# Generated deterministically by seda-macro-lef-normalizer-v1; recipe orfs-asap7-fakeram-m4-v1.
VERSION 5.8 ;
BUSBITCHARS "[]" ;
DIVIDERCHAR "/" ;

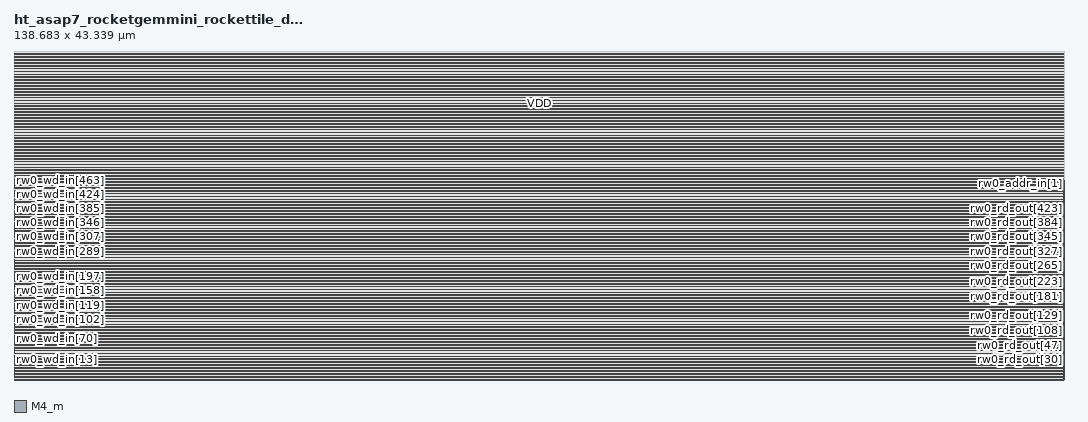
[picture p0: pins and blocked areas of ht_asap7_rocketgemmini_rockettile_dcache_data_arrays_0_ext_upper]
MACRO ht_asap7_rocketgemmini_rockettile_dcache_data_arrays_0_ext_upper
  FOREIGN ht_asap7_rocketgemmini_rockettile_dcache_data_arrays_0_ext_upper 0 0 ;
  CLASS COVER ;
  ORIGIN 0 0 ;
  SIZE 138.683 BY 43.339 ;
  SYMMETRY X Y R90 ;
  PIN rw0_wmask_in[0]
    DIRECTION INPUT ;
    USE SIGNAL ;
    SHAPE ABUTMENT ;
    PORT
      LAYER M4_m ;
      RECT 0 0.048 0.024 0.072 ;
    END
  END rw0_wmask_in[0]
  PIN rw0_wmask_in[1]
    DIRECTION INPUT ;
    USE SIGNAL ;
    SHAPE ABUTMENT ;
    PORT
      LAYER M4_m ;
      RECT 0 0.096 0.024 0.12 ;
    END
  END rw0_wmask_in[1]
  PIN rw0_wmask_in[2]
    DIRECTION INPUT ;
    USE SIGNAL ;
    SHAPE ABUTMENT ;
    PORT
      LAYER M4_m ;
      RECT 0 0.144 0.024 0.168 ;
    END
  END rw0_wmask_in[2]
  PIN rw0_wmask_in[3]
    DIRECTION INPUT ;
    USE SIGNAL ;
    SHAPE ABUTMENT ;
    PORT
      LAYER M4_m ;
      RECT 0 0.192 0.024 0.216 ;
    END
  END rw0_wmask_in[3]
  PIN rw0_wmask_in[4]
    DIRECTION INPUT ;
    USE SIGNAL ;
    SHAPE ABUTMENT ;
    PORT
      LAYER M4_m ;
      RECT 0 0.24 0.024 0.264 ;
    END
  END rw0_wmask_in[4]
  PIN rw0_wmask_in[5]
    DIRECTION INPUT ;
    USE SIGNAL ;
    SHAPE ABUTMENT ;
    PORT
      LAYER M4_m ;
      RECT 0 0.288 0.024 0.312 ;
    END
  END rw0_wmask_in[5]
  PIN rw0_wmask_in[6]
    DIRECTION INPUT ;
    USE SIGNAL ;
    SHAPE ABUTMENT ;
    PORT
      LAYER M4_m ;
      RECT 0 0.336 0.024 0.36 ;
    END
  END rw0_wmask_in[6]
  PIN rw0_wmask_in[7]
    DIRECTION INPUT ;
    USE SIGNAL ;
    SHAPE ABUTMENT ;
    PORT
      LAYER M4_m ;
      RECT 0 0.384 0.024 0.408 ;
    END
  END rw0_wmask_in[7]
  PIN rw0_wmask_in[8]
    DIRECTION INPUT ;
    USE SIGNAL ;
    SHAPE ABUTMENT ;
    PORT
      LAYER M4_m ;
      RECT 0 0.432 0.024 0.456 ;
    END
  END rw0_wmask_in[8]
  PIN rw0_wmask_in[9]
    DIRECTION INPUT ;
    USE SIGNAL ;
    SHAPE ABUTMENT ;
    PORT
      LAYER M4_m ;
      RECT 0 0.48 0.024 0.504 ;
    END
  END rw0_wmask_in[9]
  PIN rw0_wmask_in[10]
    DIRECTION INPUT ;
    USE SIGNAL ;
    SHAPE ABUTMENT ;
    PORT
      LAYER M4_m ;
      RECT 0 0.528 0.024 0.552 ;
    END
  END rw0_wmask_in[10]
  PIN rw0_wmask_in[11]
    DIRECTION INPUT ;
    USE SIGNAL ;
    SHAPE ABUTMENT ;
    PORT
      LAYER M4_m ;
      RECT 0 0.576 0.024 0.6 ;
    END
  END rw0_wmask_in[11]
  PIN rw0_wmask_in[12]
    DIRECTION INPUT ;
    USE SIGNAL ;
    SHAPE ABUTMENT ;
    PORT
      LAYER M4_m ;
      RECT 0 0.624 0.024 0.648 ;
    END
  END rw0_wmask_in[12]
  PIN rw0_wmask_in[13]
    DIRECTION INPUT ;
    USE SIGNAL ;
    SHAPE ABUTMENT ;
    PORT
      LAYER M4_m ;
      RECT 0 0.672 0.024 0.696 ;
    END
  END rw0_wmask_in[13]
  PIN rw0_wmask_in[14]
    DIRECTION INPUT ;
    USE SIGNAL ;
    SHAPE ABUTMENT ;
    PORT
      LAYER M4_m ;
      RECT 0 0.72 0.024 0.744 ;
    END
  END rw0_wmask_in[14]
  PIN rw0_wmask_in[15]
    DIRECTION INPUT ;
    USE SIGNAL ;
    SHAPE ABUTMENT ;
    PORT
      LAYER M4_m ;
      RECT 0 0.768 0.024 0.792 ;
    END
  END rw0_wmask_in[15]
  PIN rw0_wmask_in[16]
    DIRECTION INPUT ;
    USE SIGNAL ;
    SHAPE ABUTMENT ;
    PORT
      LAYER M4_m ;
      RECT 0 0.816 0.024 0.84 ;
    END
  END rw0_wmask_in[16]
  PIN rw0_wmask_in[17]
    DIRECTION INPUT ;
    USE SIGNAL ;
    SHAPE ABUTMENT ;
    PORT
      LAYER M4_m ;
      RECT 0 0.864 0.024 0.888 ;
    END
  END rw0_wmask_in[17]
  PIN rw0_wmask_in[18]
    DIRECTION INPUT ;
    USE SIGNAL ;
    SHAPE ABUTMENT ;
    PORT
      LAYER M4_m ;
      RECT 0 0.912 0.024 0.936 ;
    END
  END rw0_wmask_in[18]
  PIN rw0_wmask_in[19]
    DIRECTION INPUT ;
    USE SIGNAL ;
    SHAPE ABUTMENT ;
    PORT
      LAYER M4_m ;
      RECT 0 0.96 0.024 0.984 ;
    END
  END rw0_wmask_in[19]
  PIN rw0_wmask_in[20]
    DIRECTION INPUT ;
    USE SIGNAL ;
    SHAPE ABUTMENT ;
    PORT
      LAYER M4_m ;
      RECT 0 1.008 0.024 1.032 ;
    END
  END rw0_wmask_in[20]
  PIN rw0_wmask_in[21]
    DIRECTION INPUT ;
    USE SIGNAL ;
    SHAPE ABUTMENT ;
    PORT
      LAYER M4_m ;
      RECT 0 1.056 0.024 1.08 ;
    END
  END rw0_wmask_in[21]
  PIN rw0_wmask_in[22]
    DIRECTION INPUT ;
    USE SIGNAL ;
    SHAPE ABUTMENT ;
    PORT
      LAYER M4_m ;
      RECT 0 1.104 0.024 1.128 ;
    END
  END rw0_wmask_in[22]
  PIN rw0_wmask_in[23]
    DIRECTION INPUT ;
    USE SIGNAL ;
    SHAPE ABUTMENT ;
    PORT
      LAYER M4_m ;
      RECT 0 1.152 0.024 1.176 ;
    END
  END rw0_wmask_in[23]
  PIN rw0_wmask_in[24]
    DIRECTION INPUT ;
    USE SIGNAL ;
    SHAPE ABUTMENT ;
    PORT
      LAYER M4_m ;
      RECT 0 1.2 0.024 1.224 ;
    END
  END rw0_wmask_in[24]
  PIN rw0_wmask_in[25]
    DIRECTION INPUT ;
    USE SIGNAL ;
    SHAPE ABUTMENT ;
    PORT
      LAYER M4_m ;
      RECT 0 1.248 0.024 1.272 ;
    END
  END rw0_wmask_in[25]
  PIN rw0_wmask_in[26]
    DIRECTION INPUT ;
    USE SIGNAL ;
    SHAPE ABUTMENT ;
    PORT
      LAYER M4_m ;
      RECT 0 1.296 0.024 1.32 ;
    END
  END rw0_wmask_in[26]
  PIN rw0_wmask_in[27]
    DIRECTION INPUT ;
    USE SIGNAL ;
    SHAPE ABUTMENT ;
    PORT
      LAYER M4_m ;
      RECT 0 1.344 0.024 1.368 ;
    END
  END rw0_wmask_in[27]
  PIN rw0_wmask_in[28]
    DIRECTION INPUT ;
    USE SIGNAL ;
    SHAPE ABUTMENT ;
    PORT
      LAYER M4_m ;
      RECT 0 1.392 0.024 1.416 ;
    END
  END rw0_wmask_in[28]
  PIN rw0_wmask_in[29]
    DIRECTION INPUT ;
    USE SIGNAL ;
    SHAPE ABUTMENT ;
    PORT
      LAYER M4_m ;
      RECT 0 1.44 0.024 1.464 ;
    END
  END rw0_wmask_in[29]
  PIN rw0_wmask_in[30]
    DIRECTION INPUT ;
    USE SIGNAL ;
    SHAPE ABUTMENT ;
    PORT
      LAYER M4_m ;
      RECT 0 1.488 0.024 1.512 ;
    END
  END rw0_wmask_in[30]
  PIN rw0_wmask_in[31]
    DIRECTION INPUT ;
    USE SIGNAL ;
    SHAPE ABUTMENT ;
    PORT
      LAYER M4_m ;
      RECT 0 1.536 0.024 1.56 ;
    END
  END rw0_wmask_in[31]
  PIN rw0_wmask_in[32]
    DIRECTION INPUT ;
    USE SIGNAL ;
    SHAPE ABUTMENT ;
    PORT
      LAYER M4_m ;
      RECT 0 1.584 0.024 1.608 ;
    END
  END rw0_wmask_in[32]
  PIN rw0_wmask_in[33]
    DIRECTION INPUT ;
    USE SIGNAL ;
    SHAPE ABUTMENT ;
    PORT
      LAYER M4_m ;
      RECT 0 1.632 0.024 1.656 ;
    END
  END rw0_wmask_in[33]
  PIN rw0_wmask_in[34]
    DIRECTION INPUT ;
    USE SIGNAL ;
    SHAPE ABUTMENT ;
    PORT
      LAYER M4_m ;
      RECT 0 1.68 0.024 1.704 ;
    END
  END rw0_wmask_in[34]
  PIN rw0_wmask_in[35]
    DIRECTION INPUT ;
    USE SIGNAL ;
    SHAPE ABUTMENT ;
    PORT
      LAYER M4_m ;
      RECT 0 1.728 0.024 1.752 ;
    END
  END rw0_wmask_in[35]
  PIN rw0_wmask_in[36]
    DIRECTION INPUT ;
    USE SIGNAL ;
    SHAPE ABUTMENT ;
    PORT
      LAYER M4_m ;
      RECT 0 1.776 0.024 1.8 ;
    END
  END rw0_wmask_in[36]
  PIN rw0_wmask_in[37]
    DIRECTION INPUT ;
    USE SIGNAL ;
    SHAPE ABUTMENT ;
    PORT
      LAYER M4_m ;
      RECT 0 1.824 0.024 1.848 ;
    END
  END rw0_wmask_in[37]
  PIN rw0_wmask_in[38]
    DIRECTION INPUT ;
    USE SIGNAL ;
    SHAPE ABUTMENT ;
    PORT
      LAYER M4_m ;
      RECT 0 1.872 0.024 1.896 ;
    END
  END rw0_wmask_in[38]
  PIN rw0_wmask_in[39]
    DIRECTION INPUT ;
    USE SIGNAL ;
    SHAPE ABUTMENT ;
    PORT
      LAYER M4_m ;
      RECT 0 1.92 0.024 1.944 ;
    END
  END rw0_wmask_in[39]
  PIN rw0_wmask_in[40]
    DIRECTION INPUT ;
    USE SIGNAL ;
    SHAPE ABUTMENT ;
    PORT
      LAYER M4_m ;
      RECT 0 1.968 0.024 1.992 ;
    END
  END rw0_wmask_in[40]
  PIN rw0_wmask_in[41]
    DIRECTION INPUT ;
    USE SIGNAL ;
    SHAPE ABUTMENT ;
    PORT
      LAYER M4_m ;
      RECT 0 2.016 0.024 2.04 ;
    END
  END rw0_wmask_in[41]
  PIN rw0_wmask_in[42]
    DIRECTION INPUT ;
    USE SIGNAL ;
    SHAPE ABUTMENT ;
    PORT
      LAYER M4_m ;
      RECT 0 2.064 0.024 2.088 ;
    END
  END rw0_wmask_in[42]
  PIN rw0_wmask_in[43]
    DIRECTION INPUT ;
    USE SIGNAL ;
    SHAPE ABUTMENT ;
    PORT
      LAYER M4_m ;
      RECT 0 2.112 0.024 2.136 ;
    END
  END rw0_wmask_in[43]
  PIN rw0_wmask_in[44]
    DIRECTION INPUT ;
    USE SIGNAL ;
    SHAPE ABUTMENT ;
    PORT
      LAYER M4_m ;
      RECT 0 2.16 0.024 2.184 ;
    END
  END rw0_wmask_in[44]
  PIN rw0_wmask_in[45]
    DIRECTION INPUT ;
    USE SIGNAL ;
    SHAPE ABUTMENT ;
    PORT
      LAYER M4_m ;
      RECT 0 2.208 0.024 2.232 ;
    END
  END rw0_wmask_in[45]
  PIN rw0_wmask_in[46]
    DIRECTION INPUT ;
    USE SIGNAL ;
    SHAPE ABUTMENT ;
    PORT
      LAYER M4_m ;
      RECT 0 2.256 0.024 2.28 ;
    END
  END rw0_wmask_in[46]
  PIN rw0_wmask_in[47]
    DIRECTION INPUT ;
    USE SIGNAL ;
    SHAPE ABUTMENT ;
    PORT
      LAYER M4_m ;
      RECT 0 2.304 0.024 2.328 ;
    END
  END rw0_wmask_in[47]
  PIN rw0_wmask_in[48]
    DIRECTION INPUT ;
    USE SIGNAL ;
    SHAPE ABUTMENT ;
    PORT
      LAYER M4_m ;
      RECT 0 2.352 0.024 2.376 ;
    END
  END rw0_wmask_in[48]
  PIN rw0_wmask_in[49]
    DIRECTION INPUT ;
    USE SIGNAL ;
    SHAPE ABUTMENT ;
    PORT
      LAYER M4_m ;
      RECT 0 2.4 0.024 2.424 ;
    END
  END rw0_wmask_in[49]
  PIN rw0_wmask_in[50]
    DIRECTION INPUT ;
    USE SIGNAL ;
    SHAPE ABUTMENT ;
    PORT
      LAYER M4_m ;
      RECT 0 2.448 0.024 2.472 ;
    END
  END rw0_wmask_in[50]
  PIN rw0_wmask_in[51]
    DIRECTION INPUT ;
    USE SIGNAL ;
    SHAPE ABUTMENT ;
    PORT
      LAYER M4_m ;
      RECT 0 2.496 0.024 2.52 ;
    END
  END rw0_wmask_in[51]
  PIN rw0_wmask_in[52]
    DIRECTION INPUT ;
    USE SIGNAL ;
    SHAPE ABUTMENT ;
    PORT
      LAYER M4_m ;
      RECT 0 2.544 0.024 2.568 ;
    END
  END rw0_wmask_in[52]
  PIN rw0_wmask_in[53]
    DIRECTION INPUT ;
    USE SIGNAL ;
    SHAPE ABUTMENT ;
    PORT
      LAYER M4_m ;
      RECT 0 2.592 0.024 2.616 ;
    END
  END rw0_wmask_in[53]
  PIN rw0_wmask_in[54]
    DIRECTION INPUT ;
    USE SIGNAL ;
    SHAPE ABUTMENT ;
    PORT
      LAYER M4_m ;
      RECT 0 2.64 0.024 2.664 ;
    END
  END rw0_wmask_in[54]
  PIN rw0_wmask_in[55]
    DIRECTION INPUT ;
    USE SIGNAL ;
    SHAPE ABUTMENT ;
    PORT
      LAYER M4_m ;
      RECT 0 2.688 0.024 2.712 ;
    END
  END rw0_wmask_in[55]
  PIN rw0_wmask_in[56]
    DIRECTION INPUT ;
    USE SIGNAL ;
    SHAPE ABUTMENT ;
    PORT
      LAYER M4_m ;
      RECT 0 2.736 0.024 2.76 ;
    END
  END rw0_wmask_in[56]
  PIN rw0_wmask_in[57]
    DIRECTION INPUT ;
    USE SIGNAL ;
    SHAPE ABUTMENT ;
    PORT
      LAYER M4_m ;
      RECT 0 2.784 0.024 2.808 ;
    END
  END rw0_wmask_in[57]
  PIN rw0_wmask_in[58]
    DIRECTION INPUT ;
    USE SIGNAL ;
    SHAPE ABUTMENT ;
    PORT
      LAYER M4_m ;
      RECT 0 2.832 0.024 2.856 ;
    END
  END rw0_wmask_in[58]
  PIN rw0_wmask_in[59]
    DIRECTION INPUT ;
    USE SIGNAL ;
    SHAPE ABUTMENT ;
    PORT
      LAYER M4_m ;
      RECT 0 2.88 0.024 2.904 ;
    END
  END rw0_wmask_in[59]
  PIN rw0_wmask_in[60]
    DIRECTION INPUT ;
    USE SIGNAL ;
    SHAPE ABUTMENT ;
    PORT
      LAYER M4_m ;
      RECT 0 2.928 0.024 2.952 ;
    END
  END rw0_wmask_in[60]
  PIN rw0_wmask_in[61]
    DIRECTION INPUT ;
    USE SIGNAL ;
    SHAPE ABUTMENT ;
    PORT
      LAYER M4_m ;
      RECT 0 2.976 0.024 3 ;
    END
  END rw0_wmask_in[61]
  PIN rw0_wmask_in[62]
    DIRECTION INPUT ;
    USE SIGNAL ;
    SHAPE ABUTMENT ;
    PORT
      LAYER M4_m ;
      RECT 0 3.024 0.024 3.048 ;
    END
  END rw0_wmask_in[62]
  PIN rw0_wmask_in[63]
    DIRECTION INPUT ;
    USE SIGNAL ;
    SHAPE ABUTMENT ;
    PORT
      LAYER M4_m ;
      RECT 0 3.072 0.024 3.096 ;
    END
  END rw0_wmask_in[63]
  PIN rw0_wd_in[0]
    DIRECTION INPUT ;
    USE SIGNAL ;
    SHAPE ABUTMENT ;
    PORT
      LAYER M4_m ;
      RECT 0 3.12 0.024 3.144 ;
    END
  END rw0_wd_in[0]
  PIN rw0_wd_in[1]
    DIRECTION INPUT ;
    USE SIGNAL ;
    SHAPE ABUTMENT ;
    PORT
      LAYER M4_m ;
      RECT 0 3.168 0.024 3.192 ;
    END
  END rw0_wd_in[1]
  PIN rw0_wd_in[2]
    DIRECTION INPUT ;
    USE SIGNAL ;
    SHAPE ABUTMENT ;
    PORT
      LAYER M4_m ;
      RECT 0 3.216 0.024 3.24 ;
    END
  END rw0_wd_in[2]
  PIN rw0_wd_in[3]
    DIRECTION INPUT ;
    USE SIGNAL ;
    SHAPE ABUTMENT ;
    PORT
      LAYER M4_m ;
      RECT 0 3.264 0.024 3.288 ;
    END
  END rw0_wd_in[3]
  PIN rw0_wd_in[4]
    DIRECTION INPUT ;
    USE SIGNAL ;
    SHAPE ABUTMENT ;
    PORT
      LAYER M4_m ;
      RECT 0 3.312 0.024 3.336 ;
    END
  END rw0_wd_in[4]
  PIN rw0_wd_in[5]
    DIRECTION INPUT ;
    USE SIGNAL ;
    SHAPE ABUTMENT ;
    PORT
      LAYER M4_m ;
      RECT 0 3.36 0.024 3.384 ;
    END
  END rw0_wd_in[5]
  PIN rw0_wd_in[6]
    DIRECTION INPUT ;
    USE SIGNAL ;
    SHAPE ABUTMENT ;
    PORT
      LAYER M4_m ;
      RECT 0 3.408 0.024 3.432 ;
    END
  END rw0_wd_in[6]
  PIN rw0_wd_in[7]
    DIRECTION INPUT ;
    USE SIGNAL ;
    SHAPE ABUTMENT ;
    PORT
      LAYER M4_m ;
      RECT 0 3.456 0.024 3.48 ;
    END
  END rw0_wd_in[7]
  PIN rw0_wd_in[8]
    DIRECTION INPUT ;
    USE SIGNAL ;
    SHAPE ABUTMENT ;
    PORT
      LAYER M4_m ;
      RECT 0 3.504 0.024 3.528 ;
    END
  END rw0_wd_in[8]
  PIN rw0_wd_in[9]
    DIRECTION INPUT ;
    USE SIGNAL ;
    SHAPE ABUTMENT ;
    PORT
      LAYER M4_m ;
      RECT 0 3.552 0.024 3.576 ;
    END
  END rw0_wd_in[9]
  PIN rw0_wd_in[10]
    DIRECTION INPUT ;
    USE SIGNAL ;
    SHAPE ABUTMENT ;
    PORT
      LAYER M4_m ;
      RECT 0 3.6 0.024 3.624 ;
    END
  END rw0_wd_in[10]
  PIN rw0_wd_in[11]
    DIRECTION INPUT ;
    USE SIGNAL ;
    SHAPE ABUTMENT ;
    PORT
      LAYER M4_m ;
      RECT 0 3.648 0.024 3.672 ;
    END
  END rw0_wd_in[11]
  PIN rw0_wd_in[12]
    DIRECTION INPUT ;
    USE SIGNAL ;
    SHAPE ABUTMENT ;
    PORT
      LAYER M4_m ;
      RECT 0 3.696 0.024 3.72 ;
    END
  END rw0_wd_in[12]
  PIN rw0_wd_in[13]
    DIRECTION INPUT ;
    USE SIGNAL ;
    SHAPE ABUTMENT ;
    PORT
      LAYER M4_m ;
      RECT 0 3.744 0.024 3.768 ;
    END
  END rw0_wd_in[13]
  PIN rw0_wd_in[14]
    DIRECTION INPUT ;
    USE SIGNAL ;
    SHAPE ABUTMENT ;
    PORT
      LAYER M4_m ;
      RECT 0 3.792 0.024 3.816 ;
    END
  END rw0_wd_in[14]
  PIN rw0_wd_in[15]
    DIRECTION INPUT ;
    USE SIGNAL ;
    SHAPE ABUTMENT ;
    PORT
      LAYER M4_m ;
      RECT 0 3.84 0.024 3.864 ;
    END
  END rw0_wd_in[15]
  PIN rw0_wd_in[16]
    DIRECTION INPUT ;
    USE SIGNAL ;
    SHAPE ABUTMENT ;
    PORT
      LAYER M4_m ;
      RECT 0 3.888 0.024 3.912 ;
    END
  END rw0_wd_in[16]
  PIN rw0_wd_in[17]
    DIRECTION INPUT ;
    USE SIGNAL ;
    SHAPE ABUTMENT ;
    PORT
      LAYER M4_m ;
      RECT 0 3.936 0.024 3.96 ;
    END
  END rw0_wd_in[17]
  PIN rw0_wd_in[18]
    DIRECTION INPUT ;
    USE SIGNAL ;
    SHAPE ABUTMENT ;
    PORT
      LAYER M4_m ;
      RECT 0 3.984 0.024 4.008 ;
    END
  END rw0_wd_in[18]
  PIN rw0_wd_in[19]
    DIRECTION INPUT ;
    USE SIGNAL ;
    SHAPE ABUTMENT ;
    PORT
      LAYER M4_m ;
      RECT 0 4.032 0.024 4.056 ;
    END
  END rw0_wd_in[19]
  PIN rw0_wd_in[20]
    DIRECTION INPUT ;
    USE SIGNAL ;
    SHAPE ABUTMENT ;
    PORT
      LAYER M4_m ;
      RECT 0 4.08 0.024 4.104 ;
    END
  END rw0_wd_in[20]
  PIN rw0_wd_in[21]
    DIRECTION INPUT ;
    USE SIGNAL ;
    SHAPE ABUTMENT ;
    PORT
      LAYER M4_m ;
      RECT 0 4.128 0.024 4.152 ;
    END
  END rw0_wd_in[21]
  PIN rw0_wd_in[22]
    DIRECTION INPUT ;
    USE SIGNAL ;
    SHAPE ABUTMENT ;
    PORT
      LAYER M4_m ;
      RECT 0 4.176 0.024 4.2 ;
    END
  END rw0_wd_in[22]
  PIN rw0_wd_in[23]
    DIRECTION INPUT ;
    USE SIGNAL ;
    SHAPE ABUTMENT ;
    PORT
      LAYER M4_m ;
      RECT 0 4.224 0.024 4.248 ;
    END
  END rw0_wd_in[23]
  PIN rw0_wd_in[24]
    DIRECTION INPUT ;
    USE SIGNAL ;
    SHAPE ABUTMENT ;
    PORT
      LAYER M4_m ;
      RECT 0 4.272 0.024 4.296 ;
    END
  END rw0_wd_in[24]
  PIN rw0_wd_in[25]
    DIRECTION INPUT ;
    USE SIGNAL ;
    SHAPE ABUTMENT ;
    PORT
      LAYER M4_m ;
      RECT 0 4.32 0.024 4.344 ;
    END
  END rw0_wd_in[25]
  PIN rw0_wd_in[26]
    DIRECTION INPUT ;
    USE SIGNAL ;
    SHAPE ABUTMENT ;
    PORT
      LAYER M4_m ;
      RECT 0 4.368 0.024 4.392 ;
    END
  END rw0_wd_in[26]
  PIN rw0_wd_in[27]
    DIRECTION INPUT ;
    USE SIGNAL ;
    SHAPE ABUTMENT ;
    PORT
      LAYER M4_m ;
      RECT 0 4.416 0.024 4.44 ;
    END
  END rw0_wd_in[27]
  PIN rw0_wd_in[28]
    DIRECTION INPUT ;
    USE SIGNAL ;
    SHAPE ABUTMENT ;
    PORT
      LAYER M4_m ;
      RECT 0 4.464 0.024 4.488 ;
    END
  END rw0_wd_in[28]
  PIN rw0_wd_in[29]
    DIRECTION INPUT ;
    USE SIGNAL ;
    SHAPE ABUTMENT ;
    PORT
      LAYER M4_m ;
      RECT 0 4.512 0.024 4.536 ;
    END
  END rw0_wd_in[29]
  PIN rw0_wd_in[30]
    DIRECTION INPUT ;
    USE SIGNAL ;
    SHAPE ABUTMENT ;
    PORT
      LAYER M4_m ;
      RECT 0 4.56 0.024 4.584 ;
    END
  END rw0_wd_in[30]
  PIN rw0_wd_in[31]
    DIRECTION INPUT ;
    USE SIGNAL ;
    SHAPE ABUTMENT ;
    PORT
      LAYER M4_m ;
      RECT 0 4.608 0.024 4.632 ;
    END
  END rw0_wd_in[31]
  PIN rw0_wd_in[32]
    DIRECTION INPUT ;
    USE SIGNAL ;
    SHAPE ABUTMENT ;
    PORT
      LAYER M4_m ;
      RECT 0 4.656 0.024 4.68 ;
    END
  END rw0_wd_in[32]
  PIN rw0_wd_in[33]
    DIRECTION INPUT ;
    USE SIGNAL ;
    SHAPE ABUTMENT ;
    PORT
      LAYER M4_m ;
      RECT 0 4.704 0.024 4.728 ;
    END
  END rw0_wd_in[33]
  PIN rw0_wd_in[34]
    DIRECTION INPUT ;
    USE SIGNAL ;
    SHAPE ABUTMENT ;
    PORT
      LAYER M4_m ;
      RECT 0 4.752 0.024 4.776 ;
    END
  END rw0_wd_in[34]
  PIN rw0_wd_in[35]
    DIRECTION INPUT ;
    USE SIGNAL ;
    SHAPE ABUTMENT ;
    PORT
      LAYER M4_m ;
      RECT 0 4.8 0.024 4.824 ;
    END
  END rw0_wd_in[35]
  PIN rw0_wd_in[36]
    DIRECTION INPUT ;
    USE SIGNAL ;
    SHAPE ABUTMENT ;
    PORT
      LAYER M4_m ;
      RECT 0 4.848 0.024 4.872 ;
    END
  END rw0_wd_in[36]
  PIN rw0_wd_in[37]
    DIRECTION INPUT ;
    USE SIGNAL ;
    SHAPE ABUTMENT ;
    PORT
      LAYER M4_m ;
      RECT 0 4.896 0.024 4.92 ;
    END
  END rw0_wd_in[37]
  PIN rw0_wd_in[38]
    DIRECTION INPUT ;
    USE SIGNAL ;
    SHAPE ABUTMENT ;
    PORT
      LAYER M4_m ;
      RECT 0 4.944 0.024 4.968 ;
    END
  END rw0_wd_in[38]
  PIN rw0_wd_in[39]
    DIRECTION INPUT ;
    USE SIGNAL ;
    SHAPE ABUTMENT ;
    PORT
      LAYER M4_m ;
      RECT 0 4.992 0.024 5.016 ;
    END
  END rw0_wd_in[39]
  PIN rw0_wd_in[40]
    DIRECTION INPUT ;
    USE SIGNAL ;
    SHAPE ABUTMENT ;
    PORT
      LAYER M4_m ;
      RECT 0 5.04 0.024 5.064 ;
    END
  END rw0_wd_in[40]
  PIN rw0_wd_in[41]
    DIRECTION INPUT ;
    USE SIGNAL ;
    SHAPE ABUTMENT ;
    PORT
      LAYER M4_m ;
      RECT 0 5.088 0.024 5.112 ;
    END
  END rw0_wd_in[41]
  PIN rw0_wd_in[42]
    DIRECTION INPUT ;
    USE SIGNAL ;
    SHAPE ABUTMENT ;
    PORT
      LAYER M4_m ;
      RECT 0 5.136 0.024 5.16 ;
    END
  END rw0_wd_in[42]
  PIN rw0_wd_in[43]
    DIRECTION INPUT ;
    USE SIGNAL ;
    SHAPE ABUTMENT ;
    PORT
      LAYER M4_m ;
      RECT 0 5.184 0.024 5.208 ;
    END
  END rw0_wd_in[43]
  PIN rw0_wd_in[44]
    DIRECTION INPUT ;
    USE SIGNAL ;
    SHAPE ABUTMENT ;
    PORT
      LAYER M4_m ;
      RECT 0 5.232 0.024 5.256 ;
    END
  END rw0_wd_in[44]
  PIN rw0_wd_in[45]
    DIRECTION INPUT ;
    USE SIGNAL ;
    SHAPE ABUTMENT ;
    PORT
      LAYER M4_m ;
      RECT 0 5.28 0.024 5.304 ;
    END
  END rw0_wd_in[45]
  PIN rw0_wd_in[46]
    DIRECTION INPUT ;
    USE SIGNAL ;
    SHAPE ABUTMENT ;
    PORT
      LAYER M4_m ;
      RECT 0 5.328 0.024 5.352 ;
    END
  END rw0_wd_in[46]
  PIN rw0_wd_in[47]
    DIRECTION INPUT ;
    USE SIGNAL ;
    SHAPE ABUTMENT ;
    PORT
      LAYER M4_m ;
      RECT 0 5.376 0.024 5.4 ;
    END
  END rw0_wd_in[47]
  PIN rw0_wd_in[48]
    DIRECTION INPUT ;
    USE SIGNAL ;
    SHAPE ABUTMENT ;
    PORT
      LAYER M4_m ;
      RECT 0 5.424 0.024 5.448 ;
    END
  END rw0_wd_in[48]
  PIN rw0_wd_in[49]
    DIRECTION INPUT ;
    USE SIGNAL ;
    SHAPE ABUTMENT ;
    PORT
      LAYER M4_m ;
      RECT 0 5.472 0.024 5.496 ;
    END
  END rw0_wd_in[49]
  PIN rw0_wd_in[50]
    DIRECTION INPUT ;
    USE SIGNAL ;
    SHAPE ABUTMENT ;
    PORT
      LAYER M4_m ;
      RECT 0 5.52 0.024 5.544 ;
    END
  END rw0_wd_in[50]
  PIN rw0_wd_in[51]
    DIRECTION INPUT ;
    USE SIGNAL ;
    SHAPE ABUTMENT ;
    PORT
      LAYER M4_m ;
      RECT 0 5.568 0.024 5.592 ;
    END
  END rw0_wd_in[51]
  PIN rw0_wd_in[52]
    DIRECTION INPUT ;
    USE SIGNAL ;
    SHAPE ABUTMENT ;
    PORT
      LAYER M4_m ;
      RECT 0 5.616 0.024 5.64 ;
    END
  END rw0_wd_in[52]
  PIN rw0_wd_in[53]
    DIRECTION INPUT ;
    USE SIGNAL ;
    SHAPE ABUTMENT ;
    PORT
      LAYER M4_m ;
      RECT 0 5.664 0.024 5.688 ;
    END
  END rw0_wd_in[53]
  PIN rw0_wd_in[54]
    DIRECTION INPUT ;
    USE SIGNAL ;
    SHAPE ABUTMENT ;
    PORT
      LAYER M4_m ;
      RECT 0 5.712 0.024 5.736 ;
    END
  END rw0_wd_in[54]
  PIN rw0_wd_in[55]
    DIRECTION INPUT ;
    USE SIGNAL ;
    SHAPE ABUTMENT ;
    PORT
      LAYER M4_m ;
      RECT 0 5.76 0.024 5.784 ;
    END
  END rw0_wd_in[55]
  PIN rw0_wd_in[56]
    DIRECTION INPUT ;
    USE SIGNAL ;
    SHAPE ABUTMENT ;
    PORT
      LAYER M4_m ;
      RECT 0 5.808 0.024 5.832 ;
    END
  END rw0_wd_in[56]
  PIN rw0_wd_in[57]
    DIRECTION INPUT ;
    USE SIGNAL ;
    SHAPE ABUTMENT ;
    PORT
      LAYER M4_m ;
      RECT 0 5.856 0.024 5.88 ;
    END
  END rw0_wd_in[57]
  PIN rw0_wd_in[58]
    DIRECTION INPUT ;
    USE SIGNAL ;
    SHAPE ABUTMENT ;
    PORT
      LAYER M4_m ;
      RECT 0 5.904 0.024 5.928 ;
    END
  END rw0_wd_in[58]
  PIN rw0_wd_in[59]
    DIRECTION INPUT ;
    USE SIGNAL ;
    SHAPE ABUTMENT ;
    PORT
      LAYER M4_m ;
      RECT 0 5.952 0.024 5.976 ;
    END
  END rw0_wd_in[59]
  PIN rw0_wd_in[60]
    DIRECTION INPUT ;
    USE SIGNAL ;
    SHAPE ABUTMENT ;
    PORT
      LAYER M4_m ;
      RECT 0 6 0.024 6.024 ;
    END
  END rw0_wd_in[60]
  PIN rw0_wd_in[61]
    DIRECTION INPUT ;
    USE SIGNAL ;
    SHAPE ABUTMENT ;
    PORT
      LAYER M4_m ;
      RECT 0 6.048 0.024 6.072 ;
    END
  END rw0_wd_in[61]
  PIN rw0_wd_in[62]
    DIRECTION INPUT ;
    USE SIGNAL ;
    SHAPE ABUTMENT ;
    PORT
      LAYER M4_m ;
      RECT 0 6.096 0.024 6.12 ;
    END
  END rw0_wd_in[62]
  PIN rw0_wd_in[63]
    DIRECTION INPUT ;
    USE SIGNAL ;
    SHAPE ABUTMENT ;
    PORT
      LAYER M4_m ;
      RECT 0 6.144 0.024 6.168 ;
    END
  END rw0_wd_in[63]
  PIN rw0_wd_in[64]
    DIRECTION INPUT ;
    USE SIGNAL ;
    SHAPE ABUTMENT ;
    PORT
      LAYER M4_m ;
      RECT 0 6.192 0.024 6.216 ;
    END
  END rw0_wd_in[64]
  PIN rw0_wd_in[65]
    DIRECTION INPUT ;
    USE SIGNAL ;
    SHAPE ABUTMENT ;
    PORT
      LAYER M4_m ;
      RECT 0 6.24 0.024 6.264 ;
    END
  END rw0_wd_in[65]
  PIN rw0_wd_in[66]
    DIRECTION INPUT ;
    USE SIGNAL ;
    SHAPE ABUTMENT ;
    PORT
      LAYER M4_m ;
      RECT 0 6.288 0.024 6.312 ;
    END
  END rw0_wd_in[66]
  PIN rw0_wd_in[67]
    DIRECTION INPUT ;
    USE SIGNAL ;
    SHAPE ABUTMENT ;
    PORT
      LAYER M4_m ;
      RECT 0 6.336 0.024 6.36 ;
    END
  END rw0_wd_in[67]
  PIN rw0_wd_in[68]
    DIRECTION INPUT ;
    USE SIGNAL ;
    SHAPE ABUTMENT ;
    PORT
      LAYER M4_m ;
      RECT 0 6.384 0.024 6.408 ;
    END
  END rw0_wd_in[68]
  PIN rw0_wd_in[69]
    DIRECTION INPUT ;
    USE SIGNAL ;
    SHAPE ABUTMENT ;
    PORT
      LAYER M4_m ;
      RECT 0 6.432 0.024 6.456 ;
    END
  END rw0_wd_in[69]
  PIN rw0_wd_in[70]
    DIRECTION INPUT ;
    USE SIGNAL ;
    SHAPE ABUTMENT ;
    PORT
      LAYER M4_m ;
      RECT 0 6.48 0.024 6.504 ;
    END
  END rw0_wd_in[70]
  PIN rw0_wd_in[71]
    DIRECTION INPUT ;
    USE SIGNAL ;
    SHAPE ABUTMENT ;
    PORT
      LAYER M4_m ;
      RECT 0 6.528 0.024 6.552 ;
    END
  END rw0_wd_in[71]
  PIN rw0_wd_in[72]
    DIRECTION INPUT ;
    USE SIGNAL ;
    SHAPE ABUTMENT ;
    PORT
      LAYER M4_m ;
      RECT 0 6.576 0.024 6.6 ;
    END
  END rw0_wd_in[72]
  PIN rw0_wd_in[73]
    DIRECTION INPUT ;
    USE SIGNAL ;
    SHAPE ABUTMENT ;
    PORT
      LAYER M4_m ;
      RECT 0 6.624 0.024 6.648 ;
    END
  END rw0_wd_in[73]
  PIN rw0_wd_in[74]
    DIRECTION INPUT ;
    USE SIGNAL ;
    SHAPE ABUTMENT ;
    PORT
      LAYER M4_m ;
      RECT 0 6.672 0.024 6.696 ;
    END
  END rw0_wd_in[74]
  PIN rw0_wd_in[75]
    DIRECTION INPUT ;
    USE SIGNAL ;
    SHAPE ABUTMENT ;
    PORT
      LAYER M4_m ;
      RECT 0 6.72 0.024 6.744 ;
    END
  END rw0_wd_in[75]
  PIN rw0_wd_in[76]
    DIRECTION INPUT ;
    USE SIGNAL ;
    SHAPE ABUTMENT ;
    PORT
      LAYER M4_m ;
      RECT 0 6.768 0.024 6.792 ;
    END
  END rw0_wd_in[76]
  PIN rw0_wd_in[77]
    DIRECTION INPUT ;
    USE SIGNAL ;
    SHAPE ABUTMENT ;
    PORT
      LAYER M4_m ;
      RECT 0 6.816 0.024 6.84 ;
    END
  END rw0_wd_in[77]
  PIN rw0_wd_in[78]
    DIRECTION INPUT ;
    USE SIGNAL ;
    SHAPE ABUTMENT ;
    PORT
      LAYER M4_m ;
      RECT 0 6.864 0.024 6.888 ;
    END
  END rw0_wd_in[78]
  PIN rw0_wd_in[79]
    DIRECTION INPUT ;
    USE SIGNAL ;
    SHAPE ABUTMENT ;
    PORT
      LAYER M4_m ;
      RECT 0 6.912 0.024 6.936 ;
    END
  END rw0_wd_in[79]
  PIN rw0_wd_in[80]
    DIRECTION INPUT ;
    USE SIGNAL ;
    SHAPE ABUTMENT ;
    PORT
      LAYER M4_m ;
      RECT 0 6.96 0.024 6.984 ;
    END
  END rw0_wd_in[80]
  PIN rw0_wd_in[81]
    DIRECTION INPUT ;
    USE SIGNAL ;
    SHAPE ABUTMENT ;
    PORT
      LAYER M4_m ;
      RECT 0 7.008 0.024 7.032 ;
    END
  END rw0_wd_in[81]
  PIN rw0_wd_in[82]
    DIRECTION INPUT ;
    USE SIGNAL ;
    SHAPE ABUTMENT ;
    PORT
      LAYER M4_m ;
      RECT 0 7.056 0.024 7.08 ;
    END
  END rw0_wd_in[82]
  PIN rw0_wd_in[83]
    DIRECTION INPUT ;
    USE SIGNAL ;
    SHAPE ABUTMENT ;
    PORT
      LAYER M4_m ;
      RECT 0 7.104 0.024 7.128 ;
    END
  END rw0_wd_in[83]
  PIN rw0_wd_in[84]
    DIRECTION INPUT ;
    USE SIGNAL ;
    SHAPE ABUTMENT ;
    PORT
      LAYER M4_m ;
      RECT 0 7.152 0.024 7.176 ;
    END
  END rw0_wd_in[84]
  PIN rw0_wd_in[85]
    DIRECTION INPUT ;
    USE SIGNAL ;
    SHAPE ABUTMENT ;
    PORT
      LAYER M4_m ;
      RECT 0 7.2 0.024 7.224 ;
    END
  END rw0_wd_in[85]
  PIN rw0_wd_in[86]
    DIRECTION INPUT ;
    USE SIGNAL ;
    SHAPE ABUTMENT ;
    PORT
      LAYER M4_m ;
      RECT 0 7.248 0.024 7.272 ;
    END
  END rw0_wd_in[86]
  PIN rw0_wd_in[87]
    DIRECTION INPUT ;
    USE SIGNAL ;
    SHAPE ABUTMENT ;
    PORT
      LAYER M4_m ;
      RECT 0 7.296 0.024 7.32 ;
    END
  END rw0_wd_in[87]
  PIN rw0_wd_in[88]
    DIRECTION INPUT ;
    USE SIGNAL ;
    SHAPE ABUTMENT ;
    PORT
      LAYER M4_m ;
      RECT 0 7.344 0.024 7.368 ;
    END
  END rw0_wd_in[88]
  PIN rw0_wd_in[89]
    DIRECTION INPUT ;
    USE SIGNAL ;
    SHAPE ABUTMENT ;
    PORT
      LAYER M4_m ;
      RECT 0 7.392 0.024 7.416 ;
    END
  END rw0_wd_in[89]
  PIN rw0_wd_in[90]
    DIRECTION INPUT ;
    USE SIGNAL ;
    SHAPE ABUTMENT ;
    PORT
      LAYER M4_m ;
      RECT 0 7.44 0.024 7.464 ;
    END
  END rw0_wd_in[90]
  PIN rw0_wd_in[91]
    DIRECTION INPUT ;
    USE SIGNAL ;
    SHAPE ABUTMENT ;
    PORT
      LAYER M4_m ;
      RECT 0 7.488 0.024 7.512 ;
    END
  END rw0_wd_in[91]
  PIN rw0_wd_in[92]
    DIRECTION INPUT ;
    USE SIGNAL ;
    SHAPE ABUTMENT ;
    PORT
      LAYER M4_m ;
      RECT 0 7.536 0.024 7.56 ;
    END
  END rw0_wd_in[92]
  PIN rw0_wd_in[93]
    DIRECTION INPUT ;
    USE SIGNAL ;
    SHAPE ABUTMENT ;
    PORT
      LAYER M4_m ;
      RECT 0 7.584 0.024 7.608 ;
    END
  END rw0_wd_in[93]
  PIN rw0_wd_in[94]
    DIRECTION INPUT ;
    USE SIGNAL ;
    SHAPE ABUTMENT ;
    PORT
      LAYER M4_m ;
      RECT 0 7.632 0.024 7.656 ;
    END
  END rw0_wd_in[94]
  PIN rw0_wd_in[95]
    DIRECTION INPUT ;
    USE SIGNAL ;
    SHAPE ABUTMENT ;
    PORT
      LAYER M4_m ;
      RECT 0 7.68 0.024 7.704 ;
    END
  END rw0_wd_in[95]
  PIN rw0_wd_in[96]
    DIRECTION INPUT ;
    USE SIGNAL ;
    SHAPE ABUTMENT ;
    PORT
      LAYER M4_m ;
      RECT 0 7.728 0.024 7.752 ;
    END
  END rw0_wd_in[96]
  PIN rw0_wd_in[97]
    DIRECTION INPUT ;
    USE SIGNAL ;
    SHAPE ABUTMENT ;
    PORT
      LAYER M4_m ;
      RECT 0 7.776 0.024 7.8 ;
    END
  END rw0_wd_in[97]
  PIN rw0_wd_in[98]
    DIRECTION INPUT ;
    USE SIGNAL ;
    SHAPE ABUTMENT ;
    PORT
      LAYER M4_m ;
      RECT 0 7.824 0.024 7.848 ;
    END
  END rw0_wd_in[98]
  PIN rw0_wd_in[99]
    DIRECTION INPUT ;
    USE SIGNAL ;
    SHAPE ABUTMENT ;
    PORT
      LAYER M4_m ;
      RECT 0 7.872 0.024 7.896 ;
    END
  END rw0_wd_in[99]
  PIN rw0_wd_in[100]
    DIRECTION INPUT ;
    USE SIGNAL ;
    SHAPE ABUTMENT ;
    PORT
      LAYER M4_m ;
      RECT 0 7.92 0.024 7.944 ;
    END
  END rw0_wd_in[100]
  PIN rw0_wd_in[101]
    DIRECTION INPUT ;
    USE SIGNAL ;
    SHAPE ABUTMENT ;
    PORT
      LAYER M4_m ;
      RECT 0 7.968 0.024 7.992 ;
    END
  END rw0_wd_in[101]
  PIN rw0_wd_in[102]
    DIRECTION INPUT ;
    USE SIGNAL ;
    SHAPE ABUTMENT ;
    PORT
      LAYER M4_m ;
      RECT 0 8.016 0.024 8.04 ;
    END
  END rw0_wd_in[102]
  PIN rw0_wd_in[103]
    DIRECTION INPUT ;
    USE SIGNAL ;
    SHAPE ABUTMENT ;
    PORT
      LAYER M4_m ;
      RECT 0 8.064 0.024 8.088 ;
    END
  END rw0_wd_in[103]
  PIN rw0_wd_in[104]
    DIRECTION INPUT ;
    USE SIGNAL ;
    SHAPE ABUTMENT ;
    PORT
      LAYER M4_m ;
      RECT 0 8.112 0.024 8.136 ;
    END
  END rw0_wd_in[104]
  PIN rw0_wd_in[105]
    DIRECTION INPUT ;
    USE SIGNAL ;
    SHAPE ABUTMENT ;
    PORT
      LAYER M4_m ;
      RECT 0 8.16 0.024 8.184 ;
    END
  END rw0_wd_in[105]
  PIN rw0_wd_in[106]
    DIRECTION INPUT ;
    USE SIGNAL ;
    SHAPE ABUTMENT ;
    PORT
      LAYER M4_m ;
      RECT 0 8.208 0.024 8.232 ;
    END
  END rw0_wd_in[106]
  PIN rw0_wd_in[107]
    DIRECTION INPUT ;
    USE SIGNAL ;
    SHAPE ABUTMENT ;
    PORT
      LAYER M4_m ;
      RECT 0 8.256 0.024 8.28 ;
    END
  END rw0_wd_in[107]
  PIN rw0_wd_in[108]
    DIRECTION INPUT ;
    USE SIGNAL ;
    SHAPE ABUTMENT ;
    PORT
      LAYER M4_m ;
      RECT 0 8.304 0.024 8.328 ;
    END
  END rw0_wd_in[108]
  PIN rw0_wd_in[109]
    DIRECTION INPUT ;
    USE SIGNAL ;
    SHAPE ABUTMENT ;
    PORT
      LAYER M4_m ;
      RECT 0 8.352 0.024 8.376 ;
    END
  END rw0_wd_in[109]
  PIN rw0_wd_in[110]
    DIRECTION INPUT ;
    USE SIGNAL ;
    SHAPE ABUTMENT ;
    PORT
      LAYER M4_m ;
      RECT 0 8.4 0.024 8.424 ;
    END
  END rw0_wd_in[110]
  PIN rw0_wd_in[111]
    DIRECTION INPUT ;
    USE SIGNAL ;
    SHAPE ABUTMENT ;
    PORT
      LAYER M4_m ;
      RECT 0 8.448 0.024 8.472 ;
    END
  END rw0_wd_in[111]
  PIN rw0_wd_in[112]
    DIRECTION INPUT ;
    USE SIGNAL ;
    SHAPE ABUTMENT ;
    PORT
      LAYER M4_m ;
      RECT 0 8.496 0.024 8.52 ;
    END
  END rw0_wd_in[112]
  PIN rw0_wd_in[113]
    DIRECTION INPUT ;
    USE SIGNAL ;
    SHAPE ABUTMENT ;
    PORT
      LAYER M4_m ;
      RECT 0 8.544 0.024 8.568 ;
    END
  END rw0_wd_in[113]
  PIN rw0_wd_in[114]
    DIRECTION INPUT ;
    USE SIGNAL ;
    SHAPE ABUTMENT ;
    PORT
      LAYER M4_m ;
      RECT 0 8.592 0.024 8.616 ;
    END
  END rw0_wd_in[114]
  PIN rw0_wd_in[115]
    DIRECTION INPUT ;
    USE SIGNAL ;
    SHAPE ABUTMENT ;
    PORT
      LAYER M4_m ;
      RECT 0 8.64 0.024 8.664 ;
    END
  END rw0_wd_in[115]
  PIN rw0_wd_in[116]
    DIRECTION INPUT ;
    USE SIGNAL ;
    SHAPE ABUTMENT ;
    PORT
      LAYER M4_m ;
      RECT 0 8.688 0.024 8.712 ;
    END
  END rw0_wd_in[116]
  PIN rw0_wd_in[117]
    DIRECTION INPUT ;
    USE SIGNAL ;
    SHAPE ABUTMENT ;
    PORT
      LAYER M4_m ;
      RECT 0 8.736 0.024 8.76 ;
    END
  END rw0_wd_in[117]
  PIN rw0_wd_in[118]
    DIRECTION INPUT ;
    USE SIGNAL ;
    SHAPE ABUTMENT ;
    PORT
      LAYER M4_m ;
      RECT 0 8.784 0.024 8.808 ;
    END
  END rw0_wd_in[118]
  PIN rw0_wd_in[119]
    DIRECTION INPUT ;
    USE SIGNAL ;
    SHAPE ABUTMENT ;
    PORT
      LAYER M4_m ;
      RECT 0 8.832 0.024 8.856 ;
    END
  END rw0_wd_in[119]
  PIN rw0_wd_in[120]
    DIRECTION INPUT ;
    USE SIGNAL ;
    SHAPE ABUTMENT ;
    PORT
      LAYER M4_m ;
      RECT 0 8.88 0.024 8.904 ;
    END
  END rw0_wd_in[120]
  PIN rw0_wd_in[121]
    DIRECTION INPUT ;
    USE SIGNAL ;
    SHAPE ABUTMENT ;
    PORT
      LAYER M4_m ;
      RECT 0 8.928 0.024 8.952 ;
    END
  END rw0_wd_in[121]
  PIN rw0_wd_in[122]
    DIRECTION INPUT ;
    USE SIGNAL ;
    SHAPE ABUTMENT ;
    PORT
      LAYER M4_m ;
      RECT 0 8.976 0.024 9 ;
    END
  END rw0_wd_in[122]
  PIN rw0_wd_in[123]
    DIRECTION INPUT ;
    USE SIGNAL ;
    SHAPE ABUTMENT ;
    PORT
      LAYER M4_m ;
      RECT 0 9.024 0.024 9.048 ;
    END
  END rw0_wd_in[123]
  PIN rw0_wd_in[124]
    DIRECTION INPUT ;
    USE SIGNAL ;
    SHAPE ABUTMENT ;
    PORT
      LAYER M4_m ;
      RECT 0 9.072 0.024 9.096 ;
    END
  END rw0_wd_in[124]
  PIN rw0_wd_in[125]
    DIRECTION INPUT ;
    USE SIGNAL ;
    SHAPE ABUTMENT ;
    PORT
      LAYER M4_m ;
      RECT 0 9.12 0.024 9.144 ;
    END
  END rw0_wd_in[125]
  PIN rw0_wd_in[126]
    DIRECTION INPUT ;
    USE SIGNAL ;
    SHAPE ABUTMENT ;
    PORT
      LAYER M4_m ;
      RECT 0 9.168 0.024 9.192 ;
    END
  END rw0_wd_in[126]
  PIN rw0_wd_in[127]
    DIRECTION INPUT ;
    USE SIGNAL ;
    SHAPE ABUTMENT ;
    PORT
      LAYER M4_m ;
      RECT 0 9.216 0.024 9.24 ;
    END
  END rw0_wd_in[127]
  PIN rw0_wd_in[128]
    DIRECTION INPUT ;
    USE SIGNAL ;
    SHAPE ABUTMENT ;
    PORT
      LAYER M4_m ;
      RECT 0 9.264 0.024 9.288 ;
    END
  END rw0_wd_in[128]
  PIN rw0_wd_in[129]
    DIRECTION INPUT ;
    USE SIGNAL ;
    SHAPE ABUTMENT ;
    PORT
      LAYER M4_m ;
      RECT 0 9.312 0.024 9.336 ;
    END
  END rw0_wd_in[129]
  PIN rw0_wd_in[130]
    DIRECTION INPUT ;
    USE SIGNAL ;
    SHAPE ABUTMENT ;
    PORT
      LAYER M4_m ;
      RECT 0 9.36 0.024 9.384 ;
    END
  END rw0_wd_in[130]
  PIN rw0_wd_in[131]
    DIRECTION INPUT ;
    USE SIGNAL ;
    SHAPE ABUTMENT ;
    PORT
      LAYER M4_m ;
      RECT 0 9.408 0.024 9.432 ;
    END
  END rw0_wd_in[131]
  PIN rw0_wd_in[132]
    DIRECTION INPUT ;
    USE SIGNAL ;
    SHAPE ABUTMENT ;
    PORT
      LAYER M4_m ;
      RECT 0 9.456 0.024 9.48 ;
    END
  END rw0_wd_in[132]
  PIN rw0_wd_in[133]
    DIRECTION INPUT ;
    USE SIGNAL ;
    SHAPE ABUTMENT ;
    PORT
      LAYER M4_m ;
      RECT 0 9.504 0.024 9.528 ;
    END
  END rw0_wd_in[133]
  PIN rw0_wd_in[134]
    DIRECTION INPUT ;
    USE SIGNAL ;
    SHAPE ABUTMENT ;
    PORT
      LAYER M4_m ;
      RECT 0 9.552 0.024 9.576 ;
    END
  END rw0_wd_in[134]
  PIN rw0_wd_in[135]
    DIRECTION INPUT ;
    USE SIGNAL ;
    SHAPE ABUTMENT ;
    PORT
      LAYER M4_m ;
      RECT 0 9.6 0.024 9.624 ;
    END
  END rw0_wd_in[135]
  PIN rw0_wd_in[136]
    DIRECTION INPUT ;
    USE SIGNAL ;
    SHAPE ABUTMENT ;
    PORT
      LAYER M4_m ;
      RECT 0 9.648 0.024 9.672 ;
    END
  END rw0_wd_in[136]
  PIN rw0_wd_in[137]
    DIRECTION INPUT ;
    USE SIGNAL ;
    SHAPE ABUTMENT ;
    PORT
      LAYER M4_m ;
      RECT 0 9.696 0.024 9.72 ;
    END
  END rw0_wd_in[137]
  PIN rw0_wd_in[138]
    DIRECTION INPUT ;
    USE SIGNAL ;
    SHAPE ABUTMENT ;
    PORT
      LAYER M4_m ;
      RECT 0 9.744 0.024 9.768 ;
    END
  END rw0_wd_in[138]
  PIN rw0_wd_in[139]
    DIRECTION INPUT ;
    USE SIGNAL ;
    SHAPE ABUTMENT ;
    PORT
      LAYER M4_m ;
      RECT 0 9.792 0.024 9.816 ;
    END
  END rw0_wd_in[139]
  PIN rw0_wd_in[140]
    DIRECTION INPUT ;
    USE SIGNAL ;
    SHAPE ABUTMENT ;
    PORT
      LAYER M4_m ;
      RECT 0 9.84 0.024 9.864 ;
    END
  END rw0_wd_in[140]
  PIN rw0_wd_in[141]
    DIRECTION INPUT ;
    USE SIGNAL ;
    SHAPE ABUTMENT ;
    PORT
      LAYER M4_m ;
      RECT 0 9.888 0.024 9.912 ;
    END
  END rw0_wd_in[141]
  PIN rw0_wd_in[142]
    DIRECTION INPUT ;
    USE SIGNAL ;
    SHAPE ABUTMENT ;
    PORT
      LAYER M4_m ;
      RECT 0 9.936 0.024 9.96 ;
    END
  END rw0_wd_in[142]
  PIN rw0_wd_in[143]
    DIRECTION INPUT ;
    USE SIGNAL ;
    SHAPE ABUTMENT ;
    PORT
      LAYER M4_m ;
      RECT 0 9.984 0.024 10.008 ;
    END
  END rw0_wd_in[143]
  PIN rw0_wd_in[144]
    DIRECTION INPUT ;
    USE SIGNAL ;
    SHAPE ABUTMENT ;
    PORT
      LAYER M4_m ;
      RECT 0 10.032 0.024 10.056 ;
    END
  END rw0_wd_in[144]
  PIN rw0_wd_in[145]
    DIRECTION INPUT ;
    USE SIGNAL ;
    SHAPE ABUTMENT ;
    PORT
      LAYER M4_m ;
      RECT 0 10.08 0.024 10.104 ;
    END
  END rw0_wd_in[145]
  PIN rw0_wd_in[146]
    DIRECTION INPUT ;
    USE SIGNAL ;
    SHAPE ABUTMENT ;
    PORT
      LAYER M4_m ;
      RECT 0 10.128 0.024 10.152 ;
    END
  END rw0_wd_in[146]
  PIN rw0_wd_in[147]
    DIRECTION INPUT ;
    USE SIGNAL ;
    SHAPE ABUTMENT ;
    PORT
      LAYER M4_m ;
      RECT 0 10.176 0.024 10.2 ;
    END
  END rw0_wd_in[147]
  PIN rw0_wd_in[148]
    DIRECTION INPUT ;
    USE SIGNAL ;
    SHAPE ABUTMENT ;
    PORT
      LAYER M4_m ;
      RECT 0 10.224 0.024 10.248 ;
    END
  END rw0_wd_in[148]
  PIN rw0_wd_in[149]
    DIRECTION INPUT ;
    USE SIGNAL ;
    SHAPE ABUTMENT ;
    PORT
      LAYER M4_m ;
      RECT 0 10.272 0.024 10.296 ;
    END
  END rw0_wd_in[149]
  PIN rw0_wd_in[150]
    DIRECTION INPUT ;
    USE SIGNAL ;
    SHAPE ABUTMENT ;
    PORT
      LAYER M4_m ;
      RECT 0 10.32 0.024 10.344 ;
    END
  END rw0_wd_in[150]
  PIN rw0_wd_in[151]
    DIRECTION INPUT ;
    USE SIGNAL ;
    SHAPE ABUTMENT ;
    PORT
      LAYER M4_m ;
      RECT 0 10.368 0.024 10.392 ;
    END
  END rw0_wd_in[151]
  PIN rw0_wd_in[152]
    DIRECTION INPUT ;
    USE SIGNAL ;
    SHAPE ABUTMENT ;
    PORT
      LAYER M4_m ;
      RECT 0 10.416 0.024 10.44 ;
    END
  END rw0_wd_in[152]
  PIN rw0_wd_in[153]
    DIRECTION INPUT ;
    USE SIGNAL ;
    SHAPE ABUTMENT ;
    PORT
      LAYER M4_m ;
      RECT 0 10.464 0.024 10.488 ;
    END
  END rw0_wd_in[153]
  PIN rw0_wd_in[154]
    DIRECTION INPUT ;
    USE SIGNAL ;
    SHAPE ABUTMENT ;
    PORT
      LAYER M4_m ;
      RECT 0 10.512 0.024 10.536 ;
    END
  END rw0_wd_in[154]
  PIN rw0_wd_in[155]
    DIRECTION INPUT ;
    USE SIGNAL ;
    SHAPE ABUTMENT ;
    PORT
      LAYER M4_m ;
      RECT 0 10.56 0.024 10.584 ;
    END
  END rw0_wd_in[155]
  PIN rw0_wd_in[156]
    DIRECTION INPUT ;
    USE SIGNAL ;
    SHAPE ABUTMENT ;
    PORT
      LAYER M4_m ;
      RECT 0 10.608 0.024 10.632 ;
    END
  END rw0_wd_in[156]
  PIN rw0_wd_in[157]
    DIRECTION INPUT ;
    USE SIGNAL ;
    SHAPE ABUTMENT ;
    PORT
      LAYER M4_m ;
      RECT 0 10.656 0.024 10.68 ;
    END
  END rw0_wd_in[157]
  PIN rw0_wd_in[158]
    DIRECTION INPUT ;
    USE SIGNAL ;
    SHAPE ABUTMENT ;
    PORT
      LAYER M4_m ;
      RECT 0 10.704 0.024 10.728 ;
    END
  END rw0_wd_in[158]
  PIN rw0_wd_in[159]
    DIRECTION INPUT ;
    USE SIGNAL ;
    SHAPE ABUTMENT ;
    PORT
      LAYER M4_m ;
      RECT 0 10.752 0.024 10.776 ;
    END
  END rw0_wd_in[159]
  PIN rw0_wd_in[160]
    DIRECTION INPUT ;
    USE SIGNAL ;
    SHAPE ABUTMENT ;
    PORT
      LAYER M4_m ;
      RECT 0 10.8 0.024 10.824 ;
    END
  END rw0_wd_in[160]
  PIN rw0_wd_in[161]
    DIRECTION INPUT ;
    USE SIGNAL ;
    SHAPE ABUTMENT ;
    PORT
      LAYER M4_m ;
      RECT 0 10.848 0.024 10.872 ;
    END
  END rw0_wd_in[161]
  PIN rw0_wd_in[162]
    DIRECTION INPUT ;
    USE SIGNAL ;
    SHAPE ABUTMENT ;
    PORT
      LAYER M4_m ;
      RECT 0 10.896 0.024 10.92 ;
    END
  END rw0_wd_in[162]
  PIN rw0_wd_in[163]
    DIRECTION INPUT ;
    USE SIGNAL ;
    SHAPE ABUTMENT ;
    PORT
      LAYER M4_m ;
      RECT 0 10.944 0.024 10.968 ;
    END
  END rw0_wd_in[163]
  PIN rw0_wd_in[164]
    DIRECTION INPUT ;
    USE SIGNAL ;
    SHAPE ABUTMENT ;
    PORT
      LAYER M4_m ;
      RECT 0 10.992 0.024 11.016 ;
    END
  END rw0_wd_in[164]
  PIN rw0_wd_in[165]
    DIRECTION INPUT ;
    USE SIGNAL ;
    SHAPE ABUTMENT ;
    PORT
      LAYER M4_m ;
      RECT 0 11.04 0.024 11.064 ;
    END
  END rw0_wd_in[165]
  PIN rw0_wd_in[166]
    DIRECTION INPUT ;
    USE SIGNAL ;
    SHAPE ABUTMENT ;
    PORT
      LAYER M4_m ;
      RECT 0 11.088 0.024 11.112 ;
    END
  END rw0_wd_in[166]
  PIN rw0_wd_in[167]
    DIRECTION INPUT ;
    USE SIGNAL ;
    SHAPE ABUTMENT ;
    PORT
      LAYER M4_m ;
      RECT 0 11.136 0.024 11.16 ;
    END
  END rw0_wd_in[167]
  PIN rw0_wd_in[168]
    DIRECTION INPUT ;
    USE SIGNAL ;
    SHAPE ABUTMENT ;
    PORT
      LAYER M4_m ;
      RECT 0 11.184 0.024 11.208 ;
    END
  END rw0_wd_in[168]
  PIN rw0_wd_in[169]
    DIRECTION INPUT ;
    USE SIGNAL ;
    SHAPE ABUTMENT ;
    PORT
      LAYER M4_m ;
      RECT 0 11.232 0.024 11.256 ;
    END
  END rw0_wd_in[169]
  PIN rw0_wd_in[170]
    DIRECTION INPUT ;
    USE SIGNAL ;
    SHAPE ABUTMENT ;
    PORT
      LAYER M4_m ;
      RECT 0 11.28 0.024 11.304 ;
    END
  END rw0_wd_in[170]
  PIN rw0_wd_in[171]
    DIRECTION INPUT ;
    USE SIGNAL ;
    SHAPE ABUTMENT ;
    PORT
      LAYER M4_m ;
      RECT 0 11.328 0.024 11.352 ;
    END
  END rw0_wd_in[171]
  PIN rw0_wd_in[172]
    DIRECTION INPUT ;
    USE SIGNAL ;
    SHAPE ABUTMENT ;
    PORT
      LAYER M4_m ;
      RECT 0 11.376 0.024 11.4 ;
    END
  END rw0_wd_in[172]
  PIN rw0_wd_in[173]
    DIRECTION INPUT ;
    USE SIGNAL ;
    SHAPE ABUTMENT ;
    PORT
      LAYER M4_m ;
      RECT 0 11.424 0.024 11.448 ;
    END
  END rw0_wd_in[173]
  PIN rw0_wd_in[174]
    DIRECTION INPUT ;
    USE SIGNAL ;
    SHAPE ABUTMENT ;
    PORT
      LAYER M4_m ;
      RECT 0 11.472 0.024 11.496 ;
    END
  END rw0_wd_in[174]
  PIN rw0_wd_in[175]
    DIRECTION INPUT ;
    USE SIGNAL ;
    SHAPE ABUTMENT ;
    PORT
      LAYER M4_m ;
      RECT 0 11.52 0.024 11.544 ;
    END
  END rw0_wd_in[175]
  PIN rw0_wd_in[176]
    DIRECTION INPUT ;
    USE SIGNAL ;
    SHAPE ABUTMENT ;
    PORT
      LAYER M4_m ;
      RECT 0 11.568 0.024 11.592 ;
    END
  END rw0_wd_in[176]
  PIN rw0_wd_in[177]
    DIRECTION INPUT ;
    USE SIGNAL ;
    SHAPE ABUTMENT ;
    PORT
      LAYER M4_m ;
      RECT 0 11.616 0.024 11.64 ;
    END
  END rw0_wd_in[177]
  PIN rw0_wd_in[178]
    DIRECTION INPUT ;
    USE SIGNAL ;
    SHAPE ABUTMENT ;
    PORT
      LAYER M4_m ;
      RECT 0 11.664 0.024 11.688 ;
    END
  END rw0_wd_in[178]
  PIN rw0_wd_in[179]
    DIRECTION INPUT ;
    USE SIGNAL ;
    SHAPE ABUTMENT ;
    PORT
      LAYER M4_m ;
      RECT 0 11.712 0.024 11.736 ;
    END
  END rw0_wd_in[179]
  PIN rw0_wd_in[180]
    DIRECTION INPUT ;
    USE SIGNAL ;
    SHAPE ABUTMENT ;
    PORT
      LAYER M4_m ;
      RECT 0 11.76 0.024 11.784 ;
    END
  END rw0_wd_in[180]
  PIN rw0_wd_in[181]
    DIRECTION INPUT ;
    USE SIGNAL ;
    SHAPE ABUTMENT ;
    PORT
      LAYER M4_m ;
      RECT 0 11.808 0.024 11.832 ;
    END
  END rw0_wd_in[181]
  PIN rw0_wd_in[182]
    DIRECTION INPUT ;
    USE SIGNAL ;
    SHAPE ABUTMENT ;
    PORT
      LAYER M4_m ;
      RECT 0 11.856 0.024 11.88 ;
    END
  END rw0_wd_in[182]
  PIN rw0_wd_in[183]
    DIRECTION INPUT ;
    USE SIGNAL ;
    SHAPE ABUTMENT ;
    PORT
      LAYER M4_m ;
      RECT 0 11.904 0.024 11.928 ;
    END
  END rw0_wd_in[183]
  PIN rw0_wd_in[184]
    DIRECTION INPUT ;
    USE SIGNAL ;
    SHAPE ABUTMENT ;
    PORT
      LAYER M4_m ;
      RECT 0 11.952 0.024 11.976 ;
    END
  END rw0_wd_in[184]
  PIN rw0_wd_in[185]
    DIRECTION INPUT ;
    USE SIGNAL ;
    SHAPE ABUTMENT ;
    PORT
      LAYER M4_m ;
      RECT 0 12 0.024 12.024 ;
    END
  END rw0_wd_in[185]
  PIN rw0_wd_in[186]
    DIRECTION INPUT ;
    USE SIGNAL ;
    SHAPE ABUTMENT ;
    PORT
      LAYER M4_m ;
      RECT 0 12.048 0.024 12.072 ;
    END
  END rw0_wd_in[186]
  PIN rw0_wd_in[187]
    DIRECTION INPUT ;
    USE SIGNAL ;
    SHAPE ABUTMENT ;
    PORT
      LAYER M4_m ;
      RECT 0 12.096 0.024 12.12 ;
    END
  END rw0_wd_in[187]
  PIN rw0_wd_in[188]
    DIRECTION INPUT ;
    USE SIGNAL ;
    SHAPE ABUTMENT ;
    PORT
      LAYER M4_m ;
      RECT 0 12.144 0.024 12.168 ;
    END
  END rw0_wd_in[188]
  PIN rw0_wd_in[189]
    DIRECTION INPUT ;
    USE SIGNAL ;
    SHAPE ABUTMENT ;
    PORT
      LAYER M4_m ;
      RECT 0 12.192 0.024 12.216 ;
    END
  END rw0_wd_in[189]
  PIN rw0_wd_in[190]
    DIRECTION INPUT ;
    USE SIGNAL ;
    SHAPE ABUTMENT ;
    PORT
      LAYER M4_m ;
      RECT 0 12.24 0.024 12.264 ;
    END
  END rw0_wd_in[190]
  PIN rw0_wd_in[191]
    DIRECTION INPUT ;
    USE SIGNAL ;
    SHAPE ABUTMENT ;
    PORT
      LAYER M4_m ;
      RECT 0 12.288 0.024 12.312 ;
    END
  END rw0_wd_in[191]
  PIN rw0_wd_in[192]
    DIRECTION INPUT ;
    USE SIGNAL ;
    SHAPE ABUTMENT ;
    PORT
      LAYER M4_m ;
      RECT 0 12.336 0.024 12.36 ;
    END
  END rw0_wd_in[192]
  PIN rw0_wd_in[193]
    DIRECTION INPUT ;
    USE SIGNAL ;
    SHAPE ABUTMENT ;
    PORT
      LAYER M4_m ;
      RECT 0 12.384 0.024 12.408 ;
    END
  END rw0_wd_in[193]
  PIN rw0_wd_in[194]
    DIRECTION INPUT ;
    USE SIGNAL ;
    SHAPE ABUTMENT ;
    PORT
      LAYER M4_m ;
      RECT 0 12.432 0.024 12.456 ;
    END
  END rw0_wd_in[194]
  PIN rw0_wd_in[195]
    DIRECTION INPUT ;
    USE SIGNAL ;
    SHAPE ABUTMENT ;
    PORT
      LAYER M4_m ;
      RECT 0 12.48 0.024 12.504 ;
    END
  END rw0_wd_in[195]
  PIN rw0_wd_in[196]
    DIRECTION INPUT ;
    USE SIGNAL ;
    SHAPE ABUTMENT ;
    PORT
      LAYER M4_m ;
      RECT 0 12.528 0.024 12.552 ;
    END
  END rw0_wd_in[196]
  PIN rw0_wd_in[197]
    DIRECTION INPUT ;
    USE SIGNAL ;
    SHAPE ABUTMENT ;
    PORT
      LAYER M4_m ;
      RECT 0 12.576 0.024 12.6 ;
    END
  END rw0_wd_in[197]
  PIN rw0_wd_in[198]
    DIRECTION INPUT ;
    USE SIGNAL ;
    SHAPE ABUTMENT ;
    PORT
      LAYER M4_m ;
      RECT 0 12.624 0.024 12.648 ;
    END
  END rw0_wd_in[198]
  PIN rw0_wd_in[199]
    DIRECTION INPUT ;
    USE SIGNAL ;
    SHAPE ABUTMENT ;
    PORT
      LAYER M4_m ;
      RECT 0 12.672 0.024 12.696 ;
    END
  END rw0_wd_in[199]
  PIN rw0_wd_in[200]
    DIRECTION INPUT ;
    USE SIGNAL ;
    SHAPE ABUTMENT ;
    PORT
      LAYER M4_m ;
      RECT 0 12.72 0.024 12.744 ;
    END
  END rw0_wd_in[200]
  PIN rw0_wd_in[201]
    DIRECTION INPUT ;
    USE SIGNAL ;
    SHAPE ABUTMENT ;
    PORT
      LAYER M4_m ;
      RECT 0 12.768 0.024 12.792 ;
    END
  END rw0_wd_in[201]
  PIN rw0_wd_in[202]
    DIRECTION INPUT ;
    USE SIGNAL ;
    SHAPE ABUTMENT ;
    PORT
      LAYER M4_m ;
      RECT 0 12.816 0.024 12.84 ;
    END
  END rw0_wd_in[202]
  PIN rw0_wd_in[203]
    DIRECTION INPUT ;
    USE SIGNAL ;
    SHAPE ABUTMENT ;
    PORT
      LAYER M4_m ;
      RECT 0 12.864 0.024 12.888 ;
    END
  END rw0_wd_in[203]
  PIN rw0_wd_in[204]
    DIRECTION INPUT ;
    USE SIGNAL ;
    SHAPE ABUTMENT ;
    PORT
      LAYER M4_m ;
      RECT 0 12.912 0.024 12.936 ;
    END
  END rw0_wd_in[204]
  PIN rw0_wd_in[205]
    DIRECTION INPUT ;
    USE SIGNAL ;
    SHAPE ABUTMENT ;
    PORT
      LAYER M4_m ;
      RECT 0 12.96 0.024 12.984 ;
    END
  END rw0_wd_in[205]
  PIN rw0_wd_in[206]
    DIRECTION INPUT ;
    USE SIGNAL ;
    SHAPE ABUTMENT ;
    PORT
      LAYER M4_m ;
      RECT 0 13.008 0.024 13.032 ;
    END
  END rw0_wd_in[206]
  PIN rw0_wd_in[207]
    DIRECTION INPUT ;
    USE SIGNAL ;
    SHAPE ABUTMENT ;
    PORT
      LAYER M4_m ;
      RECT 0 13.056 0.024 13.08 ;
    END
  END rw0_wd_in[207]
  PIN rw0_wd_in[208]
    DIRECTION INPUT ;
    USE SIGNAL ;
    SHAPE ABUTMENT ;
    PORT
      LAYER M4_m ;
      RECT 0 13.104 0.024 13.128 ;
    END
  END rw0_wd_in[208]
  PIN rw0_wd_in[209]
    DIRECTION INPUT ;
    USE SIGNAL ;
    SHAPE ABUTMENT ;
    PORT
      LAYER M4_m ;
      RECT 0 13.152 0.024 13.176 ;
    END
  END rw0_wd_in[209]
  PIN rw0_wd_in[210]
    DIRECTION INPUT ;
    USE SIGNAL ;
    SHAPE ABUTMENT ;
    PORT
      LAYER M4_m ;
      RECT 0 13.2 0.024 13.224 ;
    END
  END rw0_wd_in[210]
  PIN rw0_wd_in[211]
    DIRECTION INPUT ;
    USE SIGNAL ;
    SHAPE ABUTMENT ;
    PORT
      LAYER M4_m ;
      RECT 0 13.248 0.024 13.272 ;
    END
  END rw0_wd_in[211]
  PIN rw0_wd_in[212]
    DIRECTION INPUT ;
    USE SIGNAL ;
    SHAPE ABUTMENT ;
    PORT
      LAYER M4_m ;
      RECT 0 13.296 0.024 13.32 ;
    END
  END rw0_wd_in[212]
  PIN rw0_wd_in[213]
    DIRECTION INPUT ;
    USE SIGNAL ;
    SHAPE ABUTMENT ;
    PORT
      LAYER M4_m ;
      RECT 0 13.344 0.024 13.368 ;
    END
  END rw0_wd_in[213]
  PIN rw0_wd_in[214]
    DIRECTION INPUT ;
    USE SIGNAL ;
    SHAPE ABUTMENT ;
    PORT
      LAYER M4_m ;
      RECT 0 13.392 0.024 13.416 ;
    END
  END rw0_wd_in[214]
  PIN rw0_wd_in[215]
    DIRECTION INPUT ;
    USE SIGNAL ;
    SHAPE ABUTMENT ;
    PORT
      LAYER M4_m ;
      RECT 0 13.44 0.024 13.464 ;
    END
  END rw0_wd_in[215]
  PIN rw0_wd_in[216]
    DIRECTION INPUT ;
    USE SIGNAL ;
    SHAPE ABUTMENT ;
    PORT
      LAYER M4_m ;
      RECT 0 13.488 0.024 13.512 ;
    END
  END rw0_wd_in[216]
  PIN rw0_wd_in[217]
    DIRECTION INPUT ;
    USE SIGNAL ;
    SHAPE ABUTMENT ;
    PORT
      LAYER M4_m ;
      RECT 0 13.536 0.024 13.56 ;
    END
  END rw0_wd_in[217]
  PIN rw0_wd_in[218]
    DIRECTION INPUT ;
    USE SIGNAL ;
    SHAPE ABUTMENT ;
    PORT
      LAYER M4_m ;
      RECT 0 13.584 0.024 13.608 ;
    END
  END rw0_wd_in[218]
  PIN rw0_wd_in[219]
    DIRECTION INPUT ;
    USE SIGNAL ;
    SHAPE ABUTMENT ;
    PORT
      LAYER M4_m ;
      RECT 0 13.632 0.024 13.656 ;
    END
  END rw0_wd_in[219]
  PIN rw0_wd_in[220]
    DIRECTION INPUT ;
    USE SIGNAL ;
    SHAPE ABUTMENT ;
    PORT
      LAYER M4_m ;
      RECT 0 13.68 0.024 13.704 ;
    END
  END rw0_wd_in[220]
  PIN rw0_wd_in[221]
    DIRECTION INPUT ;
    USE SIGNAL ;
    SHAPE ABUTMENT ;
    PORT
      LAYER M4_m ;
      RECT 0 13.728 0.024 13.752 ;
    END
  END rw0_wd_in[221]
  PIN rw0_wd_in[222]
    DIRECTION INPUT ;
    USE SIGNAL ;
    SHAPE ABUTMENT ;
    PORT
      LAYER M4_m ;
      RECT 0 13.776 0.024 13.8 ;
    END
  END rw0_wd_in[222]
  PIN rw0_wd_in[223]
    DIRECTION INPUT ;
    USE SIGNAL ;
    SHAPE ABUTMENT ;
    PORT
      LAYER M4_m ;
      RECT 0 13.824 0.024 13.848 ;
    END
  END rw0_wd_in[223]
  PIN rw0_wd_in[224]
    DIRECTION INPUT ;
    USE SIGNAL ;
    SHAPE ABUTMENT ;
    PORT
      LAYER M4_m ;
      RECT 0 13.872 0.024 13.896 ;
    END
  END rw0_wd_in[224]
  PIN rw0_wd_in[225]
    DIRECTION INPUT ;
    USE SIGNAL ;
    SHAPE ABUTMENT ;
    PORT
      LAYER M4_m ;
      RECT 0 13.92 0.024 13.944 ;
    END
  END rw0_wd_in[225]
  PIN rw0_wd_in[226]
    DIRECTION INPUT ;
    USE SIGNAL ;
    SHAPE ABUTMENT ;
    PORT
      LAYER M4_m ;
      RECT 0 13.968 0.024 13.992 ;
    END
  END rw0_wd_in[226]
  PIN rw0_wd_in[227]
    DIRECTION INPUT ;
    USE SIGNAL ;
    SHAPE ABUTMENT ;
    PORT
      LAYER M4_m ;
      RECT 0 14.016 0.024 14.04 ;
    END
  END rw0_wd_in[227]
  PIN rw0_wd_in[228]
    DIRECTION INPUT ;
    USE SIGNAL ;
    SHAPE ABUTMENT ;
    PORT
      LAYER M4_m ;
      RECT 0 14.064 0.024 14.088 ;
    END
  END rw0_wd_in[228]
  PIN rw0_wd_in[229]
    DIRECTION INPUT ;
    USE SIGNAL ;
    SHAPE ABUTMENT ;
    PORT
      LAYER M4_m ;
      RECT 0 14.112 0.024 14.136 ;
    END
  END rw0_wd_in[229]
  PIN rw0_wd_in[230]
    DIRECTION INPUT ;
    USE SIGNAL ;
    SHAPE ABUTMENT ;
    PORT
      LAYER M4_m ;
      RECT 0 14.16 0.024 14.184 ;
    END
  END rw0_wd_in[230]
  PIN rw0_wd_in[231]
    DIRECTION INPUT ;
    USE SIGNAL ;
    SHAPE ABUTMENT ;
    PORT
      LAYER M4_m ;
      RECT 0 14.208 0.024 14.232 ;
    END
  END rw0_wd_in[231]
  PIN rw0_wd_in[232]
    DIRECTION INPUT ;
    USE SIGNAL ;
    SHAPE ABUTMENT ;
    PORT
      LAYER M4_m ;
      RECT 0 14.256 0.024 14.28 ;
    END
  END rw0_wd_in[232]
  PIN rw0_wd_in[233]
    DIRECTION INPUT ;
    USE SIGNAL ;
    SHAPE ABUTMENT ;
    PORT
      LAYER M4_m ;
      RECT 0 14.304 0.024 14.328 ;
    END
  END rw0_wd_in[233]
  PIN rw0_wd_in[234]
    DIRECTION INPUT ;
    USE SIGNAL ;
    SHAPE ABUTMENT ;
    PORT
      LAYER M4_m ;
      RECT 0 14.352 0.024 14.376 ;
    END
  END rw0_wd_in[234]
  PIN rw0_wd_in[235]
    DIRECTION INPUT ;
    USE SIGNAL ;
    SHAPE ABUTMENT ;
    PORT
      LAYER M4_m ;
      RECT 0 14.4 0.024 14.424 ;
    END
  END rw0_wd_in[235]
  PIN rw0_wd_in[236]
    DIRECTION INPUT ;
    USE SIGNAL ;
    SHAPE ABUTMENT ;
    PORT
      LAYER M4_m ;
      RECT 0 14.448 0.024 14.472 ;
    END
  END rw0_wd_in[236]
  PIN rw0_wd_in[237]
    DIRECTION INPUT ;
    USE SIGNAL ;
    SHAPE ABUTMENT ;
    PORT
      LAYER M4_m ;
      RECT 0 14.496 0.024 14.52 ;
    END
  END rw0_wd_in[237]
  PIN rw0_wd_in[238]
    DIRECTION INPUT ;
    USE SIGNAL ;
    SHAPE ABUTMENT ;
    PORT
      LAYER M4_m ;
      RECT 0 14.544 0.024 14.568 ;
    END
  END rw0_wd_in[238]
  PIN rw0_wd_in[239]
    DIRECTION INPUT ;
    USE SIGNAL ;
    SHAPE ABUTMENT ;
    PORT
      LAYER M4_m ;
      RECT 0 14.592 0.024 14.616 ;
    END
  END rw0_wd_in[239]
  PIN rw0_wd_in[240]
    DIRECTION INPUT ;
    USE SIGNAL ;
    SHAPE ABUTMENT ;
    PORT
      LAYER M4_m ;
      RECT 0 14.64 0.024 14.664 ;
    END
  END rw0_wd_in[240]
  PIN rw0_wd_in[241]
    DIRECTION INPUT ;
    USE SIGNAL ;
    SHAPE ABUTMENT ;
    PORT
      LAYER M4_m ;
      RECT 0 14.688 0.024 14.712 ;
    END
  END rw0_wd_in[241]
  PIN rw0_wd_in[242]
    DIRECTION INPUT ;
    USE SIGNAL ;
    SHAPE ABUTMENT ;
    PORT
      LAYER M4_m ;
      RECT 0 14.736 0.024 14.76 ;
    END
  END rw0_wd_in[242]
  PIN rw0_wd_in[243]
    DIRECTION INPUT ;
    USE SIGNAL ;
    SHAPE ABUTMENT ;
    PORT
      LAYER M4_m ;
      RECT 0 14.784 0.024 14.808 ;
    END
  END rw0_wd_in[243]
  PIN rw0_wd_in[244]
    DIRECTION INPUT ;
    USE SIGNAL ;
    SHAPE ABUTMENT ;
    PORT
      LAYER M4_m ;
      RECT 0 14.832 0.024 14.856 ;
    END
  END rw0_wd_in[244]
  PIN rw0_wd_in[245]
    DIRECTION INPUT ;
    USE SIGNAL ;
    SHAPE ABUTMENT ;
    PORT
      LAYER M4_m ;
      RECT 0 14.88 0.024 14.904 ;
    END
  END rw0_wd_in[245]
  PIN rw0_wd_in[246]
    DIRECTION INPUT ;
    USE SIGNAL ;
    SHAPE ABUTMENT ;
    PORT
      LAYER M4_m ;
      RECT 0 14.928 0.024 14.952 ;
    END
  END rw0_wd_in[246]
  PIN rw0_wd_in[247]
    DIRECTION INPUT ;
    USE SIGNAL ;
    SHAPE ABUTMENT ;
    PORT
      LAYER M4_m ;
      RECT 0 14.976 0.024 15 ;
    END
  END rw0_wd_in[247]
  PIN rw0_wd_in[248]
    DIRECTION INPUT ;
    USE SIGNAL ;
    SHAPE ABUTMENT ;
    PORT
      LAYER M4_m ;
      RECT 0 15.024 0.024 15.048 ;
    END
  END rw0_wd_in[248]
  PIN rw0_wd_in[249]
    DIRECTION INPUT ;
    USE SIGNAL ;
    SHAPE ABUTMENT ;
    PORT
      LAYER M4_m ;
      RECT 0 15.072 0.024 15.096 ;
    END
  END rw0_wd_in[249]
  PIN rw0_wd_in[250]
    DIRECTION INPUT ;
    USE SIGNAL ;
    SHAPE ABUTMENT ;
    PORT
      LAYER M4_m ;
      RECT 0 15.12 0.024 15.144 ;
    END
  END rw0_wd_in[250]
  PIN rw0_wd_in[251]
    DIRECTION INPUT ;
    USE SIGNAL ;
    SHAPE ABUTMENT ;
    PORT
      LAYER M4_m ;
      RECT 0 15.168 0.024 15.192 ;
    END
  END rw0_wd_in[251]
  PIN rw0_wd_in[252]
    DIRECTION INPUT ;
    USE SIGNAL ;
    SHAPE ABUTMENT ;
    PORT
      LAYER M4_m ;
      RECT 0 15.216 0.024 15.24 ;
    END
  END rw0_wd_in[252]
  PIN rw0_wd_in[253]
    DIRECTION INPUT ;
    USE SIGNAL ;
    SHAPE ABUTMENT ;
    PORT
      LAYER M4_m ;
      RECT 0 15.264 0.024 15.288 ;
    END
  END rw0_wd_in[253]
  PIN rw0_wd_in[254]
    DIRECTION INPUT ;
    USE SIGNAL ;
    SHAPE ABUTMENT ;
    PORT
      LAYER M4_m ;
      RECT 0 15.312 0.024 15.336 ;
    END
  END rw0_wd_in[254]
  PIN rw0_wd_in[255]
    DIRECTION INPUT ;
    USE SIGNAL ;
    SHAPE ABUTMENT ;
    PORT
      LAYER M4_m ;
      RECT 0 15.36 0.024 15.384 ;
    END
  END rw0_wd_in[255]
  PIN rw0_wd_in[256]
    DIRECTION INPUT ;
    USE SIGNAL ;
    SHAPE ABUTMENT ;
    PORT
      LAYER M4_m ;
      RECT 0 15.408 0.024 15.432 ;
    END
  END rw0_wd_in[256]
  PIN rw0_wd_in[257]
    DIRECTION INPUT ;
    USE SIGNAL ;
    SHAPE ABUTMENT ;
    PORT
      LAYER M4_m ;
      RECT 0 15.456 0.024 15.48 ;
    END
  END rw0_wd_in[257]
  PIN rw0_wd_in[258]
    DIRECTION INPUT ;
    USE SIGNAL ;
    SHAPE ABUTMENT ;
    PORT
      LAYER M4_m ;
      RECT 0 15.504 0.024 15.528 ;
    END
  END rw0_wd_in[258]
  PIN rw0_wd_in[259]
    DIRECTION INPUT ;
    USE SIGNAL ;
    SHAPE ABUTMENT ;
    PORT
      LAYER M4_m ;
      RECT 0 15.552 0.024 15.576 ;
    END
  END rw0_wd_in[259]
  PIN rw0_wd_in[260]
    DIRECTION INPUT ;
    USE SIGNAL ;
    SHAPE ABUTMENT ;
    PORT
      LAYER M4_m ;
      RECT 0 15.6 0.024 15.624 ;
    END
  END rw0_wd_in[260]
  PIN rw0_wd_in[261]
    DIRECTION INPUT ;
    USE SIGNAL ;
    SHAPE ABUTMENT ;
    PORT
      LAYER M4_m ;
      RECT 0 15.648 0.024 15.672 ;
    END
  END rw0_wd_in[261]
  PIN rw0_wd_in[262]
    DIRECTION INPUT ;
    USE SIGNAL ;
    SHAPE ABUTMENT ;
    PORT
      LAYER M4_m ;
      RECT 0 15.696 0.024 15.72 ;
    END
  END rw0_wd_in[262]
  PIN rw0_wd_in[263]
    DIRECTION INPUT ;
    USE SIGNAL ;
    SHAPE ABUTMENT ;
    PORT
      LAYER M4_m ;
      RECT 0 15.744 0.024 15.768 ;
    END
  END rw0_wd_in[263]
  PIN rw0_wd_in[264]
    DIRECTION INPUT ;
    USE SIGNAL ;
    SHAPE ABUTMENT ;
    PORT
      LAYER M4_m ;
      RECT 0 15.792 0.024 15.816 ;
    END
  END rw0_wd_in[264]
  PIN rw0_wd_in[265]
    DIRECTION INPUT ;
    USE SIGNAL ;
    SHAPE ABUTMENT ;
    PORT
      LAYER M4_m ;
      RECT 0 15.84 0.024 15.864 ;
    END
  END rw0_wd_in[265]
  PIN rw0_wd_in[266]
    DIRECTION INPUT ;
    USE SIGNAL ;
    SHAPE ABUTMENT ;
    PORT
      LAYER M4_m ;
      RECT 0 15.888 0.024 15.912 ;
    END
  END rw0_wd_in[266]
  PIN rw0_wd_in[267]
    DIRECTION INPUT ;
    USE SIGNAL ;
    SHAPE ABUTMENT ;
    PORT
      LAYER M4_m ;
      RECT 0 15.936 0.024 15.96 ;
    END
  END rw0_wd_in[267]
  PIN rw0_wd_in[268]
    DIRECTION INPUT ;
    USE SIGNAL ;
    SHAPE ABUTMENT ;
    PORT
      LAYER M4_m ;
      RECT 0 15.984 0.024 16.008 ;
    END
  END rw0_wd_in[268]
  PIN rw0_wd_in[269]
    DIRECTION INPUT ;
    USE SIGNAL ;
    SHAPE ABUTMENT ;
    PORT
      LAYER M4_m ;
      RECT 0 16.032 0.024 16.056 ;
    END
  END rw0_wd_in[269]
  PIN rw0_wd_in[270]
    DIRECTION INPUT ;
    USE SIGNAL ;
    SHAPE ABUTMENT ;
    PORT
      LAYER M4_m ;
      RECT 0 16.08 0.024 16.104 ;
    END
  END rw0_wd_in[270]
  PIN rw0_wd_in[271]
    DIRECTION INPUT ;
    USE SIGNAL ;
    SHAPE ABUTMENT ;
    PORT
      LAYER M4_m ;
      RECT 0 16.128 0.024 16.152 ;
    END
  END rw0_wd_in[271]
  PIN rw0_wd_in[272]
    DIRECTION INPUT ;
    USE SIGNAL ;
    SHAPE ABUTMENT ;
    PORT
      LAYER M4_m ;
      RECT 0 16.176 0.024 16.2 ;
    END
  END rw0_wd_in[272]
  PIN rw0_wd_in[273]
    DIRECTION INPUT ;
    USE SIGNAL ;
    SHAPE ABUTMENT ;
    PORT
      LAYER M4_m ;
      RECT 0 16.224 0.024 16.248 ;
    END
  END rw0_wd_in[273]
  PIN rw0_wd_in[274]
    DIRECTION INPUT ;
    USE SIGNAL ;
    SHAPE ABUTMENT ;
    PORT
      LAYER M4_m ;
      RECT 0 16.272 0.024 16.296 ;
    END
  END rw0_wd_in[274]
  PIN rw0_wd_in[275]
    DIRECTION INPUT ;
    USE SIGNAL ;
    SHAPE ABUTMENT ;
    PORT
      LAYER M4_m ;
      RECT 0 16.32 0.024 16.344 ;
    END
  END rw0_wd_in[275]
  PIN rw0_wd_in[276]
    DIRECTION INPUT ;
    USE SIGNAL ;
    SHAPE ABUTMENT ;
    PORT
      LAYER M4_m ;
      RECT 0 16.368 0.024 16.392 ;
    END
  END rw0_wd_in[276]
  PIN rw0_wd_in[277]
    DIRECTION INPUT ;
    USE SIGNAL ;
    SHAPE ABUTMENT ;
    PORT
      LAYER M4_m ;
      RECT 0 16.416 0.024 16.44 ;
    END
  END rw0_wd_in[277]
  PIN rw0_wd_in[278]
    DIRECTION INPUT ;
    USE SIGNAL ;
    SHAPE ABUTMENT ;
    PORT
      LAYER M4_m ;
      RECT 0 16.464 0.024 16.488 ;
    END
  END rw0_wd_in[278]
  PIN rw0_wd_in[279]
    DIRECTION INPUT ;
    USE SIGNAL ;
    SHAPE ABUTMENT ;
    PORT
      LAYER M4_m ;
      RECT 0 16.512 0.024 16.536 ;
    END
  END rw0_wd_in[279]
  PIN rw0_wd_in[280]
    DIRECTION INPUT ;
    USE SIGNAL ;
    SHAPE ABUTMENT ;
    PORT
      LAYER M4_m ;
      RECT 0 16.56 0.024 16.584 ;
    END
  END rw0_wd_in[280]
  PIN rw0_wd_in[281]
    DIRECTION INPUT ;
    USE SIGNAL ;
    SHAPE ABUTMENT ;
    PORT
      LAYER M4_m ;
      RECT 0 16.608 0.024 16.632 ;
    END
  END rw0_wd_in[281]
  PIN rw0_wd_in[282]
    DIRECTION INPUT ;
    USE SIGNAL ;
    SHAPE ABUTMENT ;
    PORT
      LAYER M4_m ;
      RECT 0 16.656 0.024 16.68 ;
    END
  END rw0_wd_in[282]
  PIN rw0_wd_in[283]
    DIRECTION INPUT ;
    USE SIGNAL ;
    SHAPE ABUTMENT ;
    PORT
      LAYER M4_m ;
      RECT 0 16.704 0.024 16.728 ;
    END
  END rw0_wd_in[283]
  PIN rw0_wd_in[284]
    DIRECTION INPUT ;
    USE SIGNAL ;
    SHAPE ABUTMENT ;
    PORT
      LAYER M4_m ;
      RECT 0 16.752 0.024 16.776 ;
    END
  END rw0_wd_in[284]
  PIN rw0_wd_in[285]
    DIRECTION INPUT ;
    USE SIGNAL ;
    SHAPE ABUTMENT ;
    PORT
      LAYER M4_m ;
      RECT 0 16.8 0.024 16.824 ;
    END
  END rw0_wd_in[285]
  PIN rw0_wd_in[286]
    DIRECTION INPUT ;
    USE SIGNAL ;
    SHAPE ABUTMENT ;
    PORT
      LAYER M4_m ;
      RECT 0 16.848 0.024 16.872 ;
    END
  END rw0_wd_in[286]
  PIN rw0_wd_in[287]
    DIRECTION INPUT ;
    USE SIGNAL ;
    SHAPE ABUTMENT ;
    PORT
      LAYER M4_m ;
      RECT 0 16.896 0.024 16.92 ;
    END
  END rw0_wd_in[287]
  PIN rw0_wd_in[288]
    DIRECTION INPUT ;
    USE SIGNAL ;
    SHAPE ABUTMENT ;
    PORT
      LAYER M4_m ;
      RECT 0 16.944 0.024 16.968 ;
    END
  END rw0_wd_in[288]
  PIN rw0_wd_in[289]
    DIRECTION INPUT ;
    USE SIGNAL ;
    SHAPE ABUTMENT ;
    PORT
      LAYER M4_m ;
      RECT 0 16.992 0.024 17.016 ;
    END
  END rw0_wd_in[289]
  PIN rw0_wd_in[290]
    DIRECTION INPUT ;
    USE SIGNAL ;
    SHAPE ABUTMENT ;
    PORT
      LAYER M4_m ;
      RECT 0 17.04 0.024 17.064 ;
    END
  END rw0_wd_in[290]
  PIN rw0_wd_in[291]
    DIRECTION INPUT ;
    USE SIGNAL ;
    SHAPE ABUTMENT ;
    PORT
      LAYER M4_m ;
      RECT 0 17.088 0.024 17.112 ;
    END
  END rw0_wd_in[291]
  PIN rw0_wd_in[292]
    DIRECTION INPUT ;
    USE SIGNAL ;
    SHAPE ABUTMENT ;
    PORT
      LAYER M4_m ;
      RECT 0 17.136 0.024 17.16 ;
    END
  END rw0_wd_in[292]
  PIN rw0_wd_in[293]
    DIRECTION INPUT ;
    USE SIGNAL ;
    SHAPE ABUTMENT ;
    PORT
      LAYER M4_m ;
      RECT 0 17.184 0.024 17.208 ;
    END
  END rw0_wd_in[293]
  PIN rw0_wd_in[294]
    DIRECTION INPUT ;
    USE SIGNAL ;
    SHAPE ABUTMENT ;
    PORT
      LAYER M4_m ;
      RECT 0 17.232 0.024 17.256 ;
    END
  END rw0_wd_in[294]
  PIN rw0_wd_in[295]
    DIRECTION INPUT ;
    USE SIGNAL ;
    SHAPE ABUTMENT ;
    PORT
      LAYER M4_m ;
      RECT 0 17.28 0.024 17.304 ;
    END
  END rw0_wd_in[295]
  PIN rw0_wd_in[296]
    DIRECTION INPUT ;
    USE SIGNAL ;
    SHAPE ABUTMENT ;
    PORT
      LAYER M4_m ;
      RECT 0 17.328 0.024 17.352 ;
    END
  END rw0_wd_in[296]
  PIN rw0_wd_in[297]
    DIRECTION INPUT ;
    USE SIGNAL ;
    SHAPE ABUTMENT ;
    PORT
      LAYER M4_m ;
      RECT 0 17.376 0.024 17.4 ;
    END
  END rw0_wd_in[297]
  PIN rw0_wd_in[298]
    DIRECTION INPUT ;
    USE SIGNAL ;
    SHAPE ABUTMENT ;
    PORT
      LAYER M4_m ;
      RECT 0 17.424 0.024 17.448 ;
    END
  END rw0_wd_in[298]
  PIN rw0_wd_in[299]
    DIRECTION INPUT ;
    USE SIGNAL ;
    SHAPE ABUTMENT ;
    PORT
      LAYER M4_m ;
      RECT 0 17.472 0.024 17.496 ;
    END
  END rw0_wd_in[299]
  PIN rw0_wd_in[300]
    DIRECTION INPUT ;
    USE SIGNAL ;
    SHAPE ABUTMENT ;
    PORT
      LAYER M4_m ;
      RECT 0 17.52 0.024 17.544 ;
    END
  END rw0_wd_in[300]
  PIN rw0_wd_in[301]
    DIRECTION INPUT ;
    USE SIGNAL ;
    SHAPE ABUTMENT ;
    PORT
      LAYER M4_m ;
      RECT 0 17.568 0.024 17.592 ;
    END
  END rw0_wd_in[301]
  PIN rw0_wd_in[302]
    DIRECTION INPUT ;
    USE SIGNAL ;
    SHAPE ABUTMENT ;
    PORT
      LAYER M4_m ;
      RECT 0 17.616 0.024 17.64 ;
    END
  END rw0_wd_in[302]
  PIN rw0_wd_in[303]
    DIRECTION INPUT ;
    USE SIGNAL ;
    SHAPE ABUTMENT ;
    PORT
      LAYER M4_m ;
      RECT 0 17.664 0.024 17.688 ;
    END
  END rw0_wd_in[303]
  PIN rw0_wd_in[304]
    DIRECTION INPUT ;
    USE SIGNAL ;
    SHAPE ABUTMENT ;
    PORT
      LAYER M4_m ;
      RECT 0 17.712 0.024 17.736 ;
    END
  END rw0_wd_in[304]
  PIN rw0_wd_in[305]
    DIRECTION INPUT ;
    USE SIGNAL ;
    SHAPE ABUTMENT ;
    PORT
      LAYER M4_m ;
      RECT 0 17.76 0.024 17.784 ;
    END
  END rw0_wd_in[305]
  PIN rw0_wd_in[306]
    DIRECTION INPUT ;
    USE SIGNAL ;
    SHAPE ABUTMENT ;
    PORT
      LAYER M4_m ;
      RECT 0 17.808 0.024 17.832 ;
    END
  END rw0_wd_in[306]
  PIN rw0_wd_in[307]
    DIRECTION INPUT ;
    USE SIGNAL ;
    SHAPE ABUTMENT ;
    PORT
      LAYER M4_m ;
      RECT 0 17.856 0.024 17.88 ;
    END
  END rw0_wd_in[307]
  PIN rw0_wd_in[308]
    DIRECTION INPUT ;
    USE SIGNAL ;
    SHAPE ABUTMENT ;
    PORT
      LAYER M4_m ;
      RECT 0 17.904 0.024 17.928 ;
    END
  END rw0_wd_in[308]
  PIN rw0_wd_in[309]
    DIRECTION INPUT ;
    USE SIGNAL ;
    SHAPE ABUTMENT ;
    PORT
      LAYER M4_m ;
      RECT 0 17.952 0.024 17.976 ;
    END
  END rw0_wd_in[309]
  PIN rw0_wd_in[310]
    DIRECTION INPUT ;
    USE SIGNAL ;
    SHAPE ABUTMENT ;
    PORT
      LAYER M4_m ;
      RECT 0 18 0.024 18.024 ;
    END
  END rw0_wd_in[310]
  PIN rw0_wd_in[311]
    DIRECTION INPUT ;
    USE SIGNAL ;
    SHAPE ABUTMENT ;
    PORT
      LAYER M4_m ;
      RECT 0 18.048 0.024 18.072 ;
    END
  END rw0_wd_in[311]
  PIN rw0_wd_in[312]
    DIRECTION INPUT ;
    USE SIGNAL ;
    SHAPE ABUTMENT ;
    PORT
      LAYER M4_m ;
      RECT 0 18.096 0.024 18.12 ;
    END
  END rw0_wd_in[312]
  PIN rw0_wd_in[313]
    DIRECTION INPUT ;
    USE SIGNAL ;
    SHAPE ABUTMENT ;
    PORT
      LAYER M4_m ;
      RECT 0 18.144 0.024 18.168 ;
    END
  END rw0_wd_in[313]
  PIN rw0_wd_in[314]
    DIRECTION INPUT ;
    USE SIGNAL ;
    SHAPE ABUTMENT ;
    PORT
      LAYER M4_m ;
      RECT 0 18.192 0.024 18.216 ;
    END
  END rw0_wd_in[314]
  PIN rw0_wd_in[315]
    DIRECTION INPUT ;
    USE SIGNAL ;
    SHAPE ABUTMENT ;
    PORT
      LAYER M4_m ;
      RECT 0 18.24 0.024 18.264 ;
    END
  END rw0_wd_in[315]
  PIN rw0_wd_in[316]
    DIRECTION INPUT ;
    USE SIGNAL ;
    SHAPE ABUTMENT ;
    PORT
      LAYER M4_m ;
      RECT 0 18.288 0.024 18.312 ;
    END
  END rw0_wd_in[316]
  PIN rw0_wd_in[317]
    DIRECTION INPUT ;
    USE SIGNAL ;
    SHAPE ABUTMENT ;
    PORT
      LAYER M4_m ;
      RECT 0 18.336 0.024 18.36 ;
    END
  END rw0_wd_in[317]
  PIN rw0_wd_in[318]
    DIRECTION INPUT ;
    USE SIGNAL ;
    SHAPE ABUTMENT ;
    PORT
      LAYER M4_m ;
      RECT 0 18.384 0.024 18.408 ;
    END
  END rw0_wd_in[318]
  PIN rw0_wd_in[319]
    DIRECTION INPUT ;
    USE SIGNAL ;
    SHAPE ABUTMENT ;
    PORT
      LAYER M4_m ;
      RECT 0 18.432 0.024 18.456 ;
    END
  END rw0_wd_in[319]
  PIN rw0_wd_in[320]
    DIRECTION INPUT ;
    USE SIGNAL ;
    SHAPE ABUTMENT ;
    PORT
      LAYER M4_m ;
      RECT 0 18.48 0.024 18.504 ;
    END
  END rw0_wd_in[320]
  PIN rw0_wd_in[321]
    DIRECTION INPUT ;
    USE SIGNAL ;
    SHAPE ABUTMENT ;
    PORT
      LAYER M4_m ;
      RECT 0 18.528 0.024 18.552 ;
    END
  END rw0_wd_in[321]
  PIN rw0_wd_in[322]
    DIRECTION INPUT ;
    USE SIGNAL ;
    SHAPE ABUTMENT ;
    PORT
      LAYER M4_m ;
      RECT 0 18.576 0.024 18.6 ;
    END
  END rw0_wd_in[322]
  PIN rw0_wd_in[323]
    DIRECTION INPUT ;
    USE SIGNAL ;
    SHAPE ABUTMENT ;
    PORT
      LAYER M4_m ;
      RECT 0 18.624 0.024 18.648 ;
    END
  END rw0_wd_in[323]
  PIN rw0_wd_in[324]
    DIRECTION INPUT ;
    USE SIGNAL ;
    SHAPE ABUTMENT ;
    PORT
      LAYER M4_m ;
      RECT 0 18.672 0.024 18.696 ;
    END
  END rw0_wd_in[324]
  PIN rw0_wd_in[325]
    DIRECTION INPUT ;
    USE SIGNAL ;
    SHAPE ABUTMENT ;
    PORT
      LAYER M4_m ;
      RECT 0 18.72 0.024 18.744 ;
    END
  END rw0_wd_in[325]
  PIN rw0_wd_in[326]
    DIRECTION INPUT ;
    USE SIGNAL ;
    SHAPE ABUTMENT ;
    PORT
      LAYER M4_m ;
      RECT 0 18.768 0.024 18.792 ;
    END
  END rw0_wd_in[326]
  PIN rw0_wd_in[327]
    DIRECTION INPUT ;
    USE SIGNAL ;
    SHAPE ABUTMENT ;
    PORT
      LAYER M4_m ;
      RECT 0 18.816 0.024 18.84 ;
    END
  END rw0_wd_in[327]
  PIN rw0_wd_in[328]
    DIRECTION INPUT ;
    USE SIGNAL ;
    SHAPE ABUTMENT ;
    PORT
      LAYER M4_m ;
      RECT 0 18.864 0.024 18.888 ;
    END
  END rw0_wd_in[328]
  PIN rw0_wd_in[329]
    DIRECTION INPUT ;
    USE SIGNAL ;
    SHAPE ABUTMENT ;
    PORT
      LAYER M4_m ;
      RECT 0 18.912 0.024 18.936 ;
    END
  END rw0_wd_in[329]
  PIN rw0_wd_in[330]
    DIRECTION INPUT ;
    USE SIGNAL ;
    SHAPE ABUTMENT ;
    PORT
      LAYER M4_m ;
      RECT 0 18.96 0.024 18.984 ;
    END
  END rw0_wd_in[330]
  PIN rw0_wd_in[331]
    DIRECTION INPUT ;
    USE SIGNAL ;
    SHAPE ABUTMENT ;
    PORT
      LAYER M4_m ;
      RECT 0 19.008 0.024 19.032 ;
    END
  END rw0_wd_in[331]
  PIN rw0_wd_in[332]
    DIRECTION INPUT ;
    USE SIGNAL ;
    SHAPE ABUTMENT ;
    PORT
      LAYER M4_m ;
      RECT 0 19.056 0.024 19.08 ;
    END
  END rw0_wd_in[332]
  PIN rw0_wd_in[333]
    DIRECTION INPUT ;
    USE SIGNAL ;
    SHAPE ABUTMENT ;
    PORT
      LAYER M4_m ;
      RECT 0 19.104 0.024 19.128 ;
    END
  END rw0_wd_in[333]
  PIN rw0_wd_in[334]
    DIRECTION INPUT ;
    USE SIGNAL ;
    SHAPE ABUTMENT ;
    PORT
      LAYER M4_m ;
      RECT 0 19.152 0.024 19.176 ;
    END
  END rw0_wd_in[334]
  PIN rw0_wd_in[335]
    DIRECTION INPUT ;
    USE SIGNAL ;
    SHAPE ABUTMENT ;
    PORT
      LAYER M4_m ;
      RECT 0 19.2 0.024 19.224 ;
    END
  END rw0_wd_in[335]
  PIN rw0_wd_in[336]
    DIRECTION INPUT ;
    USE SIGNAL ;
    SHAPE ABUTMENT ;
    PORT
      LAYER M4_m ;
      RECT 0 19.248 0.024 19.272 ;
    END
  END rw0_wd_in[336]
  PIN rw0_wd_in[337]
    DIRECTION INPUT ;
    USE SIGNAL ;
    SHAPE ABUTMENT ;
    PORT
      LAYER M4_m ;
      RECT 0 19.296 0.024 19.32 ;
    END
  END rw0_wd_in[337]
  PIN rw0_wd_in[338]
    DIRECTION INPUT ;
    USE SIGNAL ;
    SHAPE ABUTMENT ;
    PORT
      LAYER M4_m ;
      RECT 0 19.344 0.024 19.368 ;
    END
  END rw0_wd_in[338]
  PIN rw0_wd_in[339]
    DIRECTION INPUT ;
    USE SIGNAL ;
    SHAPE ABUTMENT ;
    PORT
      LAYER M4_m ;
      RECT 0 19.392 0.024 19.416 ;
    END
  END rw0_wd_in[339]
  PIN rw0_wd_in[340]
    DIRECTION INPUT ;
    USE SIGNAL ;
    SHAPE ABUTMENT ;
    PORT
      LAYER M4_m ;
      RECT 0 19.44 0.024 19.464 ;
    END
  END rw0_wd_in[340]
  PIN rw0_wd_in[341]
    DIRECTION INPUT ;
    USE SIGNAL ;
    SHAPE ABUTMENT ;
    PORT
      LAYER M4_m ;
      RECT 0 19.488 0.024 19.512 ;
    END
  END rw0_wd_in[341]
  PIN rw0_wd_in[342]
    DIRECTION INPUT ;
    USE SIGNAL ;
    SHAPE ABUTMENT ;
    PORT
      LAYER M4_m ;
      RECT 0 19.536 0.024 19.56 ;
    END
  END rw0_wd_in[342]
  PIN rw0_wd_in[343]
    DIRECTION INPUT ;
    USE SIGNAL ;
    SHAPE ABUTMENT ;
    PORT
      LAYER M4_m ;
      RECT 0 19.584 0.024 19.608 ;
    END
  END rw0_wd_in[343]
  PIN rw0_wd_in[344]
    DIRECTION INPUT ;
    USE SIGNAL ;
    SHAPE ABUTMENT ;
    PORT
      LAYER M4_m ;
      RECT 0 19.632 0.024 19.656 ;
    END
  END rw0_wd_in[344]
  PIN rw0_wd_in[345]
    DIRECTION INPUT ;
    USE SIGNAL ;
    SHAPE ABUTMENT ;
    PORT
      LAYER M4_m ;
      RECT 0 19.68 0.024 19.704 ;
    END
  END rw0_wd_in[345]
  PIN rw0_wd_in[346]
    DIRECTION INPUT ;
    USE SIGNAL ;
    SHAPE ABUTMENT ;
    PORT
      LAYER M4_m ;
      RECT 0 19.728 0.024 19.752 ;
    END
  END rw0_wd_in[346]
  PIN rw0_wd_in[347]
    DIRECTION INPUT ;
    USE SIGNAL ;
    SHAPE ABUTMENT ;
    PORT
      LAYER M4_m ;
      RECT 0 19.776 0.024 19.8 ;
    END
  END rw0_wd_in[347]
  PIN rw0_wd_in[348]
    DIRECTION INPUT ;
    USE SIGNAL ;
    SHAPE ABUTMENT ;
    PORT
      LAYER M4_m ;
      RECT 0 19.824 0.024 19.848 ;
    END
  END rw0_wd_in[348]
  PIN rw0_wd_in[349]
    DIRECTION INPUT ;
    USE SIGNAL ;
    SHAPE ABUTMENT ;
    PORT
      LAYER M4_m ;
      RECT 0 19.872 0.024 19.896 ;
    END
  END rw0_wd_in[349]
  PIN rw0_wd_in[350]
    DIRECTION INPUT ;
    USE SIGNAL ;
    SHAPE ABUTMENT ;
    PORT
      LAYER M4_m ;
      RECT 0 19.92 0.024 19.944 ;
    END
  END rw0_wd_in[350]
  PIN rw0_wd_in[351]
    DIRECTION INPUT ;
    USE SIGNAL ;
    SHAPE ABUTMENT ;
    PORT
      LAYER M4_m ;
      RECT 0 19.968 0.024 19.992 ;
    END
  END rw0_wd_in[351]
  PIN rw0_wd_in[352]
    DIRECTION INPUT ;
    USE SIGNAL ;
    SHAPE ABUTMENT ;
    PORT
      LAYER M4_m ;
      RECT 0 20.016 0.024 20.04 ;
    END
  END rw0_wd_in[352]
  PIN rw0_wd_in[353]
    DIRECTION INPUT ;
    USE SIGNAL ;
    SHAPE ABUTMENT ;
    PORT
      LAYER M4_m ;
      RECT 0 20.064 0.024 20.088 ;
    END
  END rw0_wd_in[353]
  PIN rw0_wd_in[354]
    DIRECTION INPUT ;
    USE SIGNAL ;
    SHAPE ABUTMENT ;
    PORT
      LAYER M4_m ;
      RECT 0 20.112 0.024 20.136 ;
    END
  END rw0_wd_in[354]
  PIN rw0_wd_in[355]
    DIRECTION INPUT ;
    USE SIGNAL ;
    SHAPE ABUTMENT ;
    PORT
      LAYER M4_m ;
      RECT 0 20.16 0.024 20.184 ;
    END
  END rw0_wd_in[355]
  PIN rw0_wd_in[356]
    DIRECTION INPUT ;
    USE SIGNAL ;
    SHAPE ABUTMENT ;
    PORT
      LAYER M4_m ;
      RECT 0 20.208 0.024 20.232 ;
    END
  END rw0_wd_in[356]
  PIN rw0_wd_in[357]
    DIRECTION INPUT ;
    USE SIGNAL ;
    SHAPE ABUTMENT ;
    PORT
      LAYER M4_m ;
      RECT 0 20.256 0.024 20.28 ;
    END
  END rw0_wd_in[357]
  PIN rw0_wd_in[358]
    DIRECTION INPUT ;
    USE SIGNAL ;
    SHAPE ABUTMENT ;
    PORT
      LAYER M4_m ;
      RECT 0 20.304 0.024 20.328 ;
    END
  END rw0_wd_in[358]
  PIN rw0_wd_in[359]
    DIRECTION INPUT ;
    USE SIGNAL ;
    SHAPE ABUTMENT ;
    PORT
      LAYER M4_m ;
      RECT 0 20.352 0.024 20.376 ;
    END
  END rw0_wd_in[359]
  PIN rw0_wd_in[360]
    DIRECTION INPUT ;
    USE SIGNAL ;
    SHAPE ABUTMENT ;
    PORT
      LAYER M4_m ;
      RECT 0 20.4 0.024 20.424 ;
    END
  END rw0_wd_in[360]
  PIN rw0_wd_in[361]
    DIRECTION INPUT ;
    USE SIGNAL ;
    SHAPE ABUTMENT ;
    PORT
      LAYER M4_m ;
      RECT 0 20.448 0.024 20.472 ;
    END
  END rw0_wd_in[361]
  PIN rw0_wd_in[362]
    DIRECTION INPUT ;
    USE SIGNAL ;
    SHAPE ABUTMENT ;
    PORT
      LAYER M4_m ;
      RECT 0 20.496 0.024 20.52 ;
    END
  END rw0_wd_in[362]
  PIN rw0_wd_in[363]
    DIRECTION INPUT ;
    USE SIGNAL ;
    SHAPE ABUTMENT ;
    PORT
      LAYER M4_m ;
      RECT 0 20.544 0.024 20.568 ;
    END
  END rw0_wd_in[363]
  PIN rw0_wd_in[364]
    DIRECTION INPUT ;
    USE SIGNAL ;
    SHAPE ABUTMENT ;
    PORT
      LAYER M4_m ;
      RECT 0 20.592 0.024 20.616 ;
    END
  END rw0_wd_in[364]
  PIN rw0_wd_in[365]
    DIRECTION INPUT ;
    USE SIGNAL ;
    SHAPE ABUTMENT ;
    PORT
      LAYER M4_m ;
      RECT 0 20.64 0.024 20.664 ;
    END
  END rw0_wd_in[365]
  PIN rw0_wd_in[366]
    DIRECTION INPUT ;
    USE SIGNAL ;
    SHAPE ABUTMENT ;
    PORT
      LAYER M4_m ;
      RECT 0 20.688 0.024 20.712 ;
    END
  END rw0_wd_in[366]
  PIN rw0_wd_in[367]
    DIRECTION INPUT ;
    USE SIGNAL ;
    SHAPE ABUTMENT ;
    PORT
      LAYER M4_m ;
      RECT 0 20.736 0.024 20.76 ;
    END
  END rw0_wd_in[367]
  PIN rw0_wd_in[368]
    DIRECTION INPUT ;
    USE SIGNAL ;
    SHAPE ABUTMENT ;
    PORT
      LAYER M4_m ;
      RECT 0 20.784 0.024 20.808 ;
    END
  END rw0_wd_in[368]
  PIN rw0_wd_in[369]
    DIRECTION INPUT ;
    USE SIGNAL ;
    SHAPE ABUTMENT ;
    PORT
      LAYER M4_m ;
      RECT 0 20.832 0.024 20.856 ;
    END
  END rw0_wd_in[369]
  PIN rw0_wd_in[370]
    DIRECTION INPUT ;
    USE SIGNAL ;
    SHAPE ABUTMENT ;
    PORT
      LAYER M4_m ;
      RECT 0 20.88 0.024 20.904 ;
    END
  END rw0_wd_in[370]
  PIN rw0_wd_in[371]
    DIRECTION INPUT ;
    USE SIGNAL ;
    SHAPE ABUTMENT ;
    PORT
      LAYER M4_m ;
      RECT 0 20.928 0.024 20.952 ;
    END
  END rw0_wd_in[371]
  PIN rw0_wd_in[372]
    DIRECTION INPUT ;
    USE SIGNAL ;
    SHAPE ABUTMENT ;
    PORT
      LAYER M4_m ;
      RECT 0 20.976 0.024 21 ;
    END
  END rw0_wd_in[372]
  PIN rw0_wd_in[373]
    DIRECTION INPUT ;
    USE SIGNAL ;
    SHAPE ABUTMENT ;
    PORT
      LAYER M4_m ;
      RECT 0 21.024 0.024 21.048 ;
    END
  END rw0_wd_in[373]
  PIN rw0_wd_in[374]
    DIRECTION INPUT ;
    USE SIGNAL ;
    SHAPE ABUTMENT ;
    PORT
      LAYER M4_m ;
      RECT 0 21.072 0.024 21.096 ;
    END
  END rw0_wd_in[374]
  PIN rw0_wd_in[375]
    DIRECTION INPUT ;
    USE SIGNAL ;
    SHAPE ABUTMENT ;
    PORT
      LAYER M4_m ;
      RECT 0 21.12 0.024 21.144 ;
    END
  END rw0_wd_in[375]
  PIN rw0_wd_in[376]
    DIRECTION INPUT ;
    USE SIGNAL ;
    SHAPE ABUTMENT ;
    PORT
      LAYER M4_m ;
      RECT 0 21.168 0.024 21.192 ;
    END
  END rw0_wd_in[376]
  PIN rw0_wd_in[377]
    DIRECTION INPUT ;
    USE SIGNAL ;
    SHAPE ABUTMENT ;
    PORT
      LAYER M4_m ;
      RECT 0 21.216 0.024 21.24 ;
    END
  END rw0_wd_in[377]
  PIN rw0_wd_in[378]
    DIRECTION INPUT ;
    USE SIGNAL ;
    SHAPE ABUTMENT ;
    PORT
      LAYER M4_m ;
      RECT 0 21.264 0.024 21.288 ;
    END
  END rw0_wd_in[378]
  PIN rw0_wd_in[379]
    DIRECTION INPUT ;
    USE SIGNAL ;
    SHAPE ABUTMENT ;
    PORT
      LAYER M4_m ;
      RECT 0 21.312 0.024 21.336 ;
    END
  END rw0_wd_in[379]
  PIN rw0_wd_in[380]
    DIRECTION INPUT ;
    USE SIGNAL ;
    SHAPE ABUTMENT ;
    PORT
      LAYER M4_m ;
      RECT 0 21.36 0.024 21.384 ;
    END
  END rw0_wd_in[380]
  PIN rw0_wd_in[381]
    DIRECTION INPUT ;
    USE SIGNAL ;
    SHAPE ABUTMENT ;
    PORT
      LAYER M4_m ;
      RECT 0 21.408 0.024 21.432 ;
    END
  END rw0_wd_in[381]
  PIN rw0_wd_in[382]
    DIRECTION INPUT ;
    USE SIGNAL ;
    SHAPE ABUTMENT ;
    PORT
      LAYER M4_m ;
      RECT 0 21.456 0.024 21.48 ;
    END
  END rw0_wd_in[382]
  PIN rw0_wd_in[383]
    DIRECTION INPUT ;
    USE SIGNAL ;
    SHAPE ABUTMENT ;
    PORT
      LAYER M4_m ;
      RECT 0 21.504 0.024 21.528 ;
    END
  END rw0_wd_in[383]
  PIN rw0_wd_in[384]
    DIRECTION INPUT ;
    USE SIGNAL ;
    SHAPE ABUTMENT ;
    PORT
      LAYER M4_m ;
      RECT 0 21.552 0.024 21.576 ;
    END
  END rw0_wd_in[384]
  PIN rw0_wd_in[385]
    DIRECTION INPUT ;
    USE SIGNAL ;
    SHAPE ABUTMENT ;
    PORT
      LAYER M4_m ;
      RECT 0 21.6 0.024 21.624 ;
    END
  END rw0_wd_in[385]
  PIN rw0_wd_in[386]
    DIRECTION INPUT ;
    USE SIGNAL ;
    SHAPE ABUTMENT ;
    PORT
      LAYER M4_m ;
      RECT 0 21.648 0.024 21.672 ;
    END
  END rw0_wd_in[386]
  PIN rw0_wd_in[387]
    DIRECTION INPUT ;
    USE SIGNAL ;
    SHAPE ABUTMENT ;
    PORT
      LAYER M4_m ;
      RECT 0 21.696 0.024 21.72 ;
    END
  END rw0_wd_in[387]
  PIN rw0_wd_in[388]
    DIRECTION INPUT ;
    USE SIGNAL ;
    SHAPE ABUTMENT ;
    PORT
      LAYER M4_m ;
      RECT 0 21.744 0.024 21.768 ;
    END
  END rw0_wd_in[388]
  PIN rw0_wd_in[389]
    DIRECTION INPUT ;
    USE SIGNAL ;
    SHAPE ABUTMENT ;
    PORT
      LAYER M4_m ;
      RECT 0 21.792 0.024 21.816 ;
    END
  END rw0_wd_in[389]
  PIN rw0_wd_in[390]
    DIRECTION INPUT ;
    USE SIGNAL ;
    SHAPE ABUTMENT ;
    PORT
      LAYER M4_m ;
      RECT 0 21.84 0.024 21.864 ;
    END
  END rw0_wd_in[390]
  PIN rw0_wd_in[391]
    DIRECTION INPUT ;
    USE SIGNAL ;
    SHAPE ABUTMENT ;
    PORT
      LAYER M4_m ;
      RECT 0 21.888 0.024 21.912 ;
    END
  END rw0_wd_in[391]
  PIN rw0_wd_in[392]
    DIRECTION INPUT ;
    USE SIGNAL ;
    SHAPE ABUTMENT ;
    PORT
      LAYER M4_m ;
      RECT 0 21.936 0.024 21.96 ;
    END
  END rw0_wd_in[392]
  PIN rw0_wd_in[393]
    DIRECTION INPUT ;
    USE SIGNAL ;
    SHAPE ABUTMENT ;
    PORT
      LAYER M4_m ;
      RECT 0 21.984 0.024 22.008 ;
    END
  END rw0_wd_in[393]
  PIN rw0_wd_in[394]
    DIRECTION INPUT ;
    USE SIGNAL ;
    SHAPE ABUTMENT ;
    PORT
      LAYER M4_m ;
      RECT 0 22.032 0.024 22.056 ;
    END
  END rw0_wd_in[394]
  PIN rw0_wd_in[395]
    DIRECTION INPUT ;
    USE SIGNAL ;
    SHAPE ABUTMENT ;
    PORT
      LAYER M4_m ;
      RECT 0 22.08 0.024 22.104 ;
    END
  END rw0_wd_in[395]
  PIN rw0_wd_in[396]
    DIRECTION INPUT ;
    USE SIGNAL ;
    SHAPE ABUTMENT ;
    PORT
      LAYER M4_m ;
      RECT 0 22.128 0.024 22.152 ;
    END
  END rw0_wd_in[396]
  PIN rw0_wd_in[397]
    DIRECTION INPUT ;
    USE SIGNAL ;
    SHAPE ABUTMENT ;
    PORT
      LAYER M4_m ;
      RECT 0 22.176 0.024 22.2 ;
    END
  END rw0_wd_in[397]
  PIN rw0_wd_in[398]
    DIRECTION INPUT ;
    USE SIGNAL ;
    SHAPE ABUTMENT ;
    PORT
      LAYER M4_m ;
      RECT 0 22.224 0.024 22.248 ;
    END
  END rw0_wd_in[398]
  PIN rw0_wd_in[399]
    DIRECTION INPUT ;
    USE SIGNAL ;
    SHAPE ABUTMENT ;
    PORT
      LAYER M4_m ;
      RECT 0 22.272 0.024 22.296 ;
    END
  END rw0_wd_in[399]
  PIN rw0_wd_in[400]
    DIRECTION INPUT ;
    USE SIGNAL ;
    SHAPE ABUTMENT ;
    PORT
      LAYER M4_m ;
      RECT 0 22.32 0.024 22.344 ;
    END
  END rw0_wd_in[400]
  PIN rw0_wd_in[401]
    DIRECTION INPUT ;
    USE SIGNAL ;
    SHAPE ABUTMENT ;
    PORT
      LAYER M4_m ;
      RECT 0 22.368 0.024 22.392 ;
    END
  END rw0_wd_in[401]
  PIN rw0_wd_in[402]
    DIRECTION INPUT ;
    USE SIGNAL ;
    SHAPE ABUTMENT ;
    PORT
      LAYER M4_m ;
      RECT 0 22.416 0.024 22.44 ;
    END
  END rw0_wd_in[402]
  PIN rw0_wd_in[403]
    DIRECTION INPUT ;
    USE SIGNAL ;
    SHAPE ABUTMENT ;
    PORT
      LAYER M4_m ;
      RECT 0 22.464 0.024 22.488 ;
    END
  END rw0_wd_in[403]
  PIN rw0_wd_in[404]
    DIRECTION INPUT ;
    USE SIGNAL ;
    SHAPE ABUTMENT ;
    PORT
      LAYER M4_m ;
      RECT 0 22.512 0.024 22.536 ;
    END
  END rw0_wd_in[404]
  PIN rw0_wd_in[405]
    DIRECTION INPUT ;
    USE SIGNAL ;
    SHAPE ABUTMENT ;
    PORT
      LAYER M4_m ;
      RECT 0 22.56 0.024 22.584 ;
    END
  END rw0_wd_in[405]
  PIN rw0_wd_in[406]
    DIRECTION INPUT ;
    USE SIGNAL ;
    SHAPE ABUTMENT ;
    PORT
      LAYER M4_m ;
      RECT 0 22.608 0.024 22.632 ;
    END
  END rw0_wd_in[406]
  PIN rw0_wd_in[407]
    DIRECTION INPUT ;
    USE SIGNAL ;
    SHAPE ABUTMENT ;
    PORT
      LAYER M4_m ;
      RECT 0 22.656 0.024 22.68 ;
    END
  END rw0_wd_in[407]
  PIN rw0_wd_in[408]
    DIRECTION INPUT ;
    USE SIGNAL ;
    SHAPE ABUTMENT ;
    PORT
      LAYER M4_m ;
      RECT 0 22.704 0.024 22.728 ;
    END
  END rw0_wd_in[408]
  PIN rw0_wd_in[409]
    DIRECTION INPUT ;
    USE SIGNAL ;
    SHAPE ABUTMENT ;
    PORT
      LAYER M4_m ;
      RECT 0 22.752 0.024 22.776 ;
    END
  END rw0_wd_in[409]
  PIN rw0_wd_in[410]
    DIRECTION INPUT ;
    USE SIGNAL ;
    SHAPE ABUTMENT ;
    PORT
      LAYER M4_m ;
      RECT 0 22.8 0.024 22.824 ;
    END
  END rw0_wd_in[410]
  PIN rw0_wd_in[411]
    DIRECTION INPUT ;
    USE SIGNAL ;
    SHAPE ABUTMENT ;
    PORT
      LAYER M4_m ;
      RECT 0 22.848 0.024 22.872 ;
    END
  END rw0_wd_in[411]
  PIN rw0_wd_in[412]
    DIRECTION INPUT ;
    USE SIGNAL ;
    SHAPE ABUTMENT ;
    PORT
      LAYER M4_m ;
      RECT 0 22.896 0.024 22.92 ;
    END
  END rw0_wd_in[412]
  PIN rw0_wd_in[413]
    DIRECTION INPUT ;
    USE SIGNAL ;
    SHAPE ABUTMENT ;
    PORT
      LAYER M4_m ;
      RECT 0 22.944 0.024 22.968 ;
    END
  END rw0_wd_in[413]
  PIN rw0_wd_in[414]
    DIRECTION INPUT ;
    USE SIGNAL ;
    SHAPE ABUTMENT ;
    PORT
      LAYER M4_m ;
      RECT 0 22.992 0.024 23.016 ;
    END
  END rw0_wd_in[414]
  PIN rw0_wd_in[415]
    DIRECTION INPUT ;
    USE SIGNAL ;
    SHAPE ABUTMENT ;
    PORT
      LAYER M4_m ;
      RECT 0 23.04 0.024 23.064 ;
    END
  END rw0_wd_in[415]
  PIN rw0_wd_in[416]
    DIRECTION INPUT ;
    USE SIGNAL ;
    SHAPE ABUTMENT ;
    PORT
      LAYER M4_m ;
      RECT 0 23.088 0.024 23.112 ;
    END
  END rw0_wd_in[416]
  PIN rw0_wd_in[417]
    DIRECTION INPUT ;
    USE SIGNAL ;
    SHAPE ABUTMENT ;
    PORT
      LAYER M4_m ;
      RECT 0 23.136 0.024 23.16 ;
    END
  END rw0_wd_in[417]
  PIN rw0_wd_in[418]
    DIRECTION INPUT ;
    USE SIGNAL ;
    SHAPE ABUTMENT ;
    PORT
      LAYER M4_m ;
      RECT 0 23.184 0.024 23.208 ;
    END
  END rw0_wd_in[418]
  PIN rw0_wd_in[419]
    DIRECTION INPUT ;
    USE SIGNAL ;
    SHAPE ABUTMENT ;
    PORT
      LAYER M4_m ;
      RECT 0 23.232 0.024 23.256 ;
    END
  END rw0_wd_in[419]
  PIN rw0_wd_in[420]
    DIRECTION INPUT ;
    USE SIGNAL ;
    SHAPE ABUTMENT ;
    PORT
      LAYER M4_m ;
      RECT 0 23.28 0.024 23.304 ;
    END
  END rw0_wd_in[420]
  PIN rw0_wd_in[421]
    DIRECTION INPUT ;
    USE SIGNAL ;
    SHAPE ABUTMENT ;
    PORT
      LAYER M4_m ;
      RECT 0 23.328 0.024 23.352 ;
    END
  END rw0_wd_in[421]
  PIN rw0_wd_in[422]
    DIRECTION INPUT ;
    USE SIGNAL ;
    SHAPE ABUTMENT ;
    PORT
      LAYER M4_m ;
      RECT 0 23.376 0.024 23.4 ;
    END
  END rw0_wd_in[422]
  PIN rw0_wd_in[423]
    DIRECTION INPUT ;
    USE SIGNAL ;
    SHAPE ABUTMENT ;
    PORT
      LAYER M4_m ;
      RECT 0 23.424 0.024 23.448 ;
    END
  END rw0_wd_in[423]
  PIN rw0_wd_in[424]
    DIRECTION INPUT ;
    USE SIGNAL ;
    SHAPE ABUTMENT ;
    PORT
      LAYER M4_m ;
      RECT 0 23.472 0.024 23.496 ;
    END
  END rw0_wd_in[424]
  PIN rw0_wd_in[425]
    DIRECTION INPUT ;
    USE SIGNAL ;
    SHAPE ABUTMENT ;
    PORT
      LAYER M4_m ;
      RECT 0 23.52 0.024 23.544 ;
    END
  END rw0_wd_in[425]
  PIN rw0_wd_in[426]
    DIRECTION INPUT ;
    USE SIGNAL ;
    SHAPE ABUTMENT ;
    PORT
      LAYER M4_m ;
      RECT 0 23.568 0.024 23.592 ;
    END
  END rw0_wd_in[426]
  PIN rw0_wd_in[427]
    DIRECTION INPUT ;
    USE SIGNAL ;
    SHAPE ABUTMENT ;
    PORT
      LAYER M4_m ;
      RECT 0 23.616 0.024 23.64 ;
    END
  END rw0_wd_in[427]
  PIN rw0_wd_in[428]
    DIRECTION INPUT ;
    USE SIGNAL ;
    SHAPE ABUTMENT ;
    PORT
      LAYER M4_m ;
      RECT 0 23.664 0.024 23.688 ;
    END
  END rw0_wd_in[428]
  PIN rw0_wd_in[429]
    DIRECTION INPUT ;
    USE SIGNAL ;
    SHAPE ABUTMENT ;
    PORT
      LAYER M4_m ;
      RECT 0 23.712 0.024 23.736 ;
    END
  END rw0_wd_in[429]
  PIN rw0_wd_in[430]
    DIRECTION INPUT ;
    USE SIGNAL ;
    SHAPE ABUTMENT ;
    PORT
      LAYER M4_m ;
      RECT 0 23.76 0.024 23.784 ;
    END
  END rw0_wd_in[430]
  PIN rw0_wd_in[431]
    DIRECTION INPUT ;
    USE SIGNAL ;
    SHAPE ABUTMENT ;
    PORT
      LAYER M4_m ;
      RECT 0 23.808 0.024 23.832 ;
    END
  END rw0_wd_in[431]
  PIN rw0_wd_in[432]
    DIRECTION INPUT ;
    USE SIGNAL ;
    SHAPE ABUTMENT ;
    PORT
      LAYER M4_m ;
      RECT 0 23.856 0.024 23.88 ;
    END
  END rw0_wd_in[432]
  PIN rw0_wd_in[433]
    DIRECTION INPUT ;
    USE SIGNAL ;
    SHAPE ABUTMENT ;
    PORT
      LAYER M4_m ;
      RECT 0 23.904 0.024 23.928 ;
    END
  END rw0_wd_in[433]
  PIN rw0_wd_in[434]
    DIRECTION INPUT ;
    USE SIGNAL ;
    SHAPE ABUTMENT ;
    PORT
      LAYER M4_m ;
      RECT 0 23.952 0.024 23.976 ;
    END
  END rw0_wd_in[434]
  PIN rw0_wd_in[435]
    DIRECTION INPUT ;
    USE SIGNAL ;
    SHAPE ABUTMENT ;
    PORT
      LAYER M4_m ;
      RECT 0 24 0.024 24.024 ;
    END
  END rw0_wd_in[435]
  PIN rw0_wd_in[436]
    DIRECTION INPUT ;
    USE SIGNAL ;
    SHAPE ABUTMENT ;
    PORT
      LAYER M4_m ;
      RECT 0 24.048 0.024 24.072 ;
    END
  END rw0_wd_in[436]
  PIN rw0_wd_in[437]
    DIRECTION INPUT ;
    USE SIGNAL ;
    SHAPE ABUTMENT ;
    PORT
      LAYER M4_m ;
      RECT 0 24.096 0.024 24.12 ;
    END
  END rw0_wd_in[437]
  PIN rw0_wd_in[438]
    DIRECTION INPUT ;
    USE SIGNAL ;
    SHAPE ABUTMENT ;
    PORT
      LAYER M4_m ;
      RECT 0 24.144 0.024 24.168 ;
    END
  END rw0_wd_in[438]
  PIN rw0_wd_in[439]
    DIRECTION INPUT ;
    USE SIGNAL ;
    SHAPE ABUTMENT ;
    PORT
      LAYER M4_m ;
      RECT 0 24.192 0.024 24.216 ;
    END
  END rw0_wd_in[439]
  PIN rw0_wd_in[440]
    DIRECTION INPUT ;
    USE SIGNAL ;
    SHAPE ABUTMENT ;
    PORT
      LAYER M4_m ;
      RECT 0 24.24 0.024 24.264 ;
    END
  END rw0_wd_in[440]
  PIN rw0_wd_in[441]
    DIRECTION INPUT ;
    USE SIGNAL ;
    SHAPE ABUTMENT ;
    PORT
      LAYER M4_m ;
      RECT 0 24.288 0.024 24.312 ;
    END
  END rw0_wd_in[441]
  PIN rw0_wd_in[442]
    DIRECTION INPUT ;
    USE SIGNAL ;
    SHAPE ABUTMENT ;
    PORT
      LAYER M4_m ;
      RECT 0 24.336 0.024 24.36 ;
    END
  END rw0_wd_in[442]
  PIN rw0_wd_in[443]
    DIRECTION INPUT ;
    USE SIGNAL ;
    SHAPE ABUTMENT ;
    PORT
      LAYER M4_m ;
      RECT 0 24.384 0.024 24.408 ;
    END
  END rw0_wd_in[443]
  PIN rw0_wd_in[444]
    DIRECTION INPUT ;
    USE SIGNAL ;
    SHAPE ABUTMENT ;
    PORT
      LAYER M4_m ;
      RECT 0 24.432 0.024 24.456 ;
    END
  END rw0_wd_in[444]
  PIN rw0_wd_in[445]
    DIRECTION INPUT ;
    USE SIGNAL ;
    SHAPE ABUTMENT ;
    PORT
      LAYER M4_m ;
      RECT 0 24.48 0.024 24.504 ;
    END
  END rw0_wd_in[445]
  PIN rw0_wd_in[446]
    DIRECTION INPUT ;
    USE SIGNAL ;
    SHAPE ABUTMENT ;
    PORT
      LAYER M4_m ;
      RECT 0 24.528 0.024 24.552 ;
    END
  END rw0_wd_in[446]
  PIN rw0_wd_in[447]
    DIRECTION INPUT ;
    USE SIGNAL ;
    SHAPE ABUTMENT ;
    PORT
      LAYER M4_m ;
      RECT 0 24.576 0.024 24.6 ;
    END
  END rw0_wd_in[447]
  PIN rw0_wd_in[448]
    DIRECTION INPUT ;
    USE SIGNAL ;
    SHAPE ABUTMENT ;
    PORT
      LAYER M4_m ;
      RECT 0 24.624 0.024 24.648 ;
    END
  END rw0_wd_in[448]
  PIN rw0_wd_in[449]
    DIRECTION INPUT ;
    USE SIGNAL ;
    SHAPE ABUTMENT ;
    PORT
      LAYER M4_m ;
      RECT 0 24.672 0.024 24.696 ;
    END
  END rw0_wd_in[449]
  PIN rw0_wd_in[450]
    DIRECTION INPUT ;
    USE SIGNAL ;
    SHAPE ABUTMENT ;
    PORT
      LAYER M4_m ;
      RECT 0 24.72 0.024 24.744 ;
    END
  END rw0_wd_in[450]
  PIN rw0_wd_in[451]
    DIRECTION INPUT ;
    USE SIGNAL ;
    SHAPE ABUTMENT ;
    PORT
      LAYER M4_m ;
      RECT 0 24.768 0.024 24.792 ;
    END
  END rw0_wd_in[451]
  PIN rw0_wd_in[452]
    DIRECTION INPUT ;
    USE SIGNAL ;
    SHAPE ABUTMENT ;
    PORT
      LAYER M4_m ;
      RECT 0 24.816 0.024 24.84 ;
    END
  END rw0_wd_in[452]
  PIN rw0_wd_in[453]
    DIRECTION INPUT ;
    USE SIGNAL ;
    SHAPE ABUTMENT ;
    PORT
      LAYER M4_m ;
      RECT 0 24.864 0.024 24.888 ;
    END
  END rw0_wd_in[453]
  PIN rw0_wd_in[454]
    DIRECTION INPUT ;
    USE SIGNAL ;
    SHAPE ABUTMENT ;
    PORT
      LAYER M4_m ;
      RECT 0 24.912 0.024 24.936 ;
    END
  END rw0_wd_in[454]
  PIN rw0_wd_in[455]
    DIRECTION INPUT ;
    USE SIGNAL ;
    SHAPE ABUTMENT ;
    PORT
      LAYER M4_m ;
      RECT 0 24.96 0.024 24.984 ;
    END
  END rw0_wd_in[455]
  PIN rw0_wd_in[456]
    DIRECTION INPUT ;
    USE SIGNAL ;
    SHAPE ABUTMENT ;
    PORT
      LAYER M4_m ;
      RECT 0 25.008 0.024 25.032 ;
    END
  END rw0_wd_in[456]
  PIN rw0_wd_in[457]
    DIRECTION INPUT ;
    USE SIGNAL ;
    SHAPE ABUTMENT ;
    PORT
      LAYER M4_m ;
      RECT 0 25.056 0.024 25.08 ;
    END
  END rw0_wd_in[457]
  PIN rw0_wd_in[458]
    DIRECTION INPUT ;
    USE SIGNAL ;
    SHAPE ABUTMENT ;
    PORT
      LAYER M4_m ;
      RECT 0 25.104 0.024 25.128 ;
    END
  END rw0_wd_in[458]
  PIN rw0_wd_in[459]
    DIRECTION INPUT ;
    USE SIGNAL ;
    SHAPE ABUTMENT ;
    PORT
      LAYER M4_m ;
      RECT 0 25.152 0.024 25.176 ;
    END
  END rw0_wd_in[459]
  PIN rw0_wd_in[460]
    DIRECTION INPUT ;
    USE SIGNAL ;
    SHAPE ABUTMENT ;
    PORT
      LAYER M4_m ;
      RECT 0 25.2 0.024 25.224 ;
    END
  END rw0_wd_in[460]
  PIN rw0_wd_in[461]
    DIRECTION INPUT ;
    USE SIGNAL ;
    SHAPE ABUTMENT ;
    PORT
      LAYER M4_m ;
      RECT 0 25.248 0.024 25.272 ;
    END
  END rw0_wd_in[461]
  PIN rw0_wd_in[462]
    DIRECTION INPUT ;
    USE SIGNAL ;
    SHAPE ABUTMENT ;
    PORT
      LAYER M4_m ;
      RECT 0 25.296 0.024 25.32 ;
    END
  END rw0_wd_in[462]
  PIN rw0_wd_in[463]
    DIRECTION INPUT ;
    USE SIGNAL ;
    SHAPE ABUTMENT ;
    PORT
      LAYER M4_m ;
      RECT 0 25.344 0.024 25.368 ;
    END
  END rw0_wd_in[463]
  PIN rw0_wd_in[464]
    DIRECTION INPUT ;
    USE SIGNAL ;
    SHAPE ABUTMENT ;
    PORT
      LAYER M4_m ;
      RECT 0 25.392 0.024 25.416 ;
    END
  END rw0_wd_in[464]
  PIN rw0_wd_in[465]
    DIRECTION INPUT ;
    USE SIGNAL ;
    SHAPE ABUTMENT ;
    PORT
      LAYER M4_m ;
      RECT 0 25.44 0.024 25.464 ;
    END
  END rw0_wd_in[465]
  PIN rw0_wd_in[466]
    DIRECTION INPUT ;
    USE SIGNAL ;
    SHAPE ABUTMENT ;
    PORT
      LAYER M4_m ;
      RECT 0 25.488 0.024 25.512 ;
    END
  END rw0_wd_in[466]
  PIN rw0_wd_in[467]
    DIRECTION INPUT ;
    USE SIGNAL ;
    SHAPE ABUTMENT ;
    PORT
      LAYER M4_m ;
      RECT 0 25.536 0.024 25.56 ;
    END
  END rw0_wd_in[467]
  PIN rw0_wd_in[468]
    DIRECTION INPUT ;
    USE SIGNAL ;
    SHAPE ABUTMENT ;
    PORT
      LAYER M4_m ;
      RECT 0 25.584 0.024 25.608 ;
    END
  END rw0_wd_in[468]
  PIN rw0_wd_in[469]
    DIRECTION INPUT ;
    USE SIGNAL ;
    SHAPE ABUTMENT ;
    PORT
      LAYER M4_m ;
      RECT 0 25.632 0.024 25.656 ;
    END
  END rw0_wd_in[469]
  PIN rw0_wd_in[470]
    DIRECTION INPUT ;
    USE SIGNAL ;
    SHAPE ABUTMENT ;
    PORT
      LAYER M4_m ;
      RECT 0 25.68 0.024 25.704 ;
    END
  END rw0_wd_in[470]
  PIN rw0_wd_in[471]
    DIRECTION INPUT ;
    USE SIGNAL ;
    SHAPE ABUTMENT ;
    PORT
      LAYER M4_m ;
      RECT 0 25.728 0.024 25.752 ;
    END
  END rw0_wd_in[471]
  PIN rw0_wd_in[472]
    DIRECTION INPUT ;
    USE SIGNAL ;
    SHAPE ABUTMENT ;
    PORT
      LAYER M4_m ;
      RECT 0 25.776 0.024 25.8 ;
    END
  END rw0_wd_in[472]
  PIN rw0_wd_in[473]
    DIRECTION INPUT ;
    USE SIGNAL ;
    SHAPE ABUTMENT ;
    PORT
      LAYER M4_m ;
      RECT 0 25.824 0.024 25.848 ;
    END
  END rw0_wd_in[473]
  PIN rw0_wd_in[474]
    DIRECTION INPUT ;
    USE SIGNAL ;
    SHAPE ABUTMENT ;
    PORT
      LAYER M4_m ;
      RECT 0 25.872 0.024 25.896 ;
    END
  END rw0_wd_in[474]
  PIN rw0_wd_in[475]
    DIRECTION INPUT ;
    USE SIGNAL ;
    SHAPE ABUTMENT ;
    PORT
      LAYER M4_m ;
      RECT 0 25.92 0.024 25.944 ;
    END
  END rw0_wd_in[475]
  PIN rw0_wd_in[476]
    DIRECTION INPUT ;
    USE SIGNAL ;
    SHAPE ABUTMENT ;
    PORT
      LAYER M4_m ;
      RECT 0 25.968 0.024 25.992 ;
    END
  END rw0_wd_in[476]
  PIN rw0_wd_in[477]
    DIRECTION INPUT ;
    USE SIGNAL ;
    SHAPE ABUTMENT ;
    PORT
      LAYER M4_m ;
      RECT 0 26.016 0.024 26.04 ;
    END
  END rw0_wd_in[477]
  PIN rw0_wd_in[478]
    DIRECTION INPUT ;
    USE SIGNAL ;
    SHAPE ABUTMENT ;
    PORT
      LAYER M4_m ;
      RECT 0 26.064 0.024 26.088 ;
    END
  END rw0_wd_in[478]
  PIN rw0_wd_in[479]
    DIRECTION INPUT ;
    USE SIGNAL ;
    SHAPE ABUTMENT ;
    PORT
      LAYER M4_m ;
      RECT 0 26.112 0.024 26.136 ;
    END
  END rw0_wd_in[479]
  PIN rw0_wd_in[480]
    DIRECTION INPUT ;
    USE SIGNAL ;
    SHAPE ABUTMENT ;
    PORT
      LAYER M4_m ;
      RECT 0 26.16 0.024 26.184 ;
    END
  END rw0_wd_in[480]
  PIN rw0_wd_in[481]
    DIRECTION INPUT ;
    USE SIGNAL ;
    SHAPE ABUTMENT ;
    PORT
      LAYER M4_m ;
      RECT 0 26.208 0.024 26.232 ;
    END
  END rw0_wd_in[481]
  PIN rw0_wd_in[482]
    DIRECTION INPUT ;
    USE SIGNAL ;
    SHAPE ABUTMENT ;
    PORT
      LAYER M4_m ;
      RECT 0 26.256 0.024 26.28 ;
    END
  END rw0_wd_in[482]
  PIN rw0_wd_in[483]
    DIRECTION INPUT ;
    USE SIGNAL ;
    SHAPE ABUTMENT ;
    PORT
      LAYER M4_m ;
      RECT 0 26.304 0.024 26.328 ;
    END
  END rw0_wd_in[483]
  PIN rw0_wd_in[484]
    DIRECTION INPUT ;
    USE SIGNAL ;
    SHAPE ABUTMENT ;
    PORT
      LAYER M4_m ;
      RECT 0 26.352 0.024 26.376 ;
    END
  END rw0_wd_in[484]
  PIN rw0_wd_in[485]
    DIRECTION INPUT ;
    USE SIGNAL ;
    SHAPE ABUTMENT ;
    PORT
      LAYER M4_m ;
      RECT 0 26.4 0.024 26.424 ;
    END
  END rw0_wd_in[485]
  PIN rw0_wd_in[486]
    DIRECTION INPUT ;
    USE SIGNAL ;
    SHAPE ABUTMENT ;
    PORT
      LAYER M4_m ;
      RECT 138.659 0.048 138.683 0.072 ;
    END
  END rw0_wd_in[486]
  PIN rw0_wd_in[487]
    DIRECTION INPUT ;
    USE SIGNAL ;
    SHAPE ABUTMENT ;
    PORT
      LAYER M4_m ;
      RECT 138.659 0.096 138.683 0.12 ;
    END
  END rw0_wd_in[487]
  PIN rw0_wd_in[488]
    DIRECTION INPUT ;
    USE SIGNAL ;
    SHAPE ABUTMENT ;
    PORT
      LAYER M4_m ;
      RECT 138.659 0.144 138.683 0.168 ;
    END
  END rw0_wd_in[488]
  PIN rw0_wd_in[489]
    DIRECTION INPUT ;
    USE SIGNAL ;
    SHAPE ABUTMENT ;
    PORT
      LAYER M4_m ;
      RECT 138.659 0.192 138.683 0.216 ;
    END
  END rw0_wd_in[489]
  PIN rw0_wd_in[490]
    DIRECTION INPUT ;
    USE SIGNAL ;
    SHAPE ABUTMENT ;
    PORT
      LAYER M4_m ;
      RECT 138.659 0.24 138.683 0.264 ;
    END
  END rw0_wd_in[490]
  PIN rw0_wd_in[491]
    DIRECTION INPUT ;
    USE SIGNAL ;
    SHAPE ABUTMENT ;
    PORT
      LAYER M4_m ;
      RECT 138.659 0.288 138.683 0.312 ;
    END
  END rw0_wd_in[491]
  PIN rw0_wd_in[492]
    DIRECTION INPUT ;
    USE SIGNAL ;
    SHAPE ABUTMENT ;
    PORT
      LAYER M4_m ;
      RECT 138.659 0.336 138.683 0.36 ;
    END
  END rw0_wd_in[492]
  PIN rw0_wd_in[493]
    DIRECTION INPUT ;
    USE SIGNAL ;
    SHAPE ABUTMENT ;
    PORT
      LAYER M4_m ;
      RECT 138.659 0.384 138.683 0.408 ;
    END
  END rw0_wd_in[493]
  PIN rw0_wd_in[494]
    DIRECTION INPUT ;
    USE SIGNAL ;
    SHAPE ABUTMENT ;
    PORT
      LAYER M4_m ;
      RECT 138.659 0.432 138.683 0.456 ;
    END
  END rw0_wd_in[494]
  PIN rw0_wd_in[495]
    DIRECTION INPUT ;
    USE SIGNAL ;
    SHAPE ABUTMENT ;
    PORT
      LAYER M4_m ;
      RECT 138.659 0.48 138.683 0.504 ;
    END
  END rw0_wd_in[495]
  PIN rw0_wd_in[496]
    DIRECTION INPUT ;
    USE SIGNAL ;
    SHAPE ABUTMENT ;
    PORT
      LAYER M4_m ;
      RECT 138.659 0.528 138.683 0.552 ;
    END
  END rw0_wd_in[496]
  PIN rw0_wd_in[497]
    DIRECTION INPUT ;
    USE SIGNAL ;
    SHAPE ABUTMENT ;
    PORT
      LAYER M4_m ;
      RECT 138.659 0.576 138.683 0.6 ;
    END
  END rw0_wd_in[497]
  PIN rw0_wd_in[498]
    DIRECTION INPUT ;
    USE SIGNAL ;
    SHAPE ABUTMENT ;
    PORT
      LAYER M4_m ;
      RECT 138.659 0.624 138.683 0.648 ;
    END
  END rw0_wd_in[498]
  PIN rw0_wd_in[499]
    DIRECTION INPUT ;
    USE SIGNAL ;
    SHAPE ABUTMENT ;
    PORT
      LAYER M4_m ;
      RECT 138.659 0.672 138.683 0.696 ;
    END
  END rw0_wd_in[499]
  PIN rw0_wd_in[500]
    DIRECTION INPUT ;
    USE SIGNAL ;
    SHAPE ABUTMENT ;
    PORT
      LAYER M4_m ;
      RECT 138.659 0.72 138.683 0.744 ;
    END
  END rw0_wd_in[500]
  PIN rw0_wd_in[501]
    DIRECTION INPUT ;
    USE SIGNAL ;
    SHAPE ABUTMENT ;
    PORT
      LAYER M4_m ;
      RECT 138.659 0.768 138.683 0.792 ;
    END
  END rw0_wd_in[501]
  PIN rw0_wd_in[502]
    DIRECTION INPUT ;
    USE SIGNAL ;
    SHAPE ABUTMENT ;
    PORT
      LAYER M4_m ;
      RECT 138.659 0.816 138.683 0.84 ;
    END
  END rw0_wd_in[502]
  PIN rw0_wd_in[503]
    DIRECTION INPUT ;
    USE SIGNAL ;
    SHAPE ABUTMENT ;
    PORT
      LAYER M4_m ;
      RECT 138.659 0.864 138.683 0.888 ;
    END
  END rw0_wd_in[503]
  PIN rw0_wd_in[504]
    DIRECTION INPUT ;
    USE SIGNAL ;
    SHAPE ABUTMENT ;
    PORT
      LAYER M4_m ;
      RECT 138.659 0.912 138.683 0.936 ;
    END
  END rw0_wd_in[504]
  PIN rw0_wd_in[505]
    DIRECTION INPUT ;
    USE SIGNAL ;
    SHAPE ABUTMENT ;
    PORT
      LAYER M4_m ;
      RECT 138.659 0.96 138.683 0.984 ;
    END
  END rw0_wd_in[505]
  PIN rw0_wd_in[506]
    DIRECTION INPUT ;
    USE SIGNAL ;
    SHAPE ABUTMENT ;
    PORT
      LAYER M4_m ;
      RECT 138.659 1.008 138.683 1.032 ;
    END
  END rw0_wd_in[506]
  PIN rw0_wd_in[507]
    DIRECTION INPUT ;
    USE SIGNAL ;
    SHAPE ABUTMENT ;
    PORT
      LAYER M4_m ;
      RECT 138.659 1.056 138.683 1.08 ;
    END
  END rw0_wd_in[507]
  PIN rw0_wd_in[508]
    DIRECTION INPUT ;
    USE SIGNAL ;
    SHAPE ABUTMENT ;
    PORT
      LAYER M4_m ;
      RECT 138.659 1.104 138.683 1.128 ;
    END
  END rw0_wd_in[508]
  PIN rw0_wd_in[509]
    DIRECTION INPUT ;
    USE SIGNAL ;
    SHAPE ABUTMENT ;
    PORT
      LAYER M4_m ;
      RECT 138.659 1.152 138.683 1.176 ;
    END
  END rw0_wd_in[509]
  PIN rw0_wd_in[510]
    DIRECTION INPUT ;
    USE SIGNAL ;
    SHAPE ABUTMENT ;
    PORT
      LAYER M4_m ;
      RECT 138.659 1.2 138.683 1.224 ;
    END
  END rw0_wd_in[510]
  PIN rw0_wd_in[511]
    DIRECTION INPUT ;
    USE SIGNAL ;
    SHAPE ABUTMENT ;
    PORT
      LAYER M4_m ;
      RECT 138.659 1.248 138.683 1.272 ;
    END
  END rw0_wd_in[511]
  PIN rw0_rd_out[0]
    DIRECTION OUTPUT ;
    USE SIGNAL ;
    SHAPE ABUTMENT ;
    PORT
      LAYER M4_m ;
      RECT 138.659 1.296 138.683 1.32 ;
    END
  END rw0_rd_out[0]
  PIN rw0_rd_out[1]
    DIRECTION OUTPUT ;
    USE SIGNAL ;
    SHAPE ABUTMENT ;
    PORT
      LAYER M4_m ;
      RECT 138.659 1.344 138.683 1.368 ;
    END
  END rw0_rd_out[1]
  PIN rw0_rd_out[2]
    DIRECTION OUTPUT ;
    USE SIGNAL ;
    SHAPE ABUTMENT ;
    PORT
      LAYER M4_m ;
      RECT 138.659 1.392 138.683 1.416 ;
    END
  END rw0_rd_out[2]
  PIN rw0_rd_out[3]
    DIRECTION OUTPUT ;
    USE SIGNAL ;
    SHAPE ABUTMENT ;
    PORT
      LAYER M4_m ;
      RECT 138.659 1.44 138.683 1.464 ;
    END
  END rw0_rd_out[3]
  PIN rw0_rd_out[4]
    DIRECTION OUTPUT ;
    USE SIGNAL ;
    SHAPE ABUTMENT ;
    PORT
      LAYER M4_m ;
      RECT 138.659 1.488 138.683 1.512 ;
    END
  END rw0_rd_out[4]
  PIN rw0_rd_out[5]
    DIRECTION OUTPUT ;
    USE SIGNAL ;
    SHAPE ABUTMENT ;
    PORT
      LAYER M4_m ;
      RECT 138.659 1.536 138.683 1.56 ;
    END
  END rw0_rd_out[5]
  PIN rw0_rd_out[6]
    DIRECTION OUTPUT ;
    USE SIGNAL ;
    SHAPE ABUTMENT ;
    PORT
      LAYER M4_m ;
      RECT 138.659 1.584 138.683 1.608 ;
    END
  END rw0_rd_out[6]
  PIN rw0_rd_out[7]
    DIRECTION OUTPUT ;
    USE SIGNAL ;
    SHAPE ABUTMENT ;
    PORT
      LAYER M4_m ;
      RECT 138.659 1.632 138.683 1.656 ;
    END
  END rw0_rd_out[7]
  PIN rw0_rd_out[8]
    DIRECTION OUTPUT ;
    USE SIGNAL ;
    SHAPE ABUTMENT ;
    PORT
      LAYER M4_m ;
      RECT 138.659 1.68 138.683 1.704 ;
    END
  END rw0_rd_out[8]
  PIN rw0_rd_out[9]
    DIRECTION OUTPUT ;
    USE SIGNAL ;
    SHAPE ABUTMENT ;
    PORT
      LAYER M4_m ;
      RECT 138.659 1.728 138.683 1.752 ;
    END
  END rw0_rd_out[9]
  PIN rw0_rd_out[10]
    DIRECTION OUTPUT ;
    USE SIGNAL ;
    SHAPE ABUTMENT ;
    PORT
      LAYER M4_m ;
      RECT 138.659 1.776 138.683 1.8 ;
    END
  END rw0_rd_out[10]
  PIN rw0_rd_out[11]
    DIRECTION OUTPUT ;
    USE SIGNAL ;
    SHAPE ABUTMENT ;
    PORT
      LAYER M4_m ;
      RECT 138.659 1.824 138.683 1.848 ;
    END
  END rw0_rd_out[11]
  PIN rw0_rd_out[12]
    DIRECTION OUTPUT ;
    USE SIGNAL ;
    SHAPE ABUTMENT ;
    PORT
      LAYER M4_m ;
      RECT 138.659 1.872 138.683 1.896 ;
    END
  END rw0_rd_out[12]
  PIN rw0_rd_out[13]
    DIRECTION OUTPUT ;
    USE SIGNAL ;
    SHAPE ABUTMENT ;
    PORT
      LAYER M4_m ;
      RECT 138.659 1.92 138.683 1.944 ;
    END
  END rw0_rd_out[13]
  PIN rw0_rd_out[14]
    DIRECTION OUTPUT ;
    USE SIGNAL ;
    SHAPE ABUTMENT ;
    PORT
      LAYER M4_m ;
      RECT 138.659 1.968 138.683 1.992 ;
    END
  END rw0_rd_out[14]
  PIN rw0_rd_out[15]
    DIRECTION OUTPUT ;
    USE SIGNAL ;
    SHAPE ABUTMENT ;
    PORT
      LAYER M4_m ;
      RECT 138.659 2.016 138.683 2.04 ;
    END
  END rw0_rd_out[15]
  PIN rw0_rd_out[16]
    DIRECTION OUTPUT ;
    USE SIGNAL ;
    SHAPE ABUTMENT ;
    PORT
      LAYER M4_m ;
      RECT 138.659 2.064 138.683 2.088 ;
    END
  END rw0_rd_out[16]
  PIN rw0_rd_out[17]
    DIRECTION OUTPUT ;
    USE SIGNAL ;
    SHAPE ABUTMENT ;
    PORT
      LAYER M4_m ;
      RECT 138.659 2.112 138.683 2.136 ;
    END
  END rw0_rd_out[17]
  PIN rw0_rd_out[18]
    DIRECTION OUTPUT ;
    USE SIGNAL ;
    SHAPE ABUTMENT ;
    PORT
      LAYER M4_m ;
      RECT 138.659 2.16 138.683 2.184 ;
    END
  END rw0_rd_out[18]
  PIN rw0_rd_out[19]
    DIRECTION OUTPUT ;
    USE SIGNAL ;
    SHAPE ABUTMENT ;
    PORT
      LAYER M4_m ;
      RECT 138.659 2.208 138.683 2.232 ;
    END
  END rw0_rd_out[19]
  PIN rw0_rd_out[20]
    DIRECTION OUTPUT ;
    USE SIGNAL ;
    SHAPE ABUTMENT ;
    PORT
      LAYER M4_m ;
      RECT 138.659 2.256 138.683 2.28 ;
    END
  END rw0_rd_out[20]
  PIN rw0_rd_out[21]
    DIRECTION OUTPUT ;
    USE SIGNAL ;
    SHAPE ABUTMENT ;
    PORT
      LAYER M4_m ;
      RECT 138.659 2.304 138.683 2.328 ;
    END
  END rw0_rd_out[21]
  PIN rw0_rd_out[22]
    DIRECTION OUTPUT ;
    USE SIGNAL ;
    SHAPE ABUTMENT ;
    PORT
      LAYER M4_m ;
      RECT 138.659 2.352 138.683 2.376 ;
    END
  END rw0_rd_out[22]
  PIN rw0_rd_out[23]
    DIRECTION OUTPUT ;
    USE SIGNAL ;
    SHAPE ABUTMENT ;
    PORT
      LAYER M4_m ;
      RECT 138.659 2.4 138.683 2.424 ;
    END
  END rw0_rd_out[23]
  PIN rw0_rd_out[24]
    DIRECTION OUTPUT ;
    USE SIGNAL ;
    SHAPE ABUTMENT ;
    PORT
      LAYER M4_m ;
      RECT 138.659 2.448 138.683 2.472 ;
    END
  END rw0_rd_out[24]
  PIN rw0_rd_out[25]
    DIRECTION OUTPUT ;
    USE SIGNAL ;
    SHAPE ABUTMENT ;
    PORT
      LAYER M4_m ;
      RECT 138.659 2.496 138.683 2.52 ;
    END
  END rw0_rd_out[25]
  PIN rw0_rd_out[26]
    DIRECTION OUTPUT ;
    USE SIGNAL ;
    SHAPE ABUTMENT ;
    PORT
      LAYER M4_m ;
      RECT 138.659 2.544 138.683 2.568 ;
    END
  END rw0_rd_out[26]
  PIN rw0_rd_out[27]
    DIRECTION OUTPUT ;
    USE SIGNAL ;
    SHAPE ABUTMENT ;
    PORT
      LAYER M4_m ;
      RECT 138.659 2.592 138.683 2.616 ;
    END
  END rw0_rd_out[27]
  PIN rw0_rd_out[28]
    DIRECTION OUTPUT ;
    USE SIGNAL ;
    SHAPE ABUTMENT ;
    PORT
      LAYER M4_m ;
      RECT 138.659 2.64 138.683 2.664 ;
    END
  END rw0_rd_out[28]
  PIN rw0_rd_out[29]
    DIRECTION OUTPUT ;
    USE SIGNAL ;
    SHAPE ABUTMENT ;
    PORT
      LAYER M4_m ;
      RECT 138.659 2.688 138.683 2.712 ;
    END
  END rw0_rd_out[29]
  PIN rw0_rd_out[30]
    DIRECTION OUTPUT ;
    USE SIGNAL ;
    SHAPE ABUTMENT ;
    PORT
      LAYER M4_m ;
      RECT 138.659 2.736 138.683 2.76 ;
    END
  END rw0_rd_out[30]
  PIN rw0_rd_out[31]
    DIRECTION OUTPUT ;
    USE SIGNAL ;
    SHAPE ABUTMENT ;
    PORT
      LAYER M4_m ;
      RECT 138.659 2.784 138.683 2.808 ;
    END
  END rw0_rd_out[31]
  PIN rw0_rd_out[32]
    DIRECTION OUTPUT ;
    USE SIGNAL ;
    SHAPE ABUTMENT ;
    PORT
      LAYER M4_m ;
      RECT 138.659 2.832 138.683 2.856 ;
    END
  END rw0_rd_out[32]
  PIN rw0_rd_out[33]
    DIRECTION OUTPUT ;
    USE SIGNAL ;
    SHAPE ABUTMENT ;
    PORT
      LAYER M4_m ;
      RECT 138.659 2.88 138.683 2.904 ;
    END
  END rw0_rd_out[33]
  PIN rw0_rd_out[34]
    DIRECTION OUTPUT ;
    USE SIGNAL ;
    SHAPE ABUTMENT ;
    PORT
      LAYER M4_m ;
      RECT 138.659 2.928 138.683 2.952 ;
    END
  END rw0_rd_out[34]
  PIN rw0_rd_out[35]
    DIRECTION OUTPUT ;
    USE SIGNAL ;
    SHAPE ABUTMENT ;
    PORT
      LAYER M4_m ;
      RECT 138.659 2.976 138.683 3 ;
    END
  END rw0_rd_out[35]
  PIN rw0_rd_out[36]
    DIRECTION OUTPUT ;
    USE SIGNAL ;
    SHAPE ABUTMENT ;
    PORT
      LAYER M4_m ;
      RECT 138.659 3.024 138.683 3.048 ;
    END
  END rw0_rd_out[36]
  PIN rw0_rd_out[37]
    DIRECTION OUTPUT ;
    USE SIGNAL ;
    SHAPE ABUTMENT ;
    PORT
      LAYER M4_m ;
      RECT 138.659 3.072 138.683 3.096 ;
    END
  END rw0_rd_out[37]
  PIN rw0_rd_out[38]
    DIRECTION OUTPUT ;
    USE SIGNAL ;
    SHAPE ABUTMENT ;
    PORT
      LAYER M4_m ;
      RECT 138.659 3.12 138.683 3.144 ;
    END
  END rw0_rd_out[38]
  PIN rw0_rd_out[39]
    DIRECTION OUTPUT ;
    USE SIGNAL ;
    SHAPE ABUTMENT ;
    PORT
      LAYER M4_m ;
      RECT 138.659 3.168 138.683 3.192 ;
    END
  END rw0_rd_out[39]
  PIN rw0_rd_out[40]
    DIRECTION OUTPUT ;
    USE SIGNAL ;
    SHAPE ABUTMENT ;
    PORT
      LAYER M4_m ;
      RECT 138.659 3.216 138.683 3.24 ;
    END
  END rw0_rd_out[40]
  PIN rw0_rd_out[41]
    DIRECTION OUTPUT ;
    USE SIGNAL ;
    SHAPE ABUTMENT ;
    PORT
      LAYER M4_m ;
      RECT 138.659 3.264 138.683 3.288 ;
    END
  END rw0_rd_out[41]
  PIN rw0_rd_out[42]
    DIRECTION OUTPUT ;
    USE SIGNAL ;
    SHAPE ABUTMENT ;
    PORT
      LAYER M4_m ;
      RECT 138.659 3.312 138.683 3.336 ;
    END
  END rw0_rd_out[42]
  PIN rw0_rd_out[43]
    DIRECTION OUTPUT ;
    USE SIGNAL ;
    SHAPE ABUTMENT ;
    PORT
      LAYER M4_m ;
      RECT 138.659 3.36 138.683 3.384 ;
    END
  END rw0_rd_out[43]
  PIN rw0_rd_out[44]
    DIRECTION OUTPUT ;
    USE SIGNAL ;
    SHAPE ABUTMENT ;
    PORT
      LAYER M4_m ;
      RECT 138.659 3.408 138.683 3.432 ;
    END
  END rw0_rd_out[44]
  PIN rw0_rd_out[45]
    DIRECTION OUTPUT ;
    USE SIGNAL ;
    SHAPE ABUTMENT ;
    PORT
      LAYER M4_m ;
      RECT 138.659 3.456 138.683 3.48 ;
    END
  END rw0_rd_out[45]
  PIN rw0_rd_out[46]
    DIRECTION OUTPUT ;
    USE SIGNAL ;
    SHAPE ABUTMENT ;
    PORT
      LAYER M4_m ;
      RECT 138.659 3.504 138.683 3.528 ;
    END
  END rw0_rd_out[46]
  PIN rw0_rd_out[47]
    DIRECTION OUTPUT ;
    USE SIGNAL ;
    SHAPE ABUTMENT ;
    PORT
      LAYER M4_m ;
      RECT 138.659 3.552 138.683 3.576 ;
    END
  END rw0_rd_out[47]
  PIN rw0_rd_out[48]
    DIRECTION OUTPUT ;
    USE SIGNAL ;
    SHAPE ABUTMENT ;
    PORT
      LAYER M4_m ;
      RECT 138.659 3.6 138.683 3.624 ;
    END
  END rw0_rd_out[48]
  PIN rw0_rd_out[49]
    DIRECTION OUTPUT ;
    USE SIGNAL ;
    SHAPE ABUTMENT ;
    PORT
      LAYER M4_m ;
      RECT 138.659 3.648 138.683 3.672 ;
    END
  END rw0_rd_out[49]
  PIN rw0_rd_out[50]
    DIRECTION OUTPUT ;
    USE SIGNAL ;
    SHAPE ABUTMENT ;
    PORT
      LAYER M4_m ;
      RECT 138.659 3.696 138.683 3.72 ;
    END
  END rw0_rd_out[50]
  PIN rw0_rd_out[51]
    DIRECTION OUTPUT ;
    USE SIGNAL ;
    SHAPE ABUTMENT ;
    PORT
      LAYER M4_m ;
      RECT 138.659 3.744 138.683 3.768 ;
    END
  END rw0_rd_out[51]
  PIN rw0_rd_out[52]
    DIRECTION OUTPUT ;
    USE SIGNAL ;
    SHAPE ABUTMENT ;
    PORT
      LAYER M4_m ;
      RECT 138.659 3.792 138.683 3.816 ;
    END
  END rw0_rd_out[52]
  PIN rw0_rd_out[53]
    DIRECTION OUTPUT ;
    USE SIGNAL ;
    SHAPE ABUTMENT ;
    PORT
      LAYER M4_m ;
      RECT 138.659 3.84 138.683 3.864 ;
    END
  END rw0_rd_out[53]
  PIN rw0_rd_out[54]
    DIRECTION OUTPUT ;
    USE SIGNAL ;
    SHAPE ABUTMENT ;
    PORT
      LAYER M4_m ;
      RECT 138.659 3.888 138.683 3.912 ;
    END
  END rw0_rd_out[54]
  PIN rw0_rd_out[55]
    DIRECTION OUTPUT ;
    USE SIGNAL ;
    SHAPE ABUTMENT ;
    PORT
      LAYER M4_m ;
      RECT 138.659 3.936 138.683 3.96 ;
    END
  END rw0_rd_out[55]
  PIN rw0_rd_out[56]
    DIRECTION OUTPUT ;
    USE SIGNAL ;
    SHAPE ABUTMENT ;
    PORT
      LAYER M4_m ;
      RECT 138.659 3.984 138.683 4.008 ;
    END
  END rw0_rd_out[56]
  PIN rw0_rd_out[57]
    DIRECTION OUTPUT ;
    USE SIGNAL ;
    SHAPE ABUTMENT ;
    PORT
      LAYER M4_m ;
      RECT 138.659 4.032 138.683 4.056 ;
    END
  END rw0_rd_out[57]
  PIN rw0_rd_out[58]
    DIRECTION OUTPUT ;
    USE SIGNAL ;
    SHAPE ABUTMENT ;
    PORT
      LAYER M4_m ;
      RECT 138.659 4.08 138.683 4.104 ;
    END
  END rw0_rd_out[58]
  PIN rw0_rd_out[59]
    DIRECTION OUTPUT ;
    USE SIGNAL ;
    SHAPE ABUTMENT ;
    PORT
      LAYER M4_m ;
      RECT 138.659 4.128 138.683 4.152 ;
    END
  END rw0_rd_out[59]
  PIN rw0_rd_out[60]
    DIRECTION OUTPUT ;
    USE SIGNAL ;
    SHAPE ABUTMENT ;
    PORT
      LAYER M4_m ;
      RECT 138.659 4.176 138.683 4.2 ;
    END
  END rw0_rd_out[60]
  PIN rw0_rd_out[61]
    DIRECTION OUTPUT ;
    USE SIGNAL ;
    SHAPE ABUTMENT ;
    PORT
      LAYER M4_m ;
      RECT 138.659 4.224 138.683 4.248 ;
    END
  END rw0_rd_out[61]
  PIN rw0_rd_out[62]
    DIRECTION OUTPUT ;
    USE SIGNAL ;
    SHAPE ABUTMENT ;
    PORT
      LAYER M4_m ;
      RECT 138.659 4.272 138.683 4.296 ;
    END
  END rw0_rd_out[62]
  PIN rw0_rd_out[63]
    DIRECTION OUTPUT ;
    USE SIGNAL ;
    SHAPE ABUTMENT ;
    PORT
      LAYER M4_m ;
      RECT 138.659 4.32 138.683 4.344 ;
    END
  END rw0_rd_out[63]
  PIN rw0_rd_out[64]
    DIRECTION OUTPUT ;
    USE SIGNAL ;
    SHAPE ABUTMENT ;
    PORT
      LAYER M4_m ;
      RECT 138.659 4.368 138.683 4.392 ;
    END
  END rw0_rd_out[64]
  PIN rw0_rd_out[65]
    DIRECTION OUTPUT ;
    USE SIGNAL ;
    SHAPE ABUTMENT ;
    PORT
      LAYER M4_m ;
      RECT 138.659 4.416 138.683 4.44 ;
    END
  END rw0_rd_out[65]
  PIN rw0_rd_out[66]
    DIRECTION OUTPUT ;
    USE SIGNAL ;
    SHAPE ABUTMENT ;
    PORT
      LAYER M4_m ;
      RECT 138.659 4.464 138.683 4.488 ;
    END
  END rw0_rd_out[66]
  PIN rw0_rd_out[67]
    DIRECTION OUTPUT ;
    USE SIGNAL ;
    SHAPE ABUTMENT ;
    PORT
      LAYER M4_m ;
      RECT 138.659 4.512 138.683 4.536 ;
    END
  END rw0_rd_out[67]
  PIN rw0_rd_out[68]
    DIRECTION OUTPUT ;
    USE SIGNAL ;
    SHAPE ABUTMENT ;
    PORT
      LAYER M4_m ;
      RECT 138.659 4.56 138.683 4.584 ;
    END
  END rw0_rd_out[68]
  PIN rw0_rd_out[69]
    DIRECTION OUTPUT ;
    USE SIGNAL ;
    SHAPE ABUTMENT ;
    PORT
      LAYER M4_m ;
      RECT 138.659 4.608 138.683 4.632 ;
    END
  END rw0_rd_out[69]
  PIN rw0_rd_out[70]
    DIRECTION OUTPUT ;
    USE SIGNAL ;
    SHAPE ABUTMENT ;
    PORT
      LAYER M4_m ;
      RECT 138.659 4.656 138.683 4.68 ;
    END
  END rw0_rd_out[70]
  PIN rw0_rd_out[71]
    DIRECTION OUTPUT ;
    USE SIGNAL ;
    SHAPE ABUTMENT ;
    PORT
      LAYER M4_m ;
      RECT 138.659 4.704 138.683 4.728 ;
    END
  END rw0_rd_out[71]
  PIN rw0_rd_out[72]
    DIRECTION OUTPUT ;
    USE SIGNAL ;
    SHAPE ABUTMENT ;
    PORT
      LAYER M4_m ;
      RECT 138.659 4.752 138.683 4.776 ;
    END
  END rw0_rd_out[72]
  PIN rw0_rd_out[73]
    DIRECTION OUTPUT ;
    USE SIGNAL ;
    SHAPE ABUTMENT ;
    PORT
      LAYER M4_m ;
      RECT 138.659 4.8 138.683 4.824 ;
    END
  END rw0_rd_out[73]
  PIN rw0_rd_out[74]
    DIRECTION OUTPUT ;
    USE SIGNAL ;
    SHAPE ABUTMENT ;
    PORT
      LAYER M4_m ;
      RECT 138.659 4.848 138.683 4.872 ;
    END
  END rw0_rd_out[74]
  PIN rw0_rd_out[75]
    DIRECTION OUTPUT ;
    USE SIGNAL ;
    SHAPE ABUTMENT ;
    PORT
      LAYER M4_m ;
      RECT 138.659 4.896 138.683 4.92 ;
    END
  END rw0_rd_out[75]
  PIN rw0_rd_out[76]
    DIRECTION OUTPUT ;
    USE SIGNAL ;
    SHAPE ABUTMENT ;
    PORT
      LAYER M4_m ;
      RECT 138.659 4.944 138.683 4.968 ;
    END
  END rw0_rd_out[76]
  PIN rw0_rd_out[77]
    DIRECTION OUTPUT ;
    USE SIGNAL ;
    SHAPE ABUTMENT ;
    PORT
      LAYER M4_m ;
      RECT 138.659 4.992 138.683 5.016 ;
    END
  END rw0_rd_out[77]
  PIN rw0_rd_out[78]
    DIRECTION OUTPUT ;
    USE SIGNAL ;
    SHAPE ABUTMENT ;
    PORT
      LAYER M4_m ;
      RECT 138.659 5.04 138.683 5.064 ;
    END
  END rw0_rd_out[78]
  PIN rw0_rd_out[79]
    DIRECTION OUTPUT ;
    USE SIGNAL ;
    SHAPE ABUTMENT ;
    PORT
      LAYER M4_m ;
      RECT 138.659 5.088 138.683 5.112 ;
    END
  END rw0_rd_out[79]
  PIN rw0_rd_out[80]
    DIRECTION OUTPUT ;
    USE SIGNAL ;
    SHAPE ABUTMENT ;
    PORT
      LAYER M4_m ;
      RECT 138.659 5.136 138.683 5.16 ;
    END
  END rw0_rd_out[80]
  PIN rw0_rd_out[81]
    DIRECTION OUTPUT ;
    USE SIGNAL ;
    SHAPE ABUTMENT ;
    PORT
      LAYER M4_m ;
      RECT 138.659 5.184 138.683 5.208 ;
    END
  END rw0_rd_out[81]
  PIN rw0_rd_out[82]
    DIRECTION OUTPUT ;
    USE SIGNAL ;
    SHAPE ABUTMENT ;
    PORT
      LAYER M4_m ;
      RECT 138.659 5.232 138.683 5.256 ;
    END
  END rw0_rd_out[82]
  PIN rw0_rd_out[83]
    DIRECTION OUTPUT ;
    USE SIGNAL ;
    SHAPE ABUTMENT ;
    PORT
      LAYER M4_m ;
      RECT 138.659 5.28 138.683 5.304 ;
    END
  END rw0_rd_out[83]
  PIN rw0_rd_out[84]
    DIRECTION OUTPUT ;
    USE SIGNAL ;
    SHAPE ABUTMENT ;
    PORT
      LAYER M4_m ;
      RECT 138.659 5.328 138.683 5.352 ;
    END
  END rw0_rd_out[84]
  PIN rw0_rd_out[85]
    DIRECTION OUTPUT ;
    USE SIGNAL ;
    SHAPE ABUTMENT ;
    PORT
      LAYER M4_m ;
      RECT 138.659 5.376 138.683 5.4 ;
    END
  END rw0_rd_out[85]
  PIN rw0_rd_out[86]
    DIRECTION OUTPUT ;
    USE SIGNAL ;
    SHAPE ABUTMENT ;
    PORT
      LAYER M4_m ;
      RECT 138.659 5.424 138.683 5.448 ;
    END
  END rw0_rd_out[86]
  PIN rw0_rd_out[87]
    DIRECTION OUTPUT ;
    USE SIGNAL ;
    SHAPE ABUTMENT ;
    PORT
      LAYER M4_m ;
      RECT 138.659 5.472 138.683 5.496 ;
    END
  END rw0_rd_out[87]
  PIN rw0_rd_out[88]
    DIRECTION OUTPUT ;
    USE SIGNAL ;
    SHAPE ABUTMENT ;
    PORT
      LAYER M4_m ;
      RECT 138.659 5.52 138.683 5.544 ;
    END
  END rw0_rd_out[88]
  PIN rw0_rd_out[89]
    DIRECTION OUTPUT ;
    USE SIGNAL ;
    SHAPE ABUTMENT ;
    PORT
      LAYER M4_m ;
      RECT 138.659 5.568 138.683 5.592 ;
    END
  END rw0_rd_out[89]
  PIN rw0_rd_out[90]
    DIRECTION OUTPUT ;
    USE SIGNAL ;
    SHAPE ABUTMENT ;
    PORT
      LAYER M4_m ;
      RECT 138.659 5.616 138.683 5.64 ;
    END
  END rw0_rd_out[90]
  PIN rw0_rd_out[91]
    DIRECTION OUTPUT ;
    USE SIGNAL ;
    SHAPE ABUTMENT ;
    PORT
      LAYER M4_m ;
      RECT 138.659 5.664 138.683 5.688 ;
    END
  END rw0_rd_out[91]
  PIN rw0_rd_out[92]
    DIRECTION OUTPUT ;
    USE SIGNAL ;
    SHAPE ABUTMENT ;
    PORT
      LAYER M4_m ;
      RECT 138.659 5.712 138.683 5.736 ;
    END
  END rw0_rd_out[92]
  PIN rw0_rd_out[93]
    DIRECTION OUTPUT ;
    USE SIGNAL ;
    SHAPE ABUTMENT ;
    PORT
      LAYER M4_m ;
      RECT 138.659 5.76 138.683 5.784 ;
    END
  END rw0_rd_out[93]
  PIN rw0_rd_out[94]
    DIRECTION OUTPUT ;
    USE SIGNAL ;
    SHAPE ABUTMENT ;
    PORT
      LAYER M4_m ;
      RECT 138.659 5.808 138.683 5.832 ;
    END
  END rw0_rd_out[94]
  PIN rw0_rd_out[95]
    DIRECTION OUTPUT ;
    USE SIGNAL ;
    SHAPE ABUTMENT ;
    PORT
      LAYER M4_m ;
      RECT 138.659 5.856 138.683 5.88 ;
    END
  END rw0_rd_out[95]
  PIN rw0_rd_out[96]
    DIRECTION OUTPUT ;
    USE SIGNAL ;
    SHAPE ABUTMENT ;
    PORT
      LAYER M4_m ;
      RECT 138.659 5.904 138.683 5.928 ;
    END
  END rw0_rd_out[96]
  PIN rw0_rd_out[97]
    DIRECTION OUTPUT ;
    USE SIGNAL ;
    SHAPE ABUTMENT ;
    PORT
      LAYER M4_m ;
      RECT 138.659 5.952 138.683 5.976 ;
    END
  END rw0_rd_out[97]
  PIN rw0_rd_out[98]
    DIRECTION OUTPUT ;
    USE SIGNAL ;
    SHAPE ABUTMENT ;
    PORT
      LAYER M4_m ;
      RECT 138.659 6 138.683 6.024 ;
    END
  END rw0_rd_out[98]
  PIN rw0_rd_out[99]
    DIRECTION OUTPUT ;
    USE SIGNAL ;
    SHAPE ABUTMENT ;
    PORT
      LAYER M4_m ;
      RECT 138.659 6.048 138.683 6.072 ;
    END
  END rw0_rd_out[99]
  PIN rw0_rd_out[100]
    DIRECTION OUTPUT ;
    USE SIGNAL ;
    SHAPE ABUTMENT ;
    PORT
      LAYER M4_m ;
      RECT 138.659 6.096 138.683 6.12 ;
    END
  END rw0_rd_out[100]
  PIN rw0_rd_out[101]
    DIRECTION OUTPUT ;
    USE SIGNAL ;
    SHAPE ABUTMENT ;
    PORT
      LAYER M4_m ;
      RECT 138.659 6.144 138.683 6.168 ;
    END
  END rw0_rd_out[101]
  PIN rw0_rd_out[102]
    DIRECTION OUTPUT ;
    USE SIGNAL ;
    SHAPE ABUTMENT ;
    PORT
      LAYER M4_m ;
      RECT 138.659 6.192 138.683 6.216 ;
    END
  END rw0_rd_out[102]
  PIN rw0_rd_out[103]
    DIRECTION OUTPUT ;
    USE SIGNAL ;
    SHAPE ABUTMENT ;
    PORT
      LAYER M4_m ;
      RECT 138.659 6.24 138.683 6.264 ;
    END
  END rw0_rd_out[103]
  PIN rw0_rd_out[104]
    DIRECTION OUTPUT ;
    USE SIGNAL ;
    SHAPE ABUTMENT ;
    PORT
      LAYER M4_m ;
      RECT 138.659 6.288 138.683 6.312 ;
    END
  END rw0_rd_out[104]
  PIN rw0_rd_out[105]
    DIRECTION OUTPUT ;
    USE SIGNAL ;
    SHAPE ABUTMENT ;
    PORT
      LAYER M4_m ;
      RECT 138.659 6.336 138.683 6.36 ;
    END
  END rw0_rd_out[105]
  PIN rw0_rd_out[106]
    DIRECTION OUTPUT ;
    USE SIGNAL ;
    SHAPE ABUTMENT ;
    PORT
      LAYER M4_m ;
      RECT 138.659 6.384 138.683 6.408 ;
    END
  END rw0_rd_out[106]
  PIN rw0_rd_out[107]
    DIRECTION OUTPUT ;
    USE SIGNAL ;
    SHAPE ABUTMENT ;
    PORT
      LAYER M4_m ;
      RECT 138.659 6.432 138.683 6.456 ;
    END
  END rw0_rd_out[107]
  PIN rw0_rd_out[108]
    DIRECTION OUTPUT ;
    USE SIGNAL ;
    SHAPE ABUTMENT ;
    PORT
      LAYER M4_m ;
      RECT 138.659 6.48 138.683 6.504 ;
    END
  END rw0_rd_out[108]
  PIN rw0_rd_out[109]
    DIRECTION OUTPUT ;
    USE SIGNAL ;
    SHAPE ABUTMENT ;
    PORT
      LAYER M4_m ;
      RECT 138.659 6.528 138.683 6.552 ;
    END
  END rw0_rd_out[109]
  PIN rw0_rd_out[110]
    DIRECTION OUTPUT ;
    USE SIGNAL ;
    SHAPE ABUTMENT ;
    PORT
      LAYER M4_m ;
      RECT 138.659 6.576 138.683 6.6 ;
    END
  END rw0_rd_out[110]
  PIN rw0_rd_out[111]
    DIRECTION OUTPUT ;
    USE SIGNAL ;
    SHAPE ABUTMENT ;
    PORT
      LAYER M4_m ;
      RECT 138.659 6.624 138.683 6.648 ;
    END
  END rw0_rd_out[111]
  PIN rw0_rd_out[112]
    DIRECTION OUTPUT ;
    USE SIGNAL ;
    SHAPE ABUTMENT ;
    PORT
      LAYER M4_m ;
      RECT 138.659 6.672 138.683 6.696 ;
    END
  END rw0_rd_out[112]
  PIN rw0_rd_out[113]
    DIRECTION OUTPUT ;
    USE SIGNAL ;
    SHAPE ABUTMENT ;
    PORT
      LAYER M4_m ;
      RECT 138.659 6.72 138.683 6.744 ;
    END
  END rw0_rd_out[113]
  PIN rw0_rd_out[114]
    DIRECTION OUTPUT ;
    USE SIGNAL ;
    SHAPE ABUTMENT ;
    PORT
      LAYER M4_m ;
      RECT 138.659 6.768 138.683 6.792 ;
    END
  END rw0_rd_out[114]
  PIN rw0_rd_out[115]
    DIRECTION OUTPUT ;
    USE SIGNAL ;
    SHAPE ABUTMENT ;
    PORT
      LAYER M4_m ;
      RECT 138.659 6.816 138.683 6.84 ;
    END
  END rw0_rd_out[115]
  PIN rw0_rd_out[116]
    DIRECTION OUTPUT ;
    USE SIGNAL ;
    SHAPE ABUTMENT ;
    PORT
      LAYER M4_m ;
      RECT 138.659 6.864 138.683 6.888 ;
    END
  END rw0_rd_out[116]
  PIN rw0_rd_out[117]
    DIRECTION OUTPUT ;
    USE SIGNAL ;
    SHAPE ABUTMENT ;
    PORT
      LAYER M4_m ;
      RECT 138.659 6.912 138.683 6.936 ;
    END
  END rw0_rd_out[117]
  PIN rw0_rd_out[118]
    DIRECTION OUTPUT ;
    USE SIGNAL ;
    SHAPE ABUTMENT ;
    PORT
      LAYER M4_m ;
      RECT 138.659 6.96 138.683 6.984 ;
    END
  END rw0_rd_out[118]
  PIN rw0_rd_out[119]
    DIRECTION OUTPUT ;
    USE SIGNAL ;
    SHAPE ABUTMENT ;
    PORT
      LAYER M4_m ;
      RECT 138.659 7.008 138.683 7.032 ;
    END
  END rw0_rd_out[119]
  PIN rw0_rd_out[120]
    DIRECTION OUTPUT ;
    USE SIGNAL ;
    SHAPE ABUTMENT ;
    PORT
      LAYER M4_m ;
      RECT 138.659 7.056 138.683 7.08 ;
    END
  END rw0_rd_out[120]
  PIN rw0_rd_out[121]
    DIRECTION OUTPUT ;
    USE SIGNAL ;
    SHAPE ABUTMENT ;
    PORT
      LAYER M4_m ;
      RECT 138.659 7.104 138.683 7.128 ;
    END
  END rw0_rd_out[121]
  PIN rw0_rd_out[122]
    DIRECTION OUTPUT ;
    USE SIGNAL ;
    SHAPE ABUTMENT ;
    PORT
      LAYER M4_m ;
      RECT 138.659 7.152 138.683 7.176 ;
    END
  END rw0_rd_out[122]
  PIN rw0_rd_out[123]
    DIRECTION OUTPUT ;
    USE SIGNAL ;
    SHAPE ABUTMENT ;
    PORT
      LAYER M4_m ;
      RECT 138.659 7.2 138.683 7.224 ;
    END
  END rw0_rd_out[123]
  PIN rw0_rd_out[124]
    DIRECTION OUTPUT ;
    USE SIGNAL ;
    SHAPE ABUTMENT ;
    PORT
      LAYER M4_m ;
      RECT 138.659 7.248 138.683 7.272 ;
    END
  END rw0_rd_out[124]
  PIN rw0_rd_out[125]
    DIRECTION OUTPUT ;
    USE SIGNAL ;
    SHAPE ABUTMENT ;
    PORT
      LAYER M4_m ;
      RECT 138.659 7.296 138.683 7.32 ;
    END
  END rw0_rd_out[125]
  PIN rw0_rd_out[126]
    DIRECTION OUTPUT ;
    USE SIGNAL ;
    SHAPE ABUTMENT ;
    PORT
      LAYER M4_m ;
      RECT 138.659 7.344 138.683 7.368 ;
    END
  END rw0_rd_out[126]
  PIN rw0_rd_out[127]
    DIRECTION OUTPUT ;
    USE SIGNAL ;
    SHAPE ABUTMENT ;
    PORT
      LAYER M4_m ;
      RECT 138.659 7.392 138.683 7.416 ;
    END
  END rw0_rd_out[127]
  PIN rw0_rd_out[128]
    DIRECTION OUTPUT ;
    USE SIGNAL ;
    SHAPE ABUTMENT ;
    PORT
      LAYER M4_m ;
      RECT 138.659 7.44 138.683 7.464 ;
    END
  END rw0_rd_out[128]
  PIN rw0_rd_out[129]
    DIRECTION OUTPUT ;
    USE SIGNAL ;
    SHAPE ABUTMENT ;
    PORT
      LAYER M4_m ;
      RECT 138.659 7.488 138.683 7.512 ;
    END
  END rw0_rd_out[129]
  PIN rw0_rd_out[130]
    DIRECTION OUTPUT ;
    USE SIGNAL ;
    SHAPE ABUTMENT ;
    PORT
      LAYER M4_m ;
      RECT 138.659 7.536 138.683 7.56 ;
    END
  END rw0_rd_out[130]
  PIN rw0_rd_out[131]
    DIRECTION OUTPUT ;
    USE SIGNAL ;
    SHAPE ABUTMENT ;
    PORT
      LAYER M4_m ;
      RECT 138.659 7.584 138.683 7.608 ;
    END
  END rw0_rd_out[131]
  PIN rw0_rd_out[132]
    DIRECTION OUTPUT ;
    USE SIGNAL ;
    SHAPE ABUTMENT ;
    PORT
      LAYER M4_m ;
      RECT 138.659 7.632 138.683 7.656 ;
    END
  END rw0_rd_out[132]
  PIN rw0_rd_out[133]
    DIRECTION OUTPUT ;
    USE SIGNAL ;
    SHAPE ABUTMENT ;
    PORT
      LAYER M4_m ;
      RECT 138.659 7.68 138.683 7.704 ;
    END
  END rw0_rd_out[133]
  PIN rw0_rd_out[134]
    DIRECTION OUTPUT ;
    USE SIGNAL ;
    SHAPE ABUTMENT ;
    PORT
      LAYER M4_m ;
      RECT 138.659 7.728 138.683 7.752 ;
    END
  END rw0_rd_out[134]
  PIN rw0_rd_out[135]
    DIRECTION OUTPUT ;
    USE SIGNAL ;
    SHAPE ABUTMENT ;
    PORT
      LAYER M4_m ;
      RECT 138.659 7.776 138.683 7.8 ;
    END
  END rw0_rd_out[135]
  PIN rw0_rd_out[136]
    DIRECTION OUTPUT ;
    USE SIGNAL ;
    SHAPE ABUTMENT ;
    PORT
      LAYER M4_m ;
      RECT 138.659 7.824 138.683 7.848 ;
    END
  END rw0_rd_out[136]
  PIN rw0_rd_out[137]
    DIRECTION OUTPUT ;
    USE SIGNAL ;
    SHAPE ABUTMENT ;
    PORT
      LAYER M4_m ;
      RECT 138.659 7.872 138.683 7.896 ;
    END
  END rw0_rd_out[137]
  PIN rw0_rd_out[138]
    DIRECTION OUTPUT ;
    USE SIGNAL ;
    SHAPE ABUTMENT ;
    PORT
      LAYER M4_m ;
      RECT 138.659 7.92 138.683 7.944 ;
    END
  END rw0_rd_out[138]
  PIN rw0_rd_out[139]
    DIRECTION OUTPUT ;
    USE SIGNAL ;
    SHAPE ABUTMENT ;
    PORT
      LAYER M4_m ;
      RECT 138.659 7.968 138.683 7.992 ;
    END
  END rw0_rd_out[139]
  PIN rw0_rd_out[140]
    DIRECTION OUTPUT ;
    USE SIGNAL ;
    SHAPE ABUTMENT ;
    PORT
      LAYER M4_m ;
      RECT 138.659 8.016 138.683 8.04 ;
    END
  END rw0_rd_out[140]
  PIN rw0_rd_out[141]
    DIRECTION OUTPUT ;
    USE SIGNAL ;
    SHAPE ABUTMENT ;
    PORT
      LAYER M4_m ;
      RECT 138.659 8.064 138.683 8.088 ;
    END
  END rw0_rd_out[141]
  PIN rw0_rd_out[142]
    DIRECTION OUTPUT ;
    USE SIGNAL ;
    SHAPE ABUTMENT ;
    PORT
      LAYER M4_m ;
      RECT 138.659 8.112 138.683 8.136 ;
    END
  END rw0_rd_out[142]
  PIN rw0_rd_out[143]
    DIRECTION OUTPUT ;
    USE SIGNAL ;
    SHAPE ABUTMENT ;
    PORT
      LAYER M4_m ;
      RECT 138.659 8.16 138.683 8.184 ;
    END
  END rw0_rd_out[143]
  PIN rw0_rd_out[144]
    DIRECTION OUTPUT ;
    USE SIGNAL ;
    SHAPE ABUTMENT ;
    PORT
      LAYER M4_m ;
      RECT 138.659 8.208 138.683 8.232 ;
    END
  END rw0_rd_out[144]
  PIN rw0_rd_out[145]
    DIRECTION OUTPUT ;
    USE SIGNAL ;
    SHAPE ABUTMENT ;
    PORT
      LAYER M4_m ;
      RECT 138.659 8.256 138.683 8.28 ;
    END
  END rw0_rd_out[145]
  PIN rw0_rd_out[146]
    DIRECTION OUTPUT ;
    USE SIGNAL ;
    SHAPE ABUTMENT ;
    PORT
      LAYER M4_m ;
      RECT 138.659 8.304 138.683 8.328 ;
    END
  END rw0_rd_out[146]
  PIN rw0_rd_out[147]
    DIRECTION OUTPUT ;
    USE SIGNAL ;
    SHAPE ABUTMENT ;
    PORT
      LAYER M4_m ;
      RECT 138.659 8.352 138.683 8.376 ;
    END
  END rw0_rd_out[147]
  PIN rw0_rd_out[148]
    DIRECTION OUTPUT ;
    USE SIGNAL ;
    SHAPE ABUTMENT ;
    PORT
      LAYER M4_m ;
      RECT 138.659 8.4 138.683 8.424 ;
    END
  END rw0_rd_out[148]
  PIN rw0_rd_out[149]
    DIRECTION OUTPUT ;
    USE SIGNAL ;
    SHAPE ABUTMENT ;
    PORT
      LAYER M4_m ;
      RECT 138.659 8.448 138.683 8.472 ;
    END
  END rw0_rd_out[149]
  PIN rw0_rd_out[150]
    DIRECTION OUTPUT ;
    USE SIGNAL ;
    SHAPE ABUTMENT ;
    PORT
      LAYER M4_m ;
      RECT 138.659 8.496 138.683 8.52 ;
    END
  END rw0_rd_out[150]
  PIN rw0_rd_out[151]
    DIRECTION OUTPUT ;
    USE SIGNAL ;
    SHAPE ABUTMENT ;
    PORT
      LAYER M4_m ;
      RECT 138.659 8.544 138.683 8.568 ;
    END
  END rw0_rd_out[151]
  PIN rw0_rd_out[152]
    DIRECTION OUTPUT ;
    USE SIGNAL ;
    SHAPE ABUTMENT ;
    PORT
      LAYER M4_m ;
      RECT 138.659 8.592 138.683 8.616 ;
    END
  END rw0_rd_out[152]
  PIN rw0_rd_out[153]
    DIRECTION OUTPUT ;
    USE SIGNAL ;
    SHAPE ABUTMENT ;
    PORT
      LAYER M4_m ;
      RECT 138.659 8.64 138.683 8.664 ;
    END
  END rw0_rd_out[153]
  PIN rw0_rd_out[154]
    DIRECTION OUTPUT ;
    USE SIGNAL ;
    SHAPE ABUTMENT ;
    PORT
      LAYER M4_m ;
      RECT 138.659 8.688 138.683 8.712 ;
    END
  END rw0_rd_out[154]
  PIN rw0_rd_out[155]
    DIRECTION OUTPUT ;
    USE SIGNAL ;
    SHAPE ABUTMENT ;
    PORT
      LAYER M4_m ;
      RECT 138.659 8.736 138.683 8.76 ;
    END
  END rw0_rd_out[155]
  PIN rw0_rd_out[156]
    DIRECTION OUTPUT ;
    USE SIGNAL ;
    SHAPE ABUTMENT ;
    PORT
      LAYER M4_m ;
      RECT 138.659 8.784 138.683 8.808 ;
    END
  END rw0_rd_out[156]
  PIN rw0_rd_out[157]
    DIRECTION OUTPUT ;
    USE SIGNAL ;
    SHAPE ABUTMENT ;
    PORT
      LAYER M4_m ;
      RECT 138.659 8.832 138.683 8.856 ;
    END
  END rw0_rd_out[157]
  PIN rw0_rd_out[158]
    DIRECTION OUTPUT ;
    USE SIGNAL ;
    SHAPE ABUTMENT ;
    PORT
      LAYER M4_m ;
      RECT 138.659 8.88 138.683 8.904 ;
    END
  END rw0_rd_out[158]
  PIN rw0_rd_out[159]
    DIRECTION OUTPUT ;
    USE SIGNAL ;
    SHAPE ABUTMENT ;
    PORT
      LAYER M4_m ;
      RECT 138.659 8.928 138.683 8.952 ;
    END
  END rw0_rd_out[159]
  PIN rw0_rd_out[160]
    DIRECTION OUTPUT ;
    USE SIGNAL ;
    SHAPE ABUTMENT ;
    PORT
      LAYER M4_m ;
      RECT 138.659 8.976 138.683 9 ;
    END
  END rw0_rd_out[160]
  PIN rw0_rd_out[161]
    DIRECTION OUTPUT ;
    USE SIGNAL ;
    SHAPE ABUTMENT ;
    PORT
      LAYER M4_m ;
      RECT 138.659 9.024 138.683 9.048 ;
    END
  END rw0_rd_out[161]
  PIN rw0_rd_out[162]
    DIRECTION OUTPUT ;
    USE SIGNAL ;
    SHAPE ABUTMENT ;
    PORT
      LAYER M4_m ;
      RECT 138.659 9.072 138.683 9.096 ;
    END
  END rw0_rd_out[162]
  PIN rw0_rd_out[163]
    DIRECTION OUTPUT ;
    USE SIGNAL ;
    SHAPE ABUTMENT ;
    PORT
      LAYER M4_m ;
      RECT 138.659 9.12 138.683 9.144 ;
    END
  END rw0_rd_out[163]
  PIN rw0_rd_out[164]
    DIRECTION OUTPUT ;
    USE SIGNAL ;
    SHAPE ABUTMENT ;
    PORT
      LAYER M4_m ;
      RECT 138.659 9.168 138.683 9.192 ;
    END
  END rw0_rd_out[164]
  PIN rw0_rd_out[165]
    DIRECTION OUTPUT ;
    USE SIGNAL ;
    SHAPE ABUTMENT ;
    PORT
      LAYER M4_m ;
      RECT 138.659 9.216 138.683 9.24 ;
    END
  END rw0_rd_out[165]
  PIN rw0_rd_out[166]
    DIRECTION OUTPUT ;
    USE SIGNAL ;
    SHAPE ABUTMENT ;
    PORT
      LAYER M4_m ;
      RECT 138.659 9.264 138.683 9.288 ;
    END
  END rw0_rd_out[166]
  PIN rw0_rd_out[167]
    DIRECTION OUTPUT ;
    USE SIGNAL ;
    SHAPE ABUTMENT ;
    PORT
      LAYER M4_m ;
      RECT 138.659 9.312 138.683 9.336 ;
    END
  END rw0_rd_out[167]
  PIN rw0_rd_out[168]
    DIRECTION OUTPUT ;
    USE SIGNAL ;
    SHAPE ABUTMENT ;
    PORT
      LAYER M4_m ;
      RECT 138.659 9.36 138.683 9.384 ;
    END
  END rw0_rd_out[168]
  PIN rw0_rd_out[169]
    DIRECTION OUTPUT ;
    USE SIGNAL ;
    SHAPE ABUTMENT ;
    PORT
      LAYER M4_m ;
      RECT 138.659 9.408 138.683 9.432 ;
    END
  END rw0_rd_out[169]
  PIN rw0_rd_out[170]
    DIRECTION OUTPUT ;
    USE SIGNAL ;
    SHAPE ABUTMENT ;
    PORT
      LAYER M4_m ;
      RECT 138.659 9.456 138.683 9.48 ;
    END
  END rw0_rd_out[170]
  PIN rw0_rd_out[171]
    DIRECTION OUTPUT ;
    USE SIGNAL ;
    SHAPE ABUTMENT ;
    PORT
      LAYER M4_m ;
      RECT 138.659 9.504 138.683 9.528 ;
    END
  END rw0_rd_out[171]
  PIN rw0_rd_out[172]
    DIRECTION OUTPUT ;
    USE SIGNAL ;
    SHAPE ABUTMENT ;
    PORT
      LAYER M4_m ;
      RECT 138.659 9.552 138.683 9.576 ;
    END
  END rw0_rd_out[172]
  PIN rw0_rd_out[173]
    DIRECTION OUTPUT ;
    USE SIGNAL ;
    SHAPE ABUTMENT ;
    PORT
      LAYER M4_m ;
      RECT 138.659 9.6 138.683 9.624 ;
    END
  END rw0_rd_out[173]
  PIN rw0_rd_out[174]
    DIRECTION OUTPUT ;
    USE SIGNAL ;
    SHAPE ABUTMENT ;
    PORT
      LAYER M4_m ;
      RECT 138.659 9.648 138.683 9.672 ;
    END
  END rw0_rd_out[174]
  PIN rw0_rd_out[175]
    DIRECTION OUTPUT ;
    USE SIGNAL ;
    SHAPE ABUTMENT ;
    PORT
      LAYER M4_m ;
      RECT 138.659 9.696 138.683 9.72 ;
    END
  END rw0_rd_out[175]
  PIN rw0_rd_out[176]
    DIRECTION OUTPUT ;
    USE SIGNAL ;
    SHAPE ABUTMENT ;
    PORT
      LAYER M4_m ;
      RECT 138.659 9.744 138.683 9.768 ;
    END
  END rw0_rd_out[176]
  PIN rw0_rd_out[177]
    DIRECTION OUTPUT ;
    USE SIGNAL ;
    SHAPE ABUTMENT ;
    PORT
      LAYER M4_m ;
      RECT 138.659 9.792 138.683 9.816 ;
    END
  END rw0_rd_out[177]
  PIN rw0_rd_out[178]
    DIRECTION OUTPUT ;
    USE SIGNAL ;
    SHAPE ABUTMENT ;
    PORT
      LAYER M4_m ;
      RECT 138.659 9.84 138.683 9.864 ;
    END
  END rw0_rd_out[178]
  PIN rw0_rd_out[179]
    DIRECTION OUTPUT ;
    USE SIGNAL ;
    SHAPE ABUTMENT ;
    PORT
      LAYER M4_m ;
      RECT 138.659 9.888 138.683 9.912 ;
    END
  END rw0_rd_out[179]
  PIN rw0_rd_out[180]
    DIRECTION OUTPUT ;
    USE SIGNAL ;
    SHAPE ABUTMENT ;
    PORT
      LAYER M4_m ;
      RECT 138.659 9.936 138.683 9.96 ;
    END
  END rw0_rd_out[180]
  PIN rw0_rd_out[181]
    DIRECTION OUTPUT ;
    USE SIGNAL ;
    SHAPE ABUTMENT ;
    PORT
      LAYER M4_m ;
      RECT 138.659 9.984 138.683 10.008 ;
    END
  END rw0_rd_out[181]
  PIN rw0_rd_out[182]
    DIRECTION OUTPUT ;
    USE SIGNAL ;
    SHAPE ABUTMENT ;
    PORT
      LAYER M4_m ;
      RECT 138.659 10.032 138.683 10.056 ;
    END
  END rw0_rd_out[182]
  PIN rw0_rd_out[183]
    DIRECTION OUTPUT ;
    USE SIGNAL ;
    SHAPE ABUTMENT ;
    PORT
      LAYER M4_m ;
      RECT 138.659 10.08 138.683 10.104 ;
    END
  END rw0_rd_out[183]
  PIN rw0_rd_out[184]
    DIRECTION OUTPUT ;
    USE SIGNAL ;
    SHAPE ABUTMENT ;
    PORT
      LAYER M4_m ;
      RECT 138.659 10.128 138.683 10.152 ;
    END
  END rw0_rd_out[184]
  PIN rw0_rd_out[185]
    DIRECTION OUTPUT ;
    USE SIGNAL ;
    SHAPE ABUTMENT ;
    PORT
      LAYER M4_m ;
      RECT 138.659 10.176 138.683 10.2 ;
    END
  END rw0_rd_out[185]
  PIN rw0_rd_out[186]
    DIRECTION OUTPUT ;
    USE SIGNAL ;
    SHAPE ABUTMENT ;
    PORT
      LAYER M4_m ;
      RECT 138.659 10.224 138.683 10.248 ;
    END
  END rw0_rd_out[186]
  PIN rw0_rd_out[187]
    DIRECTION OUTPUT ;
    USE SIGNAL ;
    SHAPE ABUTMENT ;
    PORT
      LAYER M4_m ;
      RECT 138.659 10.272 138.683 10.296 ;
    END
  END rw0_rd_out[187]
  PIN rw0_rd_out[188]
    DIRECTION OUTPUT ;
    USE SIGNAL ;
    SHAPE ABUTMENT ;
    PORT
      LAYER M4_m ;
      RECT 138.659 10.32 138.683 10.344 ;
    END
  END rw0_rd_out[188]
  PIN rw0_rd_out[189]
    DIRECTION OUTPUT ;
    USE SIGNAL ;
    SHAPE ABUTMENT ;
    PORT
      LAYER M4_m ;
      RECT 138.659 10.368 138.683 10.392 ;
    END
  END rw0_rd_out[189]
  PIN rw0_rd_out[190]
    DIRECTION OUTPUT ;
    USE SIGNAL ;
    SHAPE ABUTMENT ;
    PORT
      LAYER M4_m ;
      RECT 138.659 10.416 138.683 10.44 ;
    END
  END rw0_rd_out[190]
  PIN rw0_rd_out[191]
    DIRECTION OUTPUT ;
    USE SIGNAL ;
    SHAPE ABUTMENT ;
    PORT
      LAYER M4_m ;
      RECT 138.659 10.464 138.683 10.488 ;
    END
  END rw0_rd_out[191]
  PIN rw0_rd_out[192]
    DIRECTION OUTPUT ;
    USE SIGNAL ;
    SHAPE ABUTMENT ;
    PORT
      LAYER M4_m ;
      RECT 138.659 10.512 138.683 10.536 ;
    END
  END rw0_rd_out[192]
  PIN rw0_rd_out[193]
    DIRECTION OUTPUT ;
    USE SIGNAL ;
    SHAPE ABUTMENT ;
    PORT
      LAYER M4_m ;
      RECT 138.659 10.56 138.683 10.584 ;
    END
  END rw0_rd_out[193]
  PIN rw0_rd_out[194]
    DIRECTION OUTPUT ;
    USE SIGNAL ;
    SHAPE ABUTMENT ;
    PORT
      LAYER M4_m ;
      RECT 138.659 10.608 138.683 10.632 ;
    END
  END rw0_rd_out[194]
  PIN rw0_rd_out[195]
    DIRECTION OUTPUT ;
    USE SIGNAL ;
    SHAPE ABUTMENT ;
    PORT
      LAYER M4_m ;
      RECT 138.659 10.656 138.683 10.68 ;
    END
  END rw0_rd_out[195]
  PIN rw0_rd_out[196]
    DIRECTION OUTPUT ;
    USE SIGNAL ;
    SHAPE ABUTMENT ;
    PORT
      LAYER M4_m ;
      RECT 138.659 10.704 138.683 10.728 ;
    END
  END rw0_rd_out[196]
  PIN rw0_rd_out[197]
    DIRECTION OUTPUT ;
    USE SIGNAL ;
    SHAPE ABUTMENT ;
    PORT
      LAYER M4_m ;
      RECT 138.659 10.752 138.683 10.776 ;
    END
  END rw0_rd_out[197]
  PIN rw0_rd_out[198]
    DIRECTION OUTPUT ;
    USE SIGNAL ;
    SHAPE ABUTMENT ;
    PORT
      LAYER M4_m ;
      RECT 138.659 10.8 138.683 10.824 ;
    END
  END rw0_rd_out[198]
  PIN rw0_rd_out[199]
    DIRECTION OUTPUT ;
    USE SIGNAL ;
    SHAPE ABUTMENT ;
    PORT
      LAYER M4_m ;
      RECT 138.659 10.848 138.683 10.872 ;
    END
  END rw0_rd_out[199]
  PIN rw0_rd_out[200]
    DIRECTION OUTPUT ;
    USE SIGNAL ;
    SHAPE ABUTMENT ;
    PORT
      LAYER M4_m ;
      RECT 138.659 10.896 138.683 10.92 ;
    END
  END rw0_rd_out[200]
  PIN rw0_rd_out[201]
    DIRECTION OUTPUT ;
    USE SIGNAL ;
    SHAPE ABUTMENT ;
    PORT
      LAYER M4_m ;
      RECT 138.659 10.944 138.683 10.968 ;
    END
  END rw0_rd_out[201]
  PIN rw0_rd_out[202]
    DIRECTION OUTPUT ;
    USE SIGNAL ;
    SHAPE ABUTMENT ;
    PORT
      LAYER M4_m ;
      RECT 138.659 10.992 138.683 11.016 ;
    END
  END rw0_rd_out[202]
  PIN rw0_rd_out[203]
    DIRECTION OUTPUT ;
    USE SIGNAL ;
    SHAPE ABUTMENT ;
    PORT
      LAYER M4_m ;
      RECT 138.659 11.04 138.683 11.064 ;
    END
  END rw0_rd_out[203]
  PIN rw0_rd_out[204]
    DIRECTION OUTPUT ;
    USE SIGNAL ;
    SHAPE ABUTMENT ;
    PORT
      LAYER M4_m ;
      RECT 138.659 11.088 138.683 11.112 ;
    END
  END rw0_rd_out[204]
  PIN rw0_rd_out[205]
    DIRECTION OUTPUT ;
    USE SIGNAL ;
    SHAPE ABUTMENT ;
    PORT
      LAYER M4_m ;
      RECT 138.659 11.136 138.683 11.16 ;
    END
  END rw0_rd_out[205]
  PIN rw0_rd_out[206]
    DIRECTION OUTPUT ;
    USE SIGNAL ;
    SHAPE ABUTMENT ;
    PORT
      LAYER M4_m ;
      RECT 138.659 11.184 138.683 11.208 ;
    END
  END rw0_rd_out[206]
  PIN rw0_rd_out[207]
    DIRECTION OUTPUT ;
    USE SIGNAL ;
    SHAPE ABUTMENT ;
    PORT
      LAYER M4_m ;
      RECT 138.659 11.232 138.683 11.256 ;
    END
  END rw0_rd_out[207]
  PIN rw0_rd_out[208]
    DIRECTION OUTPUT ;
    USE SIGNAL ;
    SHAPE ABUTMENT ;
    PORT
      LAYER M4_m ;
      RECT 138.659 11.28 138.683 11.304 ;
    END
  END rw0_rd_out[208]
  PIN rw0_rd_out[209]
    DIRECTION OUTPUT ;
    USE SIGNAL ;
    SHAPE ABUTMENT ;
    PORT
      LAYER M4_m ;
      RECT 138.659 11.328 138.683 11.352 ;
    END
  END rw0_rd_out[209]
  PIN rw0_rd_out[210]
    DIRECTION OUTPUT ;
    USE SIGNAL ;
    SHAPE ABUTMENT ;
    PORT
      LAYER M4_m ;
      RECT 138.659 11.376 138.683 11.4 ;
    END
  END rw0_rd_out[210]
  PIN rw0_rd_out[211]
    DIRECTION OUTPUT ;
    USE SIGNAL ;
    SHAPE ABUTMENT ;
    PORT
      LAYER M4_m ;
      RECT 138.659 11.424 138.683 11.448 ;
    END
  END rw0_rd_out[211]
  PIN rw0_rd_out[212]
    DIRECTION OUTPUT ;
    USE SIGNAL ;
    SHAPE ABUTMENT ;
    PORT
      LAYER M4_m ;
      RECT 138.659 11.472 138.683 11.496 ;
    END
  END rw0_rd_out[212]
  PIN rw0_rd_out[213]
    DIRECTION OUTPUT ;
    USE SIGNAL ;
    SHAPE ABUTMENT ;
    PORT
      LAYER M4_m ;
      RECT 138.659 11.52 138.683 11.544 ;
    END
  END rw0_rd_out[213]
  PIN rw0_rd_out[214]
    DIRECTION OUTPUT ;
    USE SIGNAL ;
    SHAPE ABUTMENT ;
    PORT
      LAYER M4_m ;
      RECT 138.659 11.568 138.683 11.592 ;
    END
  END rw0_rd_out[214]
  PIN rw0_rd_out[215]
    DIRECTION OUTPUT ;
    USE SIGNAL ;
    SHAPE ABUTMENT ;
    PORT
      LAYER M4_m ;
      RECT 138.659 11.616 138.683 11.64 ;
    END
  END rw0_rd_out[215]
  PIN rw0_rd_out[216]
    DIRECTION OUTPUT ;
    USE SIGNAL ;
    SHAPE ABUTMENT ;
    PORT
      LAYER M4_m ;
      RECT 138.659 11.664 138.683 11.688 ;
    END
  END rw0_rd_out[216]
  PIN rw0_rd_out[217]
    DIRECTION OUTPUT ;
    USE SIGNAL ;
    SHAPE ABUTMENT ;
    PORT
      LAYER M4_m ;
      RECT 138.659 11.712 138.683 11.736 ;
    END
  END rw0_rd_out[217]
  PIN rw0_rd_out[218]
    DIRECTION OUTPUT ;
    USE SIGNAL ;
    SHAPE ABUTMENT ;
    PORT
      LAYER M4_m ;
      RECT 138.659 11.76 138.683 11.784 ;
    END
  END rw0_rd_out[218]
  PIN rw0_rd_out[219]
    DIRECTION OUTPUT ;
    USE SIGNAL ;
    SHAPE ABUTMENT ;
    PORT
      LAYER M4_m ;
      RECT 138.659 11.808 138.683 11.832 ;
    END
  END rw0_rd_out[219]
  PIN rw0_rd_out[220]
    DIRECTION OUTPUT ;
    USE SIGNAL ;
    SHAPE ABUTMENT ;
    PORT
      LAYER M4_m ;
      RECT 138.659 11.856 138.683 11.88 ;
    END
  END rw0_rd_out[220]
  PIN rw0_rd_out[221]
    DIRECTION OUTPUT ;
    USE SIGNAL ;
    SHAPE ABUTMENT ;
    PORT
      LAYER M4_m ;
      RECT 138.659 11.904 138.683 11.928 ;
    END
  END rw0_rd_out[221]
  PIN rw0_rd_out[222]
    DIRECTION OUTPUT ;
    USE SIGNAL ;
    SHAPE ABUTMENT ;
    PORT
      LAYER M4_m ;
      RECT 138.659 11.952 138.683 11.976 ;
    END
  END rw0_rd_out[222]
  PIN rw0_rd_out[223]
    DIRECTION OUTPUT ;
    USE SIGNAL ;
    SHAPE ABUTMENT ;
    PORT
      LAYER M4_m ;
      RECT 138.659 12 138.683 12.024 ;
    END
  END rw0_rd_out[223]
  PIN rw0_rd_out[224]
    DIRECTION OUTPUT ;
    USE SIGNAL ;
    SHAPE ABUTMENT ;
    PORT
      LAYER M4_m ;
      RECT 138.659 12.048 138.683 12.072 ;
    END
  END rw0_rd_out[224]
  PIN rw0_rd_out[225]
    DIRECTION OUTPUT ;
    USE SIGNAL ;
    SHAPE ABUTMENT ;
    PORT
      LAYER M4_m ;
      RECT 138.659 12.096 138.683 12.12 ;
    END
  END rw0_rd_out[225]
  PIN rw0_rd_out[226]
    DIRECTION OUTPUT ;
    USE SIGNAL ;
    SHAPE ABUTMENT ;
    PORT
      LAYER M4_m ;
      RECT 138.659 12.144 138.683 12.168 ;
    END
  END rw0_rd_out[226]
  PIN rw0_rd_out[227]
    DIRECTION OUTPUT ;
    USE SIGNAL ;
    SHAPE ABUTMENT ;
    PORT
      LAYER M4_m ;
      RECT 138.659 12.192 138.683 12.216 ;
    END
  END rw0_rd_out[227]
  PIN rw0_rd_out[228]
    DIRECTION OUTPUT ;
    USE SIGNAL ;
    SHAPE ABUTMENT ;
    PORT
      LAYER M4_m ;
      RECT 138.659 12.24 138.683 12.264 ;
    END
  END rw0_rd_out[228]
  PIN rw0_rd_out[229]
    DIRECTION OUTPUT ;
    USE SIGNAL ;
    SHAPE ABUTMENT ;
    PORT
      LAYER M4_m ;
      RECT 138.659 12.288 138.683 12.312 ;
    END
  END rw0_rd_out[229]
  PIN rw0_rd_out[230]
    DIRECTION OUTPUT ;
    USE SIGNAL ;
    SHAPE ABUTMENT ;
    PORT
      LAYER M4_m ;
      RECT 138.659 12.336 138.683 12.36 ;
    END
  END rw0_rd_out[230]
  PIN rw0_rd_out[231]
    DIRECTION OUTPUT ;
    USE SIGNAL ;
    SHAPE ABUTMENT ;
    PORT
      LAYER M4_m ;
      RECT 138.659 12.384 138.683 12.408 ;
    END
  END rw0_rd_out[231]
  PIN rw0_rd_out[232]
    DIRECTION OUTPUT ;
    USE SIGNAL ;
    SHAPE ABUTMENT ;
    PORT
      LAYER M4_m ;
      RECT 138.659 12.432 138.683 12.456 ;
    END
  END rw0_rd_out[232]
  PIN rw0_rd_out[233]
    DIRECTION OUTPUT ;
    USE SIGNAL ;
    SHAPE ABUTMENT ;
    PORT
      LAYER M4_m ;
      RECT 138.659 12.48 138.683 12.504 ;
    END
  END rw0_rd_out[233]
  PIN rw0_rd_out[234]
    DIRECTION OUTPUT ;
    USE SIGNAL ;
    SHAPE ABUTMENT ;
    PORT
      LAYER M4_m ;
      RECT 138.659 12.528 138.683 12.552 ;
    END
  END rw0_rd_out[234]
  PIN rw0_rd_out[235]
    DIRECTION OUTPUT ;
    USE SIGNAL ;
    SHAPE ABUTMENT ;
    PORT
      LAYER M4_m ;
      RECT 138.659 12.576 138.683 12.6 ;
    END
  END rw0_rd_out[235]
  PIN rw0_rd_out[236]
    DIRECTION OUTPUT ;
    USE SIGNAL ;
    SHAPE ABUTMENT ;
    PORT
      LAYER M4_m ;
      RECT 138.659 12.624 138.683 12.648 ;
    END
  END rw0_rd_out[236]
  PIN rw0_rd_out[237]
    DIRECTION OUTPUT ;
    USE SIGNAL ;
    SHAPE ABUTMENT ;
    PORT
      LAYER M4_m ;
      RECT 138.659 12.672 138.683 12.696 ;
    END
  END rw0_rd_out[237]
  PIN rw0_rd_out[238]
    DIRECTION OUTPUT ;
    USE SIGNAL ;
    SHAPE ABUTMENT ;
    PORT
      LAYER M4_m ;
      RECT 138.659 12.72 138.683 12.744 ;
    END
  END rw0_rd_out[238]
  PIN rw0_rd_out[239]
    DIRECTION OUTPUT ;
    USE SIGNAL ;
    SHAPE ABUTMENT ;
    PORT
      LAYER M4_m ;
      RECT 138.659 12.768 138.683 12.792 ;
    END
  END rw0_rd_out[239]
  PIN rw0_rd_out[240]
    DIRECTION OUTPUT ;
    USE SIGNAL ;
    SHAPE ABUTMENT ;
    PORT
      LAYER M4_m ;
      RECT 138.659 12.816 138.683 12.84 ;
    END
  END rw0_rd_out[240]
  PIN rw0_rd_out[241]
    DIRECTION OUTPUT ;
    USE SIGNAL ;
    SHAPE ABUTMENT ;
    PORT
      LAYER M4_m ;
      RECT 138.659 12.864 138.683 12.888 ;
    END
  END rw0_rd_out[241]
  PIN rw0_rd_out[242]
    DIRECTION OUTPUT ;
    USE SIGNAL ;
    SHAPE ABUTMENT ;
    PORT
      LAYER M4_m ;
      RECT 138.659 12.912 138.683 12.936 ;
    END
  END rw0_rd_out[242]
  PIN rw0_rd_out[243]
    DIRECTION OUTPUT ;
    USE SIGNAL ;
    SHAPE ABUTMENT ;
    PORT
      LAYER M4_m ;
      RECT 138.659 12.96 138.683 12.984 ;
    END
  END rw0_rd_out[243]
  PIN rw0_rd_out[244]
    DIRECTION OUTPUT ;
    USE SIGNAL ;
    SHAPE ABUTMENT ;
    PORT
      LAYER M4_m ;
      RECT 138.659 13.008 138.683 13.032 ;
    END
  END rw0_rd_out[244]
  PIN rw0_rd_out[245]
    DIRECTION OUTPUT ;
    USE SIGNAL ;
    SHAPE ABUTMENT ;
    PORT
      LAYER M4_m ;
      RECT 138.659 13.056 138.683 13.08 ;
    END
  END rw0_rd_out[245]
  PIN rw0_rd_out[246]
    DIRECTION OUTPUT ;
    USE SIGNAL ;
    SHAPE ABUTMENT ;
    PORT
      LAYER M4_m ;
      RECT 138.659 13.104 138.683 13.128 ;
    END
  END rw0_rd_out[246]
  PIN rw0_rd_out[247]
    DIRECTION OUTPUT ;
    USE SIGNAL ;
    SHAPE ABUTMENT ;
    PORT
      LAYER M4_m ;
      RECT 138.659 13.152 138.683 13.176 ;
    END
  END rw0_rd_out[247]
  PIN rw0_rd_out[248]
    DIRECTION OUTPUT ;
    USE SIGNAL ;
    SHAPE ABUTMENT ;
    PORT
      LAYER M4_m ;
      RECT 138.659 13.2 138.683 13.224 ;
    END
  END rw0_rd_out[248]
  PIN rw0_rd_out[249]
    DIRECTION OUTPUT ;
    USE SIGNAL ;
    SHAPE ABUTMENT ;
    PORT
      LAYER M4_m ;
      RECT 138.659 13.248 138.683 13.272 ;
    END
  END rw0_rd_out[249]
  PIN rw0_rd_out[250]
    DIRECTION OUTPUT ;
    USE SIGNAL ;
    SHAPE ABUTMENT ;
    PORT
      LAYER M4_m ;
      RECT 138.659 13.296 138.683 13.32 ;
    END
  END rw0_rd_out[250]
  PIN rw0_rd_out[251]
    DIRECTION OUTPUT ;
    USE SIGNAL ;
    SHAPE ABUTMENT ;
    PORT
      LAYER M4_m ;
      RECT 138.659 13.344 138.683 13.368 ;
    END
  END rw0_rd_out[251]
  PIN rw0_rd_out[252]
    DIRECTION OUTPUT ;
    USE SIGNAL ;
    SHAPE ABUTMENT ;
    PORT
      LAYER M4_m ;
      RECT 138.659 13.392 138.683 13.416 ;
    END
  END rw0_rd_out[252]
  PIN rw0_rd_out[253]
    DIRECTION OUTPUT ;
    USE SIGNAL ;
    SHAPE ABUTMENT ;
    PORT
      LAYER M4_m ;
      RECT 138.659 13.44 138.683 13.464 ;
    END
  END rw0_rd_out[253]
  PIN rw0_rd_out[254]
    DIRECTION OUTPUT ;
    USE SIGNAL ;
    SHAPE ABUTMENT ;
    PORT
      LAYER M4_m ;
      RECT 138.659 13.488 138.683 13.512 ;
    END
  END rw0_rd_out[254]
  PIN rw0_rd_out[255]
    DIRECTION OUTPUT ;
    USE SIGNAL ;
    SHAPE ABUTMENT ;
    PORT
      LAYER M4_m ;
      RECT 138.659 13.536 138.683 13.56 ;
    END
  END rw0_rd_out[255]
  PIN rw0_rd_out[256]
    DIRECTION OUTPUT ;
    USE SIGNAL ;
    SHAPE ABUTMENT ;
    PORT
      LAYER M4_m ;
      RECT 138.659 13.584 138.683 13.608 ;
    END
  END rw0_rd_out[256]
  PIN rw0_rd_out[257]
    DIRECTION OUTPUT ;
    USE SIGNAL ;
    SHAPE ABUTMENT ;
    PORT
      LAYER M4_m ;
      RECT 138.659 13.632 138.683 13.656 ;
    END
  END rw0_rd_out[257]
  PIN rw0_rd_out[258]
    DIRECTION OUTPUT ;
    USE SIGNAL ;
    SHAPE ABUTMENT ;
    PORT
      LAYER M4_m ;
      RECT 138.659 13.68 138.683 13.704 ;
    END
  END rw0_rd_out[258]
  PIN rw0_rd_out[259]
    DIRECTION OUTPUT ;
    USE SIGNAL ;
    SHAPE ABUTMENT ;
    PORT
      LAYER M4_m ;
      RECT 138.659 13.728 138.683 13.752 ;
    END
  END rw0_rd_out[259]
  PIN rw0_rd_out[260]
    DIRECTION OUTPUT ;
    USE SIGNAL ;
    SHAPE ABUTMENT ;
    PORT
      LAYER M4_m ;
      RECT 138.659 13.776 138.683 13.8 ;
    END
  END rw0_rd_out[260]
  PIN rw0_rd_out[261]
    DIRECTION OUTPUT ;
    USE SIGNAL ;
    SHAPE ABUTMENT ;
    PORT
      LAYER M4_m ;
      RECT 138.659 13.824 138.683 13.848 ;
    END
  END rw0_rd_out[261]
  PIN rw0_rd_out[262]
    DIRECTION OUTPUT ;
    USE SIGNAL ;
    SHAPE ABUTMENT ;
    PORT
      LAYER M4_m ;
      RECT 138.659 13.872 138.683 13.896 ;
    END
  END rw0_rd_out[262]
  PIN rw0_rd_out[263]
    DIRECTION OUTPUT ;
    USE SIGNAL ;
    SHAPE ABUTMENT ;
    PORT
      LAYER M4_m ;
      RECT 138.659 13.92 138.683 13.944 ;
    END
  END rw0_rd_out[263]
  PIN rw0_rd_out[264]
    DIRECTION OUTPUT ;
    USE SIGNAL ;
    SHAPE ABUTMENT ;
    PORT
      LAYER M4_m ;
      RECT 138.659 13.968 138.683 13.992 ;
    END
  END rw0_rd_out[264]
  PIN rw0_rd_out[265]
    DIRECTION OUTPUT ;
    USE SIGNAL ;
    SHAPE ABUTMENT ;
    PORT
      LAYER M4_m ;
      RECT 138.659 14.016 138.683 14.04 ;
    END
  END rw0_rd_out[265]
  PIN rw0_rd_out[266]
    DIRECTION OUTPUT ;
    USE SIGNAL ;
    SHAPE ABUTMENT ;
    PORT
      LAYER M4_m ;
      RECT 138.659 14.064 138.683 14.088 ;
    END
  END rw0_rd_out[266]
  PIN rw0_rd_out[267]
    DIRECTION OUTPUT ;
    USE SIGNAL ;
    SHAPE ABUTMENT ;
    PORT
      LAYER M4_m ;
      RECT 138.659 14.112 138.683 14.136 ;
    END
  END rw0_rd_out[267]
  PIN rw0_rd_out[268]
    DIRECTION OUTPUT ;
    USE SIGNAL ;
    SHAPE ABUTMENT ;
    PORT
      LAYER M4_m ;
      RECT 138.659 14.16 138.683 14.184 ;
    END
  END rw0_rd_out[268]
  PIN rw0_rd_out[269]
    DIRECTION OUTPUT ;
    USE SIGNAL ;
    SHAPE ABUTMENT ;
    PORT
      LAYER M4_m ;
      RECT 138.659 14.208 138.683 14.232 ;
    END
  END rw0_rd_out[269]
  PIN rw0_rd_out[270]
    DIRECTION OUTPUT ;
    USE SIGNAL ;
    SHAPE ABUTMENT ;
    PORT
      LAYER M4_m ;
      RECT 138.659 14.256 138.683 14.28 ;
    END
  END rw0_rd_out[270]
  PIN rw0_rd_out[271]
    DIRECTION OUTPUT ;
    USE SIGNAL ;
    SHAPE ABUTMENT ;
    PORT
      LAYER M4_m ;
      RECT 138.659 14.304 138.683 14.328 ;
    END
  END rw0_rd_out[271]
  PIN rw0_rd_out[272]
    DIRECTION OUTPUT ;
    USE SIGNAL ;
    SHAPE ABUTMENT ;
    PORT
      LAYER M4_m ;
      RECT 138.659 14.352 138.683 14.376 ;
    END
  END rw0_rd_out[272]
  PIN rw0_rd_out[273]
    DIRECTION OUTPUT ;
    USE SIGNAL ;
    SHAPE ABUTMENT ;
    PORT
      LAYER M4_m ;
      RECT 138.659 14.4 138.683 14.424 ;
    END
  END rw0_rd_out[273]
  PIN rw0_rd_out[274]
    DIRECTION OUTPUT ;
    USE SIGNAL ;
    SHAPE ABUTMENT ;
    PORT
      LAYER M4_m ;
      RECT 138.659 14.448 138.683 14.472 ;
    END
  END rw0_rd_out[274]
  PIN rw0_rd_out[275]
    DIRECTION OUTPUT ;
    USE SIGNAL ;
    SHAPE ABUTMENT ;
    PORT
      LAYER M4_m ;
      RECT 138.659 14.496 138.683 14.52 ;
    END
  END rw0_rd_out[275]
  PIN rw0_rd_out[276]
    DIRECTION OUTPUT ;
    USE SIGNAL ;
    SHAPE ABUTMENT ;
    PORT
      LAYER M4_m ;
      RECT 138.659 14.544 138.683 14.568 ;
    END
  END rw0_rd_out[276]
  PIN rw0_rd_out[277]
    DIRECTION OUTPUT ;
    USE SIGNAL ;
    SHAPE ABUTMENT ;
    PORT
      LAYER M4_m ;
      RECT 138.659 14.592 138.683 14.616 ;
    END
  END rw0_rd_out[277]
  PIN rw0_rd_out[278]
    DIRECTION OUTPUT ;
    USE SIGNAL ;
    SHAPE ABUTMENT ;
    PORT
      LAYER M4_m ;
      RECT 138.659 14.64 138.683 14.664 ;
    END
  END rw0_rd_out[278]
  PIN rw0_rd_out[279]
    DIRECTION OUTPUT ;
    USE SIGNAL ;
    SHAPE ABUTMENT ;
    PORT
      LAYER M4_m ;
      RECT 138.659 14.688 138.683 14.712 ;
    END
  END rw0_rd_out[279]
  PIN rw0_rd_out[280]
    DIRECTION OUTPUT ;
    USE SIGNAL ;
    SHAPE ABUTMENT ;
    PORT
      LAYER M4_m ;
      RECT 138.659 14.736 138.683 14.76 ;
    END
  END rw0_rd_out[280]
  PIN rw0_rd_out[281]
    DIRECTION OUTPUT ;
    USE SIGNAL ;
    SHAPE ABUTMENT ;
    PORT
      LAYER M4_m ;
      RECT 138.659 14.784 138.683 14.808 ;
    END
  END rw0_rd_out[281]
  PIN rw0_rd_out[282]
    DIRECTION OUTPUT ;
    USE SIGNAL ;
    SHAPE ABUTMENT ;
    PORT
      LAYER M4_m ;
      RECT 138.659 14.832 138.683 14.856 ;
    END
  END rw0_rd_out[282]
  PIN rw0_rd_out[283]
    DIRECTION OUTPUT ;
    USE SIGNAL ;
    SHAPE ABUTMENT ;
    PORT
      LAYER M4_m ;
      RECT 138.659 14.88 138.683 14.904 ;
    END
  END rw0_rd_out[283]
  PIN rw0_rd_out[284]
    DIRECTION OUTPUT ;
    USE SIGNAL ;
    SHAPE ABUTMENT ;
    PORT
      LAYER M4_m ;
      RECT 138.659 14.928 138.683 14.952 ;
    END
  END rw0_rd_out[284]
  PIN rw0_rd_out[285]
    DIRECTION OUTPUT ;
    USE SIGNAL ;
    SHAPE ABUTMENT ;
    PORT
      LAYER M4_m ;
      RECT 138.659 14.976 138.683 15 ;
    END
  END rw0_rd_out[285]
  PIN rw0_rd_out[286]
    DIRECTION OUTPUT ;
    USE SIGNAL ;
    SHAPE ABUTMENT ;
    PORT
      LAYER M4_m ;
      RECT 138.659 15.024 138.683 15.048 ;
    END
  END rw0_rd_out[286]
  PIN rw0_rd_out[287]
    DIRECTION OUTPUT ;
    USE SIGNAL ;
    SHAPE ABUTMENT ;
    PORT
      LAYER M4_m ;
      RECT 138.659 15.072 138.683 15.096 ;
    END
  END rw0_rd_out[287]
  PIN rw0_rd_out[288]
    DIRECTION OUTPUT ;
    USE SIGNAL ;
    SHAPE ABUTMENT ;
    PORT
      LAYER M4_m ;
      RECT 138.659 15.12 138.683 15.144 ;
    END
  END rw0_rd_out[288]
  PIN rw0_rd_out[289]
    DIRECTION OUTPUT ;
    USE SIGNAL ;
    SHAPE ABUTMENT ;
    PORT
      LAYER M4_m ;
      RECT 138.659 15.168 138.683 15.192 ;
    END
  END rw0_rd_out[289]
  PIN rw0_rd_out[290]
    DIRECTION OUTPUT ;
    USE SIGNAL ;
    SHAPE ABUTMENT ;
    PORT
      LAYER M4_m ;
      RECT 138.659 15.216 138.683 15.24 ;
    END
  END rw0_rd_out[290]
  PIN rw0_rd_out[291]
    DIRECTION OUTPUT ;
    USE SIGNAL ;
    SHAPE ABUTMENT ;
    PORT
      LAYER M4_m ;
      RECT 138.659 15.264 138.683 15.288 ;
    END
  END rw0_rd_out[291]
  PIN rw0_rd_out[292]
    DIRECTION OUTPUT ;
    USE SIGNAL ;
    SHAPE ABUTMENT ;
    PORT
      LAYER M4_m ;
      RECT 138.659 15.312 138.683 15.336 ;
    END
  END rw0_rd_out[292]
  PIN rw0_rd_out[293]
    DIRECTION OUTPUT ;
    USE SIGNAL ;
    SHAPE ABUTMENT ;
    PORT
      LAYER M4_m ;
      RECT 138.659 15.36 138.683 15.384 ;
    END
  END rw0_rd_out[293]
  PIN rw0_rd_out[294]
    DIRECTION OUTPUT ;
    USE SIGNAL ;
    SHAPE ABUTMENT ;
    PORT
      LAYER M4_m ;
      RECT 138.659 15.408 138.683 15.432 ;
    END
  END rw0_rd_out[294]
  PIN rw0_rd_out[295]
    DIRECTION OUTPUT ;
    USE SIGNAL ;
    SHAPE ABUTMENT ;
    PORT
      LAYER M4_m ;
      RECT 138.659 15.456 138.683 15.48 ;
    END
  END rw0_rd_out[295]
  PIN rw0_rd_out[296]
    DIRECTION OUTPUT ;
    USE SIGNAL ;
    SHAPE ABUTMENT ;
    PORT
      LAYER M4_m ;
      RECT 138.659 15.504 138.683 15.528 ;
    END
  END rw0_rd_out[296]
  PIN rw0_rd_out[297]
    DIRECTION OUTPUT ;
    USE SIGNAL ;
    SHAPE ABUTMENT ;
    PORT
      LAYER M4_m ;
      RECT 138.659 15.552 138.683 15.576 ;
    END
  END rw0_rd_out[297]
  PIN rw0_rd_out[298]
    DIRECTION OUTPUT ;
    USE SIGNAL ;
    SHAPE ABUTMENT ;
    PORT
      LAYER M4_m ;
      RECT 138.659 15.6 138.683 15.624 ;
    END
  END rw0_rd_out[298]
  PIN rw0_rd_out[299]
    DIRECTION OUTPUT ;
    USE SIGNAL ;
    SHAPE ABUTMENT ;
    PORT
      LAYER M4_m ;
      RECT 138.659 15.648 138.683 15.672 ;
    END
  END rw0_rd_out[299]
  PIN rw0_rd_out[300]
    DIRECTION OUTPUT ;
    USE SIGNAL ;
    SHAPE ABUTMENT ;
    PORT
      LAYER M4_m ;
      RECT 138.659 15.696 138.683 15.72 ;
    END
  END rw0_rd_out[300]
  PIN rw0_rd_out[301]
    DIRECTION OUTPUT ;
    USE SIGNAL ;
    SHAPE ABUTMENT ;
    PORT
      LAYER M4_m ;
      RECT 138.659 15.744 138.683 15.768 ;
    END
  END rw0_rd_out[301]
  PIN rw0_rd_out[302]
    DIRECTION OUTPUT ;
    USE SIGNAL ;
    SHAPE ABUTMENT ;
    PORT
      LAYER M4_m ;
      RECT 138.659 15.792 138.683 15.816 ;
    END
  END rw0_rd_out[302]
  PIN rw0_rd_out[303]
    DIRECTION OUTPUT ;
    USE SIGNAL ;
    SHAPE ABUTMENT ;
    PORT
      LAYER M4_m ;
      RECT 138.659 15.84 138.683 15.864 ;
    END
  END rw0_rd_out[303]
  PIN rw0_rd_out[304]
    DIRECTION OUTPUT ;
    USE SIGNAL ;
    SHAPE ABUTMENT ;
    PORT
      LAYER M4_m ;
      RECT 138.659 15.888 138.683 15.912 ;
    END
  END rw0_rd_out[304]
  PIN rw0_rd_out[305]
    DIRECTION OUTPUT ;
    USE SIGNAL ;
    SHAPE ABUTMENT ;
    PORT
      LAYER M4_m ;
      RECT 138.659 15.936 138.683 15.96 ;
    END
  END rw0_rd_out[305]
  PIN rw0_rd_out[306]
    DIRECTION OUTPUT ;
    USE SIGNAL ;
    SHAPE ABUTMENT ;
    PORT
      LAYER M4_m ;
      RECT 138.659 15.984 138.683 16.008 ;
    END
  END rw0_rd_out[306]
  PIN rw0_rd_out[307]
    DIRECTION OUTPUT ;
    USE SIGNAL ;
    SHAPE ABUTMENT ;
    PORT
      LAYER M4_m ;
      RECT 138.659 16.032 138.683 16.056 ;
    END
  END rw0_rd_out[307]
  PIN rw0_rd_out[308]
    DIRECTION OUTPUT ;
    USE SIGNAL ;
    SHAPE ABUTMENT ;
    PORT
      LAYER M4_m ;
      RECT 138.659 16.08 138.683 16.104 ;
    END
  END rw0_rd_out[308]
  PIN rw0_rd_out[309]
    DIRECTION OUTPUT ;
    USE SIGNAL ;
    SHAPE ABUTMENT ;
    PORT
      LAYER M4_m ;
      RECT 138.659 16.128 138.683 16.152 ;
    END
  END rw0_rd_out[309]
  PIN rw0_rd_out[310]
    DIRECTION OUTPUT ;
    USE SIGNAL ;
    SHAPE ABUTMENT ;
    PORT
      LAYER M4_m ;
      RECT 138.659 16.176 138.683 16.2 ;
    END
  END rw0_rd_out[310]
  PIN rw0_rd_out[311]
    DIRECTION OUTPUT ;
    USE SIGNAL ;
    SHAPE ABUTMENT ;
    PORT
      LAYER M4_m ;
      RECT 138.659 16.224 138.683 16.248 ;
    END
  END rw0_rd_out[311]
  PIN rw0_rd_out[312]
    DIRECTION OUTPUT ;
    USE SIGNAL ;
    SHAPE ABUTMENT ;
    PORT
      LAYER M4_m ;
      RECT 138.659 16.272 138.683 16.296 ;
    END
  END rw0_rd_out[312]
  PIN rw0_rd_out[313]
    DIRECTION OUTPUT ;
    USE SIGNAL ;
    SHAPE ABUTMENT ;
    PORT
      LAYER M4_m ;
      RECT 138.659 16.32 138.683 16.344 ;
    END
  END rw0_rd_out[313]
  PIN rw0_rd_out[314]
    DIRECTION OUTPUT ;
    USE SIGNAL ;
    SHAPE ABUTMENT ;
    PORT
      LAYER M4_m ;
      RECT 138.659 16.368 138.683 16.392 ;
    END
  END rw0_rd_out[314]
  PIN rw0_rd_out[315]
    DIRECTION OUTPUT ;
    USE SIGNAL ;
    SHAPE ABUTMENT ;
    PORT
      LAYER M4_m ;
      RECT 138.659 16.416 138.683 16.44 ;
    END
  END rw0_rd_out[315]
  PIN rw0_rd_out[316]
    DIRECTION OUTPUT ;
    USE SIGNAL ;
    SHAPE ABUTMENT ;
    PORT
      LAYER M4_m ;
      RECT 138.659 16.464 138.683 16.488 ;
    END
  END rw0_rd_out[316]
  PIN rw0_rd_out[317]
    DIRECTION OUTPUT ;
    USE SIGNAL ;
    SHAPE ABUTMENT ;
    PORT
      LAYER M4_m ;
      RECT 138.659 16.512 138.683 16.536 ;
    END
  END rw0_rd_out[317]
  PIN rw0_rd_out[318]
    DIRECTION OUTPUT ;
    USE SIGNAL ;
    SHAPE ABUTMENT ;
    PORT
      LAYER M4_m ;
      RECT 138.659 16.56 138.683 16.584 ;
    END
  END rw0_rd_out[318]
  PIN rw0_rd_out[319]
    DIRECTION OUTPUT ;
    USE SIGNAL ;
    SHAPE ABUTMENT ;
    PORT
      LAYER M4_m ;
      RECT 138.659 16.608 138.683 16.632 ;
    END
  END rw0_rd_out[319]
  PIN rw0_rd_out[320]
    DIRECTION OUTPUT ;
    USE SIGNAL ;
    SHAPE ABUTMENT ;
    PORT
      LAYER M4_m ;
      RECT 138.659 16.656 138.683 16.68 ;
    END
  END rw0_rd_out[320]
  PIN rw0_rd_out[321]
    DIRECTION OUTPUT ;
    USE SIGNAL ;
    SHAPE ABUTMENT ;
    PORT
      LAYER M4_m ;
      RECT 138.659 16.704 138.683 16.728 ;
    END
  END rw0_rd_out[321]
  PIN rw0_rd_out[322]
    DIRECTION OUTPUT ;
    USE SIGNAL ;
    SHAPE ABUTMENT ;
    PORT
      LAYER M4_m ;
      RECT 138.659 16.752 138.683 16.776 ;
    END
  END rw0_rd_out[322]
  PIN rw0_rd_out[323]
    DIRECTION OUTPUT ;
    USE SIGNAL ;
    SHAPE ABUTMENT ;
    PORT
      LAYER M4_m ;
      RECT 138.659 16.8 138.683 16.824 ;
    END
  END rw0_rd_out[323]
  PIN rw0_rd_out[324]
    DIRECTION OUTPUT ;
    USE SIGNAL ;
    SHAPE ABUTMENT ;
    PORT
      LAYER M4_m ;
      RECT 138.659 16.848 138.683 16.872 ;
    END
  END rw0_rd_out[324]
  PIN rw0_rd_out[325]
    DIRECTION OUTPUT ;
    USE SIGNAL ;
    SHAPE ABUTMENT ;
    PORT
      LAYER M4_m ;
      RECT 138.659 16.896 138.683 16.92 ;
    END
  END rw0_rd_out[325]
  PIN rw0_rd_out[326]
    DIRECTION OUTPUT ;
    USE SIGNAL ;
    SHAPE ABUTMENT ;
    PORT
      LAYER M4_m ;
      RECT 138.659 16.944 138.683 16.968 ;
    END
  END rw0_rd_out[326]
  PIN rw0_rd_out[327]
    DIRECTION OUTPUT ;
    USE SIGNAL ;
    SHAPE ABUTMENT ;
    PORT
      LAYER M4_m ;
      RECT 138.659 16.992 138.683 17.016 ;
    END
  END rw0_rd_out[327]
  PIN rw0_rd_out[328]
    DIRECTION OUTPUT ;
    USE SIGNAL ;
    SHAPE ABUTMENT ;
    PORT
      LAYER M4_m ;
      RECT 138.659 17.04 138.683 17.064 ;
    END
  END rw0_rd_out[328]
  PIN rw0_rd_out[329]
    DIRECTION OUTPUT ;
    USE SIGNAL ;
    SHAPE ABUTMENT ;
    PORT
      LAYER M4_m ;
      RECT 138.659 17.088 138.683 17.112 ;
    END
  END rw0_rd_out[329]
  PIN rw0_rd_out[330]
    DIRECTION OUTPUT ;
    USE SIGNAL ;
    SHAPE ABUTMENT ;
    PORT
      LAYER M4_m ;
      RECT 138.659 17.136 138.683 17.16 ;
    END
  END rw0_rd_out[330]
  PIN rw0_rd_out[331]
    DIRECTION OUTPUT ;
    USE SIGNAL ;
    SHAPE ABUTMENT ;
    PORT
      LAYER M4_m ;
      RECT 138.659 17.184 138.683 17.208 ;
    END
  END rw0_rd_out[331]
  PIN rw0_rd_out[332]
    DIRECTION OUTPUT ;
    USE SIGNAL ;
    SHAPE ABUTMENT ;
    PORT
      LAYER M4_m ;
      RECT 138.659 17.232 138.683 17.256 ;
    END
  END rw0_rd_out[332]
  PIN rw0_rd_out[333]
    DIRECTION OUTPUT ;
    USE SIGNAL ;
    SHAPE ABUTMENT ;
    PORT
      LAYER M4_m ;
      RECT 138.659 17.28 138.683 17.304 ;
    END
  END rw0_rd_out[333]
  PIN rw0_rd_out[334]
    DIRECTION OUTPUT ;
    USE SIGNAL ;
    SHAPE ABUTMENT ;
    PORT
      LAYER M4_m ;
      RECT 138.659 17.328 138.683 17.352 ;
    END
  END rw0_rd_out[334]
  PIN rw0_rd_out[335]
    DIRECTION OUTPUT ;
    USE SIGNAL ;
    SHAPE ABUTMENT ;
    PORT
      LAYER M4_m ;
      RECT 138.659 17.376 138.683 17.4 ;
    END
  END rw0_rd_out[335]
  PIN rw0_rd_out[336]
    DIRECTION OUTPUT ;
    USE SIGNAL ;
    SHAPE ABUTMENT ;
    PORT
      LAYER M4_m ;
      RECT 138.659 17.424 138.683 17.448 ;
    END
  END rw0_rd_out[336]
  PIN rw0_rd_out[337]
    DIRECTION OUTPUT ;
    USE SIGNAL ;
    SHAPE ABUTMENT ;
    PORT
      LAYER M4_m ;
      RECT 138.659 17.472 138.683 17.496 ;
    END
  END rw0_rd_out[337]
  PIN rw0_rd_out[338]
    DIRECTION OUTPUT ;
    USE SIGNAL ;
    SHAPE ABUTMENT ;
    PORT
      LAYER M4_m ;
      RECT 138.659 17.52 138.683 17.544 ;
    END
  END rw0_rd_out[338]
  PIN rw0_rd_out[339]
    DIRECTION OUTPUT ;
    USE SIGNAL ;
    SHAPE ABUTMENT ;
    PORT
      LAYER M4_m ;
      RECT 138.659 17.568 138.683 17.592 ;
    END
  END rw0_rd_out[339]
  PIN rw0_rd_out[340]
    DIRECTION OUTPUT ;
    USE SIGNAL ;
    SHAPE ABUTMENT ;
    PORT
      LAYER M4_m ;
      RECT 138.659 17.616 138.683 17.64 ;
    END
  END rw0_rd_out[340]
  PIN rw0_rd_out[341]
    DIRECTION OUTPUT ;
    USE SIGNAL ;
    SHAPE ABUTMENT ;
    PORT
      LAYER M4_m ;
      RECT 138.659 17.664 138.683 17.688 ;
    END
  END rw0_rd_out[341]
  PIN rw0_rd_out[342]
    DIRECTION OUTPUT ;
    USE SIGNAL ;
    SHAPE ABUTMENT ;
    PORT
      LAYER M4_m ;
      RECT 138.659 17.712 138.683 17.736 ;
    END
  END rw0_rd_out[342]
  PIN rw0_rd_out[343]
    DIRECTION OUTPUT ;
    USE SIGNAL ;
    SHAPE ABUTMENT ;
    PORT
      LAYER M4_m ;
      RECT 138.659 17.76 138.683 17.784 ;
    END
  END rw0_rd_out[343]
  PIN rw0_rd_out[344]
    DIRECTION OUTPUT ;
    USE SIGNAL ;
    SHAPE ABUTMENT ;
    PORT
      LAYER M4_m ;
      RECT 138.659 17.808 138.683 17.832 ;
    END
  END rw0_rd_out[344]
  PIN rw0_rd_out[345]
    DIRECTION OUTPUT ;
    USE SIGNAL ;
    SHAPE ABUTMENT ;
    PORT
      LAYER M4_m ;
      RECT 138.659 17.856 138.683 17.88 ;
    END
  END rw0_rd_out[345]
  PIN rw0_rd_out[346]
    DIRECTION OUTPUT ;
    USE SIGNAL ;
    SHAPE ABUTMENT ;
    PORT
      LAYER M4_m ;
      RECT 138.659 17.904 138.683 17.928 ;
    END
  END rw0_rd_out[346]
  PIN rw0_rd_out[347]
    DIRECTION OUTPUT ;
    USE SIGNAL ;
    SHAPE ABUTMENT ;
    PORT
      LAYER M4_m ;
      RECT 138.659 17.952 138.683 17.976 ;
    END
  END rw0_rd_out[347]
  PIN rw0_rd_out[348]
    DIRECTION OUTPUT ;
    USE SIGNAL ;
    SHAPE ABUTMENT ;
    PORT
      LAYER M4_m ;
      RECT 138.659 18 138.683 18.024 ;
    END
  END rw0_rd_out[348]
  PIN rw0_rd_out[349]
    DIRECTION OUTPUT ;
    USE SIGNAL ;
    SHAPE ABUTMENT ;
    PORT
      LAYER M4_m ;
      RECT 138.659 18.048 138.683 18.072 ;
    END
  END rw0_rd_out[349]
  PIN rw0_rd_out[350]
    DIRECTION OUTPUT ;
    USE SIGNAL ;
    SHAPE ABUTMENT ;
    PORT
      LAYER M4_m ;
      RECT 138.659 18.096 138.683 18.12 ;
    END
  END rw0_rd_out[350]
  PIN rw0_rd_out[351]
    DIRECTION OUTPUT ;
    USE SIGNAL ;
    SHAPE ABUTMENT ;
    PORT
      LAYER M4_m ;
      RECT 138.659 18.144 138.683 18.168 ;
    END
  END rw0_rd_out[351]
  PIN rw0_rd_out[352]
    DIRECTION OUTPUT ;
    USE SIGNAL ;
    SHAPE ABUTMENT ;
    PORT
      LAYER M4_m ;
      RECT 138.659 18.192 138.683 18.216 ;
    END
  END rw0_rd_out[352]
  PIN rw0_rd_out[353]
    DIRECTION OUTPUT ;
    USE SIGNAL ;
    SHAPE ABUTMENT ;
    PORT
      LAYER M4_m ;
      RECT 138.659 18.24 138.683 18.264 ;
    END
  END rw0_rd_out[353]
  PIN rw0_rd_out[354]
    DIRECTION OUTPUT ;
    USE SIGNAL ;
    SHAPE ABUTMENT ;
    PORT
      LAYER M4_m ;
      RECT 138.659 18.288 138.683 18.312 ;
    END
  END rw0_rd_out[354]
  PIN rw0_rd_out[355]
    DIRECTION OUTPUT ;
    USE SIGNAL ;
    SHAPE ABUTMENT ;
    PORT
      LAYER M4_m ;
      RECT 138.659 18.336 138.683 18.36 ;
    END
  END rw0_rd_out[355]
  PIN rw0_rd_out[356]
    DIRECTION OUTPUT ;
    USE SIGNAL ;
    SHAPE ABUTMENT ;
    PORT
      LAYER M4_m ;
      RECT 138.659 18.384 138.683 18.408 ;
    END
  END rw0_rd_out[356]
  PIN rw0_rd_out[357]
    DIRECTION OUTPUT ;
    USE SIGNAL ;
    SHAPE ABUTMENT ;
    PORT
      LAYER M4_m ;
      RECT 138.659 18.432 138.683 18.456 ;
    END
  END rw0_rd_out[357]
  PIN rw0_rd_out[358]
    DIRECTION OUTPUT ;
    USE SIGNAL ;
    SHAPE ABUTMENT ;
    PORT
      LAYER M4_m ;
      RECT 138.659 18.48 138.683 18.504 ;
    END
  END rw0_rd_out[358]
  PIN rw0_rd_out[359]
    DIRECTION OUTPUT ;
    USE SIGNAL ;
    SHAPE ABUTMENT ;
    PORT
      LAYER M4_m ;
      RECT 138.659 18.528 138.683 18.552 ;
    END
  END rw0_rd_out[359]
  PIN rw0_rd_out[360]
    DIRECTION OUTPUT ;
    USE SIGNAL ;
    SHAPE ABUTMENT ;
    PORT
      LAYER M4_m ;
      RECT 138.659 18.576 138.683 18.6 ;
    END
  END rw0_rd_out[360]
  PIN rw0_rd_out[361]
    DIRECTION OUTPUT ;
    USE SIGNAL ;
    SHAPE ABUTMENT ;
    PORT
      LAYER M4_m ;
      RECT 138.659 18.624 138.683 18.648 ;
    END
  END rw0_rd_out[361]
  PIN rw0_rd_out[362]
    DIRECTION OUTPUT ;
    USE SIGNAL ;
    SHAPE ABUTMENT ;
    PORT
      LAYER M4_m ;
      RECT 138.659 18.672 138.683 18.696 ;
    END
  END rw0_rd_out[362]
  PIN rw0_rd_out[363]
    DIRECTION OUTPUT ;
    USE SIGNAL ;
    SHAPE ABUTMENT ;
    PORT
      LAYER M4_m ;
      RECT 138.659 18.72 138.683 18.744 ;
    END
  END rw0_rd_out[363]
  PIN rw0_rd_out[364]
    DIRECTION OUTPUT ;
    USE SIGNAL ;
    SHAPE ABUTMENT ;
    PORT
      LAYER M4_m ;
      RECT 138.659 18.768 138.683 18.792 ;
    END
  END rw0_rd_out[364]
  PIN rw0_rd_out[365]
    DIRECTION OUTPUT ;
    USE SIGNAL ;
    SHAPE ABUTMENT ;
    PORT
      LAYER M4_m ;
      RECT 138.659 18.816 138.683 18.84 ;
    END
  END rw0_rd_out[365]
  PIN rw0_rd_out[366]
    DIRECTION OUTPUT ;
    USE SIGNAL ;
    SHAPE ABUTMENT ;
    PORT
      LAYER M4_m ;
      RECT 138.659 18.864 138.683 18.888 ;
    END
  END rw0_rd_out[366]
  PIN rw0_rd_out[367]
    DIRECTION OUTPUT ;
    USE SIGNAL ;
    SHAPE ABUTMENT ;
    PORT
      LAYER M4_m ;
      RECT 138.659 18.912 138.683 18.936 ;
    END
  END rw0_rd_out[367]
  PIN rw0_rd_out[368]
    DIRECTION OUTPUT ;
    USE SIGNAL ;
    SHAPE ABUTMENT ;
    PORT
      LAYER M4_m ;
      RECT 138.659 18.96 138.683 18.984 ;
    END
  END rw0_rd_out[368]
  PIN rw0_rd_out[369]
    DIRECTION OUTPUT ;
    USE SIGNAL ;
    SHAPE ABUTMENT ;
    PORT
      LAYER M4_m ;
      RECT 138.659 19.008 138.683 19.032 ;
    END
  END rw0_rd_out[369]
  PIN rw0_rd_out[370]
    DIRECTION OUTPUT ;
    USE SIGNAL ;
    SHAPE ABUTMENT ;
    PORT
      LAYER M4_m ;
      RECT 138.659 19.056 138.683 19.08 ;
    END
  END rw0_rd_out[370]
  PIN rw0_rd_out[371]
    DIRECTION OUTPUT ;
    USE SIGNAL ;
    SHAPE ABUTMENT ;
    PORT
      LAYER M4_m ;
      RECT 138.659 19.104 138.683 19.128 ;
    END
  END rw0_rd_out[371]
  PIN rw0_rd_out[372]
    DIRECTION OUTPUT ;
    USE SIGNAL ;
    SHAPE ABUTMENT ;
    PORT
      LAYER M4_m ;
      RECT 138.659 19.152 138.683 19.176 ;
    END
  END rw0_rd_out[372]
  PIN rw0_rd_out[373]
    DIRECTION OUTPUT ;
    USE SIGNAL ;
    SHAPE ABUTMENT ;
    PORT
      LAYER M4_m ;
      RECT 138.659 19.2 138.683 19.224 ;
    END
  END rw0_rd_out[373]
  PIN rw0_rd_out[374]
    DIRECTION OUTPUT ;
    USE SIGNAL ;
    SHAPE ABUTMENT ;
    PORT
      LAYER M4_m ;
      RECT 138.659 19.248 138.683 19.272 ;
    END
  END rw0_rd_out[374]
  PIN rw0_rd_out[375]
    DIRECTION OUTPUT ;
    USE SIGNAL ;
    SHAPE ABUTMENT ;
    PORT
      LAYER M4_m ;
      RECT 138.659 19.296 138.683 19.32 ;
    END
  END rw0_rd_out[375]
  PIN rw0_rd_out[376]
    DIRECTION OUTPUT ;
    USE SIGNAL ;
    SHAPE ABUTMENT ;
    PORT
      LAYER M4_m ;
      RECT 138.659 19.344 138.683 19.368 ;
    END
  END rw0_rd_out[376]
  PIN rw0_rd_out[377]
    DIRECTION OUTPUT ;
    USE SIGNAL ;
    SHAPE ABUTMENT ;
    PORT
      LAYER M4_m ;
      RECT 138.659 19.392 138.683 19.416 ;
    END
  END rw0_rd_out[377]
  PIN rw0_rd_out[378]
    DIRECTION OUTPUT ;
    USE SIGNAL ;
    SHAPE ABUTMENT ;
    PORT
      LAYER M4_m ;
      RECT 138.659 19.44 138.683 19.464 ;
    END
  END rw0_rd_out[378]
  PIN rw0_rd_out[379]
    DIRECTION OUTPUT ;
    USE SIGNAL ;
    SHAPE ABUTMENT ;
    PORT
      LAYER M4_m ;
      RECT 138.659 19.488 138.683 19.512 ;
    END
  END rw0_rd_out[379]
  PIN rw0_rd_out[380]
    DIRECTION OUTPUT ;
    USE SIGNAL ;
    SHAPE ABUTMENT ;
    PORT
      LAYER M4_m ;
      RECT 138.659 19.536 138.683 19.56 ;
    END
  END rw0_rd_out[380]
  PIN rw0_rd_out[381]
    DIRECTION OUTPUT ;
    USE SIGNAL ;
    SHAPE ABUTMENT ;
    PORT
      LAYER M4_m ;
      RECT 138.659 19.584 138.683 19.608 ;
    END
  END rw0_rd_out[381]
  PIN rw0_rd_out[382]
    DIRECTION OUTPUT ;
    USE SIGNAL ;
    SHAPE ABUTMENT ;
    PORT
      LAYER M4_m ;
      RECT 138.659 19.632 138.683 19.656 ;
    END
  END rw0_rd_out[382]
  PIN rw0_rd_out[383]
    DIRECTION OUTPUT ;
    USE SIGNAL ;
    SHAPE ABUTMENT ;
    PORT
      LAYER M4_m ;
      RECT 138.659 19.68 138.683 19.704 ;
    END
  END rw0_rd_out[383]
  PIN rw0_rd_out[384]
    DIRECTION OUTPUT ;
    USE SIGNAL ;
    SHAPE ABUTMENT ;
    PORT
      LAYER M4_m ;
      RECT 138.659 19.728 138.683 19.752 ;
    END
  END rw0_rd_out[384]
  PIN rw0_rd_out[385]
    DIRECTION OUTPUT ;
    USE SIGNAL ;
    SHAPE ABUTMENT ;
    PORT
      LAYER M4_m ;
      RECT 138.659 19.776 138.683 19.8 ;
    END
  END rw0_rd_out[385]
  PIN rw0_rd_out[386]
    DIRECTION OUTPUT ;
    USE SIGNAL ;
    SHAPE ABUTMENT ;
    PORT
      LAYER M4_m ;
      RECT 138.659 19.824 138.683 19.848 ;
    END
  END rw0_rd_out[386]
  PIN rw0_rd_out[387]
    DIRECTION OUTPUT ;
    USE SIGNAL ;
    SHAPE ABUTMENT ;
    PORT
      LAYER M4_m ;
      RECT 138.659 19.872 138.683 19.896 ;
    END
  END rw0_rd_out[387]
  PIN rw0_rd_out[388]
    DIRECTION OUTPUT ;
    USE SIGNAL ;
    SHAPE ABUTMENT ;
    PORT
      LAYER M4_m ;
      RECT 138.659 19.92 138.683 19.944 ;
    END
  END rw0_rd_out[388]
  PIN rw0_rd_out[389]
    DIRECTION OUTPUT ;
    USE SIGNAL ;
    SHAPE ABUTMENT ;
    PORT
      LAYER M4_m ;
      RECT 138.659 19.968 138.683 19.992 ;
    END
  END rw0_rd_out[389]
  PIN rw0_rd_out[390]
    DIRECTION OUTPUT ;
    USE SIGNAL ;
    SHAPE ABUTMENT ;
    PORT
      LAYER M4_m ;
      RECT 138.659 20.016 138.683 20.04 ;
    END
  END rw0_rd_out[390]
  PIN rw0_rd_out[391]
    DIRECTION OUTPUT ;
    USE SIGNAL ;
    SHAPE ABUTMENT ;
    PORT
      LAYER M4_m ;
      RECT 138.659 20.064 138.683 20.088 ;
    END
  END rw0_rd_out[391]
  PIN rw0_rd_out[392]
    DIRECTION OUTPUT ;
    USE SIGNAL ;
    SHAPE ABUTMENT ;
    PORT
      LAYER M4_m ;
      RECT 138.659 20.112 138.683 20.136 ;
    END
  END rw0_rd_out[392]
  PIN rw0_rd_out[393]
    DIRECTION OUTPUT ;
    USE SIGNAL ;
    SHAPE ABUTMENT ;
    PORT
      LAYER M4_m ;
      RECT 138.659 20.16 138.683 20.184 ;
    END
  END rw0_rd_out[393]
  PIN rw0_rd_out[394]
    DIRECTION OUTPUT ;
    USE SIGNAL ;
    SHAPE ABUTMENT ;
    PORT
      LAYER M4_m ;
      RECT 138.659 20.208 138.683 20.232 ;
    END
  END rw0_rd_out[394]
  PIN rw0_rd_out[395]
    DIRECTION OUTPUT ;
    USE SIGNAL ;
    SHAPE ABUTMENT ;
    PORT
      LAYER M4_m ;
      RECT 138.659 20.256 138.683 20.28 ;
    END
  END rw0_rd_out[395]
  PIN rw0_rd_out[396]
    DIRECTION OUTPUT ;
    USE SIGNAL ;
    SHAPE ABUTMENT ;
    PORT
      LAYER M4_m ;
      RECT 138.659 20.304 138.683 20.328 ;
    END
  END rw0_rd_out[396]
  PIN rw0_rd_out[397]
    DIRECTION OUTPUT ;
    USE SIGNAL ;
    SHAPE ABUTMENT ;
    PORT
      LAYER M4_m ;
      RECT 138.659 20.352 138.683 20.376 ;
    END
  END rw0_rd_out[397]
  PIN rw0_rd_out[398]
    DIRECTION OUTPUT ;
    USE SIGNAL ;
    SHAPE ABUTMENT ;
    PORT
      LAYER M4_m ;
      RECT 138.659 20.4 138.683 20.424 ;
    END
  END rw0_rd_out[398]
  PIN rw0_rd_out[399]
    DIRECTION OUTPUT ;
    USE SIGNAL ;
    SHAPE ABUTMENT ;
    PORT
      LAYER M4_m ;
      RECT 138.659 20.448 138.683 20.472 ;
    END
  END rw0_rd_out[399]
  PIN rw0_rd_out[400]
    DIRECTION OUTPUT ;
    USE SIGNAL ;
    SHAPE ABUTMENT ;
    PORT
      LAYER M4_m ;
      RECT 138.659 20.496 138.683 20.52 ;
    END
  END rw0_rd_out[400]
  PIN rw0_rd_out[401]
    DIRECTION OUTPUT ;
    USE SIGNAL ;
    SHAPE ABUTMENT ;
    PORT
      LAYER M4_m ;
      RECT 138.659 20.544 138.683 20.568 ;
    END
  END rw0_rd_out[401]
  PIN rw0_rd_out[402]
    DIRECTION OUTPUT ;
    USE SIGNAL ;
    SHAPE ABUTMENT ;
    PORT
      LAYER M4_m ;
      RECT 138.659 20.592 138.683 20.616 ;
    END
  END rw0_rd_out[402]
  PIN rw0_rd_out[403]
    DIRECTION OUTPUT ;
    USE SIGNAL ;
    SHAPE ABUTMENT ;
    PORT
      LAYER M4_m ;
      RECT 138.659 20.64 138.683 20.664 ;
    END
  END rw0_rd_out[403]
  PIN rw0_rd_out[404]
    DIRECTION OUTPUT ;
    USE SIGNAL ;
    SHAPE ABUTMENT ;
    PORT
      LAYER M4_m ;
      RECT 138.659 20.688 138.683 20.712 ;
    END
  END rw0_rd_out[404]
  PIN rw0_rd_out[405]
    DIRECTION OUTPUT ;
    USE SIGNAL ;
    SHAPE ABUTMENT ;
    PORT
      LAYER M4_m ;
      RECT 138.659 20.736 138.683 20.76 ;
    END
  END rw0_rd_out[405]
  PIN rw0_rd_out[406]
    DIRECTION OUTPUT ;
    USE SIGNAL ;
    SHAPE ABUTMENT ;
    PORT
      LAYER M4_m ;
      RECT 138.659 20.784 138.683 20.808 ;
    END
  END rw0_rd_out[406]
  PIN rw0_rd_out[407]
    DIRECTION OUTPUT ;
    USE SIGNAL ;
    SHAPE ABUTMENT ;
    PORT
      LAYER M4_m ;
      RECT 138.659 20.832 138.683 20.856 ;
    END
  END rw0_rd_out[407]
  PIN rw0_rd_out[408]
    DIRECTION OUTPUT ;
    USE SIGNAL ;
    SHAPE ABUTMENT ;
    PORT
      LAYER M4_m ;
      RECT 138.659 20.88 138.683 20.904 ;
    END
  END rw0_rd_out[408]
  PIN rw0_rd_out[409]
    DIRECTION OUTPUT ;
    USE SIGNAL ;
    SHAPE ABUTMENT ;
    PORT
      LAYER M4_m ;
      RECT 138.659 20.928 138.683 20.952 ;
    END
  END rw0_rd_out[409]
  PIN rw0_rd_out[410]
    DIRECTION OUTPUT ;
    USE SIGNAL ;
    SHAPE ABUTMENT ;
    PORT
      LAYER M4_m ;
      RECT 138.659 20.976 138.683 21 ;
    END
  END rw0_rd_out[410]
  PIN rw0_rd_out[411]
    DIRECTION OUTPUT ;
    USE SIGNAL ;
    SHAPE ABUTMENT ;
    PORT
      LAYER M4_m ;
      RECT 138.659 21.024 138.683 21.048 ;
    END
  END rw0_rd_out[411]
  PIN rw0_rd_out[412]
    DIRECTION OUTPUT ;
    USE SIGNAL ;
    SHAPE ABUTMENT ;
    PORT
      LAYER M4_m ;
      RECT 138.659 21.072 138.683 21.096 ;
    END
  END rw0_rd_out[412]
  PIN rw0_rd_out[413]
    DIRECTION OUTPUT ;
    USE SIGNAL ;
    SHAPE ABUTMENT ;
    PORT
      LAYER M4_m ;
      RECT 138.659 21.12 138.683 21.144 ;
    END
  END rw0_rd_out[413]
  PIN rw0_rd_out[414]
    DIRECTION OUTPUT ;
    USE SIGNAL ;
    SHAPE ABUTMENT ;
    PORT
      LAYER M4_m ;
      RECT 138.659 21.168 138.683 21.192 ;
    END
  END rw0_rd_out[414]
  PIN rw0_rd_out[415]
    DIRECTION OUTPUT ;
    USE SIGNAL ;
    SHAPE ABUTMENT ;
    PORT
      LAYER M4_m ;
      RECT 138.659 21.216 138.683 21.24 ;
    END
  END rw0_rd_out[415]
  PIN rw0_rd_out[416]
    DIRECTION OUTPUT ;
    USE SIGNAL ;
    SHAPE ABUTMENT ;
    PORT
      LAYER M4_m ;
      RECT 138.659 21.264 138.683 21.288 ;
    END
  END rw0_rd_out[416]
  PIN rw0_rd_out[417]
    DIRECTION OUTPUT ;
    USE SIGNAL ;
    SHAPE ABUTMENT ;
    PORT
      LAYER M4_m ;
      RECT 138.659 21.312 138.683 21.336 ;
    END
  END rw0_rd_out[417]
  PIN rw0_rd_out[418]
    DIRECTION OUTPUT ;
    USE SIGNAL ;
    SHAPE ABUTMENT ;
    PORT
      LAYER M4_m ;
      RECT 138.659 21.36 138.683 21.384 ;
    END
  END rw0_rd_out[418]
  PIN rw0_rd_out[419]
    DIRECTION OUTPUT ;
    USE SIGNAL ;
    SHAPE ABUTMENT ;
    PORT
      LAYER M4_m ;
      RECT 138.659 21.408 138.683 21.432 ;
    END
  END rw0_rd_out[419]
  PIN rw0_rd_out[420]
    DIRECTION OUTPUT ;
    USE SIGNAL ;
    SHAPE ABUTMENT ;
    PORT
      LAYER M4_m ;
      RECT 138.659 21.456 138.683 21.48 ;
    END
  END rw0_rd_out[420]
  PIN rw0_rd_out[421]
    DIRECTION OUTPUT ;
    USE SIGNAL ;
    SHAPE ABUTMENT ;
    PORT
      LAYER M4_m ;
      RECT 138.659 21.504 138.683 21.528 ;
    END
  END rw0_rd_out[421]
  PIN rw0_rd_out[422]
    DIRECTION OUTPUT ;
    USE SIGNAL ;
    SHAPE ABUTMENT ;
    PORT
      LAYER M4_m ;
      RECT 138.659 21.552 138.683 21.576 ;
    END
  END rw0_rd_out[422]
  PIN rw0_rd_out[423]
    DIRECTION OUTPUT ;
    USE SIGNAL ;
    SHAPE ABUTMENT ;
    PORT
      LAYER M4_m ;
      RECT 138.659 21.6 138.683 21.624 ;
    END
  END rw0_rd_out[423]
  PIN rw0_rd_out[424]
    DIRECTION OUTPUT ;
    USE SIGNAL ;
    SHAPE ABUTMENT ;
    PORT
      LAYER M4_m ;
      RECT 138.659 21.648 138.683 21.672 ;
    END
  END rw0_rd_out[424]
  PIN rw0_rd_out[425]
    DIRECTION OUTPUT ;
    USE SIGNAL ;
    SHAPE ABUTMENT ;
    PORT
      LAYER M4_m ;
      RECT 138.659 21.696 138.683 21.72 ;
    END
  END rw0_rd_out[425]
  PIN rw0_rd_out[426]
    DIRECTION OUTPUT ;
    USE SIGNAL ;
    SHAPE ABUTMENT ;
    PORT
      LAYER M4_m ;
      RECT 138.659 21.744 138.683 21.768 ;
    END
  END rw0_rd_out[426]
  PIN rw0_rd_out[427]
    DIRECTION OUTPUT ;
    USE SIGNAL ;
    SHAPE ABUTMENT ;
    PORT
      LAYER M4_m ;
      RECT 138.659 21.792 138.683 21.816 ;
    END
  END rw0_rd_out[427]
  PIN rw0_rd_out[428]
    DIRECTION OUTPUT ;
    USE SIGNAL ;
    SHAPE ABUTMENT ;
    PORT
      LAYER M4_m ;
      RECT 138.659 21.84 138.683 21.864 ;
    END
  END rw0_rd_out[428]
  PIN rw0_rd_out[429]
    DIRECTION OUTPUT ;
    USE SIGNAL ;
    SHAPE ABUTMENT ;
    PORT
      LAYER M4_m ;
      RECT 138.659 21.888 138.683 21.912 ;
    END
  END rw0_rd_out[429]
  PIN rw0_rd_out[430]
    DIRECTION OUTPUT ;
    USE SIGNAL ;
    SHAPE ABUTMENT ;
    PORT
      LAYER M4_m ;
      RECT 138.659 21.936 138.683 21.96 ;
    END
  END rw0_rd_out[430]
  PIN rw0_rd_out[431]
    DIRECTION OUTPUT ;
    USE SIGNAL ;
    SHAPE ABUTMENT ;
    PORT
      LAYER M4_m ;
      RECT 138.659 21.984 138.683 22.008 ;
    END
  END rw0_rd_out[431]
  PIN rw0_rd_out[432]
    DIRECTION OUTPUT ;
    USE SIGNAL ;
    SHAPE ABUTMENT ;
    PORT
      LAYER M4_m ;
      RECT 138.659 22.032 138.683 22.056 ;
    END
  END rw0_rd_out[432]
  PIN rw0_rd_out[433]
    DIRECTION OUTPUT ;
    USE SIGNAL ;
    SHAPE ABUTMENT ;
    PORT
      LAYER M4_m ;
      RECT 138.659 22.08 138.683 22.104 ;
    END
  END rw0_rd_out[433]
  PIN rw0_rd_out[434]
    DIRECTION OUTPUT ;
    USE SIGNAL ;
    SHAPE ABUTMENT ;
    PORT
      LAYER M4_m ;
      RECT 138.659 22.128 138.683 22.152 ;
    END
  END rw0_rd_out[434]
  PIN rw0_rd_out[435]
    DIRECTION OUTPUT ;
    USE SIGNAL ;
    SHAPE ABUTMENT ;
    PORT
      LAYER M4_m ;
      RECT 138.659 22.176 138.683 22.2 ;
    END
  END rw0_rd_out[435]
  PIN rw0_rd_out[436]
    DIRECTION OUTPUT ;
    USE SIGNAL ;
    SHAPE ABUTMENT ;
    PORT
      LAYER M4_m ;
      RECT 138.659 22.224 138.683 22.248 ;
    END
  END rw0_rd_out[436]
  PIN rw0_rd_out[437]
    DIRECTION OUTPUT ;
    USE SIGNAL ;
    SHAPE ABUTMENT ;
    PORT
      LAYER M4_m ;
      RECT 138.659 22.272 138.683 22.296 ;
    END
  END rw0_rd_out[437]
  PIN rw0_rd_out[438]
    DIRECTION OUTPUT ;
    USE SIGNAL ;
    SHAPE ABUTMENT ;
    PORT
      LAYER M4_m ;
      RECT 138.659 22.32 138.683 22.344 ;
    END
  END rw0_rd_out[438]
  PIN rw0_rd_out[439]
    DIRECTION OUTPUT ;
    USE SIGNAL ;
    SHAPE ABUTMENT ;
    PORT
      LAYER M4_m ;
      RECT 138.659 22.368 138.683 22.392 ;
    END
  END rw0_rd_out[439]
  PIN rw0_rd_out[440]
    DIRECTION OUTPUT ;
    USE SIGNAL ;
    SHAPE ABUTMENT ;
    PORT
      LAYER M4_m ;
      RECT 138.659 22.416 138.683 22.44 ;
    END
  END rw0_rd_out[440]
  PIN rw0_rd_out[441]
    DIRECTION OUTPUT ;
    USE SIGNAL ;
    SHAPE ABUTMENT ;
    PORT
      LAYER M4_m ;
      RECT 138.659 22.464 138.683 22.488 ;
    END
  END rw0_rd_out[441]
  PIN rw0_rd_out[442]
    DIRECTION OUTPUT ;
    USE SIGNAL ;
    SHAPE ABUTMENT ;
    PORT
      LAYER M4_m ;
      RECT 138.659 22.512 138.683 22.536 ;
    END
  END rw0_rd_out[442]
  PIN rw0_rd_out[443]
    DIRECTION OUTPUT ;
    USE SIGNAL ;
    SHAPE ABUTMENT ;
    PORT
      LAYER M4_m ;
      RECT 138.659 22.56 138.683 22.584 ;
    END
  END rw0_rd_out[443]
  PIN rw0_rd_out[444]
    DIRECTION OUTPUT ;
    USE SIGNAL ;
    SHAPE ABUTMENT ;
    PORT
      LAYER M4_m ;
      RECT 138.659 22.608 138.683 22.632 ;
    END
  END rw0_rd_out[444]
  PIN rw0_rd_out[445]
    DIRECTION OUTPUT ;
    USE SIGNAL ;
    SHAPE ABUTMENT ;
    PORT
      LAYER M4_m ;
      RECT 138.659 22.656 138.683 22.68 ;
    END
  END rw0_rd_out[445]
  PIN rw0_rd_out[446]
    DIRECTION OUTPUT ;
    USE SIGNAL ;
    SHAPE ABUTMENT ;
    PORT
      LAYER M4_m ;
      RECT 138.659 22.704 138.683 22.728 ;
    END
  END rw0_rd_out[446]
  PIN rw0_rd_out[447]
    DIRECTION OUTPUT ;
    USE SIGNAL ;
    SHAPE ABUTMENT ;
    PORT
      LAYER M4_m ;
      RECT 138.659 22.752 138.683 22.776 ;
    END
  END rw0_rd_out[447]
  PIN rw0_rd_out[448]
    DIRECTION OUTPUT ;
    USE SIGNAL ;
    SHAPE ABUTMENT ;
    PORT
      LAYER M4_m ;
      RECT 138.659 22.8 138.683 22.824 ;
    END
  END rw0_rd_out[448]
  PIN rw0_rd_out[449]
    DIRECTION OUTPUT ;
    USE SIGNAL ;
    SHAPE ABUTMENT ;
    PORT
      LAYER M4_m ;
      RECT 138.659 22.848 138.683 22.872 ;
    END
  END rw0_rd_out[449]
  PIN rw0_rd_out[450]
    DIRECTION OUTPUT ;
    USE SIGNAL ;
    SHAPE ABUTMENT ;
    PORT
      LAYER M4_m ;
      RECT 138.659 22.896 138.683 22.92 ;
    END
  END rw0_rd_out[450]
  PIN rw0_rd_out[451]
    DIRECTION OUTPUT ;
    USE SIGNAL ;
    SHAPE ABUTMENT ;
    PORT
      LAYER M4_m ;
      RECT 138.659 22.944 138.683 22.968 ;
    END
  END rw0_rd_out[451]
  PIN rw0_rd_out[452]
    DIRECTION OUTPUT ;
    USE SIGNAL ;
    SHAPE ABUTMENT ;
    PORT
      LAYER M4_m ;
      RECT 138.659 22.992 138.683 23.016 ;
    END
  END rw0_rd_out[452]
  PIN rw0_rd_out[453]
    DIRECTION OUTPUT ;
    USE SIGNAL ;
    SHAPE ABUTMENT ;
    PORT
      LAYER M4_m ;
      RECT 138.659 23.04 138.683 23.064 ;
    END
  END rw0_rd_out[453]
  PIN rw0_rd_out[454]
    DIRECTION OUTPUT ;
    USE SIGNAL ;
    SHAPE ABUTMENT ;
    PORT
      LAYER M4_m ;
      RECT 138.659 23.088 138.683 23.112 ;
    END
  END rw0_rd_out[454]
  PIN rw0_rd_out[455]
    DIRECTION OUTPUT ;
    USE SIGNAL ;
    SHAPE ABUTMENT ;
    PORT
      LAYER M4_m ;
      RECT 138.659 23.136 138.683 23.16 ;
    END
  END rw0_rd_out[455]
  PIN rw0_rd_out[456]
    DIRECTION OUTPUT ;
    USE SIGNAL ;
    SHAPE ABUTMENT ;
    PORT
      LAYER M4_m ;
      RECT 138.659 23.184 138.683 23.208 ;
    END
  END rw0_rd_out[456]
  PIN rw0_rd_out[457]
    DIRECTION OUTPUT ;
    USE SIGNAL ;
    SHAPE ABUTMENT ;
    PORT
      LAYER M4_m ;
      RECT 138.659 23.232 138.683 23.256 ;
    END
  END rw0_rd_out[457]
  PIN rw0_rd_out[458]
    DIRECTION OUTPUT ;
    USE SIGNAL ;
    SHAPE ABUTMENT ;
    PORT
      LAYER M4_m ;
      RECT 138.659 23.28 138.683 23.304 ;
    END
  END rw0_rd_out[458]
  PIN rw0_rd_out[459]
    DIRECTION OUTPUT ;
    USE SIGNAL ;
    SHAPE ABUTMENT ;
    PORT
      LAYER M4_m ;
      RECT 138.659 23.328 138.683 23.352 ;
    END
  END rw0_rd_out[459]
  PIN rw0_rd_out[460]
    DIRECTION OUTPUT ;
    USE SIGNAL ;
    SHAPE ABUTMENT ;
    PORT
      LAYER M4_m ;
      RECT 138.659 23.376 138.683 23.4 ;
    END
  END rw0_rd_out[460]
  PIN rw0_rd_out[461]
    DIRECTION OUTPUT ;
    USE SIGNAL ;
    SHAPE ABUTMENT ;
    PORT
      LAYER M4_m ;
      RECT 138.659 23.424 138.683 23.448 ;
    END
  END rw0_rd_out[461]
  PIN rw0_rd_out[462]
    DIRECTION OUTPUT ;
    USE SIGNAL ;
    SHAPE ABUTMENT ;
    PORT
      LAYER M4_m ;
      RECT 138.659 23.472 138.683 23.496 ;
    END
  END rw0_rd_out[462]
  PIN rw0_rd_out[463]
    DIRECTION OUTPUT ;
    USE SIGNAL ;
    SHAPE ABUTMENT ;
    PORT
      LAYER M4_m ;
      RECT 138.659 23.52 138.683 23.544 ;
    END
  END rw0_rd_out[463]
  PIN rw0_rd_out[464]
    DIRECTION OUTPUT ;
    USE SIGNAL ;
    SHAPE ABUTMENT ;
    PORT
      LAYER M4_m ;
      RECT 138.659 23.568 138.683 23.592 ;
    END
  END rw0_rd_out[464]
  PIN rw0_rd_out[465]
    DIRECTION OUTPUT ;
    USE SIGNAL ;
    SHAPE ABUTMENT ;
    PORT
      LAYER M4_m ;
      RECT 138.659 23.616 138.683 23.64 ;
    END
  END rw0_rd_out[465]
  PIN rw0_rd_out[466]
    DIRECTION OUTPUT ;
    USE SIGNAL ;
    SHAPE ABUTMENT ;
    PORT
      LAYER M4_m ;
      RECT 138.659 23.664 138.683 23.688 ;
    END
  END rw0_rd_out[466]
  PIN rw0_rd_out[467]
    DIRECTION OUTPUT ;
    USE SIGNAL ;
    SHAPE ABUTMENT ;
    PORT
      LAYER M4_m ;
      RECT 138.659 23.712 138.683 23.736 ;
    END
  END rw0_rd_out[467]
  PIN rw0_rd_out[468]
    DIRECTION OUTPUT ;
    USE SIGNAL ;
    SHAPE ABUTMENT ;
    PORT
      LAYER M4_m ;
      RECT 138.659 23.76 138.683 23.784 ;
    END
  END rw0_rd_out[468]
  PIN rw0_rd_out[469]
    DIRECTION OUTPUT ;
    USE SIGNAL ;
    SHAPE ABUTMENT ;
    PORT
      LAYER M4_m ;
      RECT 138.659 23.808 138.683 23.832 ;
    END
  END rw0_rd_out[469]
  PIN rw0_rd_out[470]
    DIRECTION OUTPUT ;
    USE SIGNAL ;
    SHAPE ABUTMENT ;
    PORT
      LAYER M4_m ;
      RECT 138.659 23.856 138.683 23.88 ;
    END
  END rw0_rd_out[470]
  PIN rw0_rd_out[471]
    DIRECTION OUTPUT ;
    USE SIGNAL ;
    SHAPE ABUTMENT ;
    PORT
      LAYER M4_m ;
      RECT 138.659 23.904 138.683 23.928 ;
    END
  END rw0_rd_out[471]
  PIN rw0_rd_out[472]
    DIRECTION OUTPUT ;
    USE SIGNAL ;
    SHAPE ABUTMENT ;
    PORT
      LAYER M4_m ;
      RECT 138.659 23.952 138.683 23.976 ;
    END
  END rw0_rd_out[472]
  PIN rw0_rd_out[473]
    DIRECTION OUTPUT ;
    USE SIGNAL ;
    SHAPE ABUTMENT ;
    PORT
      LAYER M4_m ;
      RECT 138.659 24 138.683 24.024 ;
    END
  END rw0_rd_out[473]
  PIN rw0_rd_out[474]
    DIRECTION OUTPUT ;
    USE SIGNAL ;
    SHAPE ABUTMENT ;
    PORT
      LAYER M4_m ;
      RECT 138.659 24.048 138.683 24.072 ;
    END
  END rw0_rd_out[474]
  PIN rw0_rd_out[475]
    DIRECTION OUTPUT ;
    USE SIGNAL ;
    SHAPE ABUTMENT ;
    PORT
      LAYER M4_m ;
      RECT 138.659 24.096 138.683 24.12 ;
    END
  END rw0_rd_out[475]
  PIN rw0_rd_out[476]
    DIRECTION OUTPUT ;
    USE SIGNAL ;
    SHAPE ABUTMENT ;
    PORT
      LAYER M4_m ;
      RECT 138.659 24.144 138.683 24.168 ;
    END
  END rw0_rd_out[476]
  PIN rw0_rd_out[477]
    DIRECTION OUTPUT ;
    USE SIGNAL ;
    SHAPE ABUTMENT ;
    PORT
      LAYER M4_m ;
      RECT 138.659 24.192 138.683 24.216 ;
    END
  END rw0_rd_out[477]
  PIN rw0_rd_out[478]
    DIRECTION OUTPUT ;
    USE SIGNAL ;
    SHAPE ABUTMENT ;
    PORT
      LAYER M4_m ;
      RECT 138.659 24.24 138.683 24.264 ;
    END
  END rw0_rd_out[478]
  PIN rw0_rd_out[479]
    DIRECTION OUTPUT ;
    USE SIGNAL ;
    SHAPE ABUTMENT ;
    PORT
      LAYER M4_m ;
      RECT 138.659 24.288 138.683 24.312 ;
    END
  END rw0_rd_out[479]
  PIN rw0_rd_out[480]
    DIRECTION OUTPUT ;
    USE SIGNAL ;
    SHAPE ABUTMENT ;
    PORT
      LAYER M4_m ;
      RECT 138.659 24.336 138.683 24.36 ;
    END
  END rw0_rd_out[480]
  PIN rw0_rd_out[481]
    DIRECTION OUTPUT ;
    USE SIGNAL ;
    SHAPE ABUTMENT ;
    PORT
      LAYER M4_m ;
      RECT 138.659 24.384 138.683 24.408 ;
    END
  END rw0_rd_out[481]
  PIN rw0_rd_out[482]
    DIRECTION OUTPUT ;
    USE SIGNAL ;
    SHAPE ABUTMENT ;
    PORT
      LAYER M4_m ;
      RECT 138.659 24.432 138.683 24.456 ;
    END
  END rw0_rd_out[482]
  PIN rw0_rd_out[483]
    DIRECTION OUTPUT ;
    USE SIGNAL ;
    SHAPE ABUTMENT ;
    PORT
      LAYER M4_m ;
      RECT 138.659 24.48 138.683 24.504 ;
    END
  END rw0_rd_out[483]
  PIN rw0_rd_out[484]
    DIRECTION OUTPUT ;
    USE SIGNAL ;
    SHAPE ABUTMENT ;
    PORT
      LAYER M4_m ;
      RECT 138.659 24.528 138.683 24.552 ;
    END
  END rw0_rd_out[484]
  PIN rw0_rd_out[485]
    DIRECTION OUTPUT ;
    USE SIGNAL ;
    SHAPE ABUTMENT ;
    PORT
      LAYER M4_m ;
      RECT 138.659 24.576 138.683 24.6 ;
    END
  END rw0_rd_out[485]
  PIN rw0_rd_out[486]
    DIRECTION OUTPUT ;
    USE SIGNAL ;
    SHAPE ABUTMENT ;
    PORT
      LAYER M4_m ;
      RECT 138.659 24.624 138.683 24.648 ;
    END
  END rw0_rd_out[486]
  PIN rw0_rd_out[487]
    DIRECTION OUTPUT ;
    USE SIGNAL ;
    SHAPE ABUTMENT ;
    PORT
      LAYER M4_m ;
      RECT 138.659 24.672 138.683 24.696 ;
    END
  END rw0_rd_out[487]
  PIN rw0_rd_out[488]
    DIRECTION OUTPUT ;
    USE SIGNAL ;
    SHAPE ABUTMENT ;
    PORT
      LAYER M4_m ;
      RECT 138.659 24.72 138.683 24.744 ;
    END
  END rw0_rd_out[488]
  PIN rw0_rd_out[489]
    DIRECTION OUTPUT ;
    USE SIGNAL ;
    SHAPE ABUTMENT ;
    PORT
      LAYER M4_m ;
      RECT 138.659 24.768 138.683 24.792 ;
    END
  END rw0_rd_out[489]
  PIN rw0_rd_out[490]
    DIRECTION OUTPUT ;
    USE SIGNAL ;
    SHAPE ABUTMENT ;
    PORT
      LAYER M4_m ;
      RECT 138.659 24.816 138.683 24.84 ;
    END
  END rw0_rd_out[490]
  PIN rw0_rd_out[491]
    DIRECTION OUTPUT ;
    USE SIGNAL ;
    SHAPE ABUTMENT ;
    PORT
      LAYER M4_m ;
      RECT 138.659 24.864 138.683 24.888 ;
    END
  END rw0_rd_out[491]
  PIN rw0_rd_out[492]
    DIRECTION OUTPUT ;
    USE SIGNAL ;
    SHAPE ABUTMENT ;
    PORT
      LAYER M4_m ;
      RECT 138.659 24.912 138.683 24.936 ;
    END
  END rw0_rd_out[492]
  PIN rw0_rd_out[493]
    DIRECTION OUTPUT ;
    USE SIGNAL ;
    SHAPE ABUTMENT ;
    PORT
      LAYER M4_m ;
      RECT 138.659 24.96 138.683 24.984 ;
    END
  END rw0_rd_out[493]
  PIN rw0_rd_out[494]
    DIRECTION OUTPUT ;
    USE SIGNAL ;
    SHAPE ABUTMENT ;
    PORT
      LAYER M4_m ;
      RECT 138.659 25.008 138.683 25.032 ;
    END
  END rw0_rd_out[494]
  PIN rw0_rd_out[495]
    DIRECTION OUTPUT ;
    USE SIGNAL ;
    SHAPE ABUTMENT ;
    PORT
      LAYER M4_m ;
      RECT 138.659 25.056 138.683 25.08 ;
    END
  END rw0_rd_out[495]
  PIN rw0_rd_out[496]
    DIRECTION OUTPUT ;
    USE SIGNAL ;
    SHAPE ABUTMENT ;
    PORT
      LAYER M4_m ;
      RECT 138.659 25.104 138.683 25.128 ;
    END
  END rw0_rd_out[496]
  PIN rw0_rd_out[497]
    DIRECTION OUTPUT ;
    USE SIGNAL ;
    SHAPE ABUTMENT ;
    PORT
      LAYER M4_m ;
      RECT 138.659 25.152 138.683 25.176 ;
    END
  END rw0_rd_out[497]
  PIN rw0_rd_out[498]
    DIRECTION OUTPUT ;
    USE SIGNAL ;
    SHAPE ABUTMENT ;
    PORT
      LAYER M4_m ;
      RECT 138.659 25.2 138.683 25.224 ;
    END
  END rw0_rd_out[498]
  PIN rw0_rd_out[499]
    DIRECTION OUTPUT ;
    USE SIGNAL ;
    SHAPE ABUTMENT ;
    PORT
      LAYER M4_m ;
      RECT 138.659 25.248 138.683 25.272 ;
    END
  END rw0_rd_out[499]
  PIN rw0_rd_out[500]
    DIRECTION OUTPUT ;
    USE SIGNAL ;
    SHAPE ABUTMENT ;
    PORT
      LAYER M4_m ;
      RECT 138.659 25.296 138.683 25.32 ;
    END
  END rw0_rd_out[500]
  PIN rw0_rd_out[501]
    DIRECTION OUTPUT ;
    USE SIGNAL ;
    SHAPE ABUTMENT ;
    PORT
      LAYER M4_m ;
      RECT 138.659 25.344 138.683 25.368 ;
    END
  END rw0_rd_out[501]
  PIN rw0_rd_out[502]
    DIRECTION OUTPUT ;
    USE SIGNAL ;
    SHAPE ABUTMENT ;
    PORT
      LAYER M4_m ;
      RECT 138.659 25.392 138.683 25.416 ;
    END
  END rw0_rd_out[502]
  PIN rw0_rd_out[503]
    DIRECTION OUTPUT ;
    USE SIGNAL ;
    SHAPE ABUTMENT ;
    PORT
      LAYER M4_m ;
      RECT 138.659 25.44 138.683 25.464 ;
    END
  END rw0_rd_out[503]
  PIN rw0_rd_out[504]
    DIRECTION OUTPUT ;
    USE SIGNAL ;
    SHAPE ABUTMENT ;
    PORT
      LAYER M4_m ;
      RECT 138.659 25.488 138.683 25.512 ;
    END
  END rw0_rd_out[504]
  PIN rw0_rd_out[505]
    DIRECTION OUTPUT ;
    USE SIGNAL ;
    SHAPE ABUTMENT ;
    PORT
      LAYER M4_m ;
      RECT 138.659 25.536 138.683 25.56 ;
    END
  END rw0_rd_out[505]
  PIN rw0_rd_out[506]
    DIRECTION OUTPUT ;
    USE SIGNAL ;
    SHAPE ABUTMENT ;
    PORT
      LAYER M4_m ;
      RECT 138.659 25.584 138.683 25.608 ;
    END
  END rw0_rd_out[506]
  PIN rw0_rd_out[507]
    DIRECTION OUTPUT ;
    USE SIGNAL ;
    SHAPE ABUTMENT ;
    PORT
      LAYER M4_m ;
      RECT 138.659 25.632 138.683 25.656 ;
    END
  END rw0_rd_out[507]
  PIN rw0_rd_out[508]
    DIRECTION OUTPUT ;
    USE SIGNAL ;
    SHAPE ABUTMENT ;
    PORT
      LAYER M4_m ;
      RECT 138.659 25.68 138.683 25.704 ;
    END
  END rw0_rd_out[508]
  PIN rw0_rd_out[509]
    DIRECTION OUTPUT ;
    USE SIGNAL ;
    SHAPE ABUTMENT ;
    PORT
      LAYER M4_m ;
      RECT 138.659 25.728 138.683 25.752 ;
    END
  END rw0_rd_out[509]
  PIN rw0_rd_out[510]
    DIRECTION OUTPUT ;
    USE SIGNAL ;
    SHAPE ABUTMENT ;
    PORT
      LAYER M4_m ;
      RECT 138.659 25.776 138.683 25.8 ;
    END
  END rw0_rd_out[510]
  PIN rw0_rd_out[511]
    DIRECTION OUTPUT ;
    USE SIGNAL ;
    SHAPE ABUTMENT ;
    PORT
      LAYER M4_m ;
      RECT 138.659 25.824 138.683 25.848 ;
    END
  END rw0_rd_out[511]
  PIN rw0_addr_in[0]
    DIRECTION INPUT ;
    USE SIGNAL ;
    SHAPE ABUTMENT ;
    PORT
      LAYER M4_m ;
      RECT 138.659 25.872 138.683 25.896 ;
    END
  END rw0_addr_in[0]
  PIN rw0_addr_in[1]
    DIRECTION INPUT ;
    USE SIGNAL ;
    SHAPE ABUTMENT ;
    PORT
      LAYER M4_m ;
      RECT 138.659 25.92 138.683 25.944 ;
    END
  END rw0_addr_in[1]
  PIN rw0_addr_in[2]
    DIRECTION INPUT ;
    USE SIGNAL ;
    SHAPE ABUTMENT ;
    PORT
      LAYER M4_m ;
      RECT 138.659 25.968 138.683 25.992 ;
    END
  END rw0_addr_in[2]
  PIN rw0_addr_in[3]
    DIRECTION INPUT ;
    USE SIGNAL ;
    SHAPE ABUTMENT ;
    PORT
      LAYER M4_m ;
      RECT 138.659 26.016 138.683 26.04 ;
    END
  END rw0_addr_in[3]
  PIN rw0_addr_in[4]
    DIRECTION INPUT ;
    USE SIGNAL ;
    SHAPE ABUTMENT ;
    PORT
      LAYER M4_m ;
      RECT 138.659 26.064 138.683 26.088 ;
    END
  END rw0_addr_in[4]
  PIN rw0_addr_in[5]
    DIRECTION INPUT ;
    USE SIGNAL ;
    SHAPE ABUTMENT ;
    PORT
      LAYER M4_m ;
      RECT 138.659 26.112 138.683 26.136 ;
    END
  END rw0_addr_in[5]
  PIN rw0_addr_in[6]
    DIRECTION INPUT ;
    USE SIGNAL ;
    SHAPE ABUTMENT ;
    PORT
      LAYER M4_m ;
      RECT 138.659 26.16 138.683 26.184 ;
    END
  END rw0_addr_in[6]
  PIN rw0_addr_in[7]
    DIRECTION INPUT ;
    USE SIGNAL ;
    SHAPE ABUTMENT ;
    PORT
      LAYER M4_m ;
      RECT 138.659 26.208 138.683 26.232 ;
    END
  END rw0_addr_in[7]
  PIN rw0_we_in
    DIRECTION INPUT ;
    USE SIGNAL ;
    SHAPE ABUTMENT ;
    PORT
      LAYER M4_m ;
      RECT 138.659 26.256 138.683 26.28 ;
    END
  END rw0_we_in
  PIN rw0_ce_in
    DIRECTION INPUT ;
    USE SIGNAL ;
    SHAPE ABUTMENT ;
    PORT
      LAYER M4_m ;
      RECT 138.659 26.304 138.683 26.328 ;
    END
  END rw0_ce_in
  PIN rw0_clk
    DIRECTION INPUT ;
    USE SIGNAL ;
    SHAPE ABUTMENT ;
    PORT
      LAYER M4_m ;
      RECT 138.659 26.352 138.683 26.376 ;
    END
  END rw0_clk
  PIN VSS
    DIRECTION INOUT ;
    USE GROUND ;
    PORT
      LAYER M4_m ;
      RECT 0.048 0 138.635 0.096 ;
      RECT 0.048 0.768 138.635 0.864 ;
      RECT 0.048 1.536 138.635 1.632 ;
      RECT 0.048 2.304 138.635 2.4 ;
      RECT 0.048 3.072 138.635 3.168 ;
      RECT 0.048 3.84 138.635 3.936 ;
      RECT 0.048 4.608 138.635 4.704 ;
      RECT 0.048 5.376 138.635 5.472 ;
      RECT 0.048 6.144 138.635 6.24 ;
      RECT 0.048 6.912 138.635 7.008 ;
      RECT 0.048 7.68 138.635 7.776 ;
      RECT 0.048 8.448 138.635 8.544 ;
      RECT 0.048 9.216 138.635 9.312 ;
      RECT 0.048 9.984 138.635 10.08 ;
      RECT 0.048 10.752 138.635 10.848 ;
      RECT 0.048 11.52 138.635 11.616 ;
      RECT 0.048 12.288 138.635 12.384 ;
      RECT 0.048 13.056 138.635 13.152 ;
      RECT 0.048 13.824 138.635 13.92 ;
      RECT 0.048 14.592 138.635 14.688 ;
      RECT 0.048 15.36 138.635 15.456 ;
      RECT 0.048 16.128 138.635 16.224 ;
      RECT 0.048 16.896 138.635 16.992 ;
      RECT 0.048 17.664 138.635 17.76 ;
      RECT 0.048 18.432 138.635 18.528 ;
      RECT 0.048 19.2 138.635 19.296 ;
      RECT 0.048 19.968 138.635 20.064 ;
      RECT 0.048 20.736 138.635 20.832 ;
      RECT 0.048 21.504 138.635 21.6 ;
      RECT 0.048 22.272 138.635 22.368 ;
      RECT 0.048 23.04 138.635 23.136 ;
      RECT 0.048 23.808 138.635 23.904 ;
      RECT 0.048 24.576 138.635 24.672 ;
      RECT 0.048 25.344 138.635 25.44 ;
      RECT 0.048 26.112 138.635 26.208 ;
      RECT 0.048 26.88 138.635 26.976 ;
      RECT 0.048 27.648 138.635 27.744 ;
      RECT 0.048 28.416 138.635 28.512 ;
      RECT 0.048 29.184 138.635 29.28 ;
      RECT 0.048 29.952 138.635 30.048 ;
      RECT 0.048 30.72 138.635 30.816 ;
      RECT 0.048 31.488 138.635 31.584 ;
      RECT 0.048 32.256 138.635 32.352 ;
      RECT 0.048 33.024 138.635 33.12 ;
      RECT 0.048 33.792 138.635 33.888 ;
      RECT 0.048 34.56 138.635 34.656 ;
      RECT 0.048 35.328 138.635 35.424 ;
      RECT 0.048 36.096 138.635 36.192 ;
      RECT 0.048 36.864 138.635 36.96 ;
      RECT 0.048 37.632 138.635 37.728 ;
      RECT 0.048 38.4 138.635 38.496 ;
      RECT 0.048 39.168 138.635 39.264 ;
      RECT 0.048 39.936 138.635 40.032 ;
      RECT 0.048 40.704 138.635 40.8 ;
      RECT 0.048 41.472 138.635 41.568 ;
      RECT 0.048 42.24 138.635 42.336 ;
      RECT 0.048 43.008 138.635 43.104 ;
    END
  END VSS
  PIN VDD
    DIRECTION INOUT ;
    USE POWER ;
    PORT
      LAYER M4_m ;
      RECT 0.048 0.384 138.635 0.48 ;
      RECT 0.048 1.152 138.635 1.248 ;
      RECT 0.048 1.92 138.635 2.016 ;
      RECT 0.048 2.688 138.635 2.784 ;
      RECT 0.048 3.456 138.635 3.552 ;
      RECT 0.048 4.224 138.635 4.32 ;
      RECT 0.048 4.992 138.635 5.088 ;
      RECT 0.048 5.76 138.635 5.856 ;
      RECT 0.048 6.528 138.635 6.624 ;
      RECT 0.048 7.296 138.635 7.392 ;
      RECT 0.048 8.064 138.635 8.16 ;
      RECT 0.048 8.832 138.635 8.928 ;
      RECT 0.048 9.6 138.635 9.696 ;
      RECT 0.048 10.368 138.635 10.464 ;
      RECT 0.048 11.136 138.635 11.232 ;
      RECT 0.048 11.904 138.635 12 ;
      RECT 0.048 12.672 138.635 12.768 ;
      RECT 0.048 13.44 138.635 13.536 ;
      RECT 0.048 14.208 138.635 14.304 ;
      RECT 0.048 14.976 138.635 15.072 ;
      RECT 0.048 15.744 138.635 15.84 ;
      RECT 0.048 16.512 138.635 16.608 ;
      RECT 0.048 17.28 138.635 17.376 ;
      RECT 0.048 18.048 138.635 18.144 ;
      RECT 0.048 18.816 138.635 18.912 ;
      RECT 0.048 19.584 138.635 19.68 ;
      RECT 0.048 20.352 138.635 20.448 ;
      RECT 0.048 21.12 138.635 21.216 ;
      RECT 0.048 21.888 138.635 21.984 ;
      RECT 0.048 22.656 138.635 22.752 ;
      RECT 0.048 23.424 138.635 23.52 ;
      RECT 0.048 24.192 138.635 24.288 ;
      RECT 0.048 24.96 138.635 25.056 ;
      RECT 0.048 25.728 138.635 25.824 ;
      RECT 0.048 26.496 138.635 26.592 ;
      RECT 0.048 27.264 138.635 27.36 ;
      RECT 0.048 28.032 138.635 28.128 ;
      RECT 0.048 28.8 138.635 28.896 ;
      RECT 0.048 29.568 138.635 29.664 ;
      RECT 0.048 30.336 138.635 30.432 ;
      RECT 0.048 31.104 138.635 31.2 ;
      RECT 0.048 31.872 138.635 31.968 ;
      RECT 0.048 32.64 138.635 32.736 ;
      RECT 0.048 33.408 138.635 33.504 ;
      RECT 0.048 34.176 138.635 34.272 ;
      RECT 0.048 34.944 138.635 35.04 ;
      RECT 0.048 35.712 138.635 35.808 ;
      RECT 0.048 36.48 138.635 36.576 ;
      RECT 0.048 37.248 138.635 37.344 ;
      RECT 0.048 38.016 138.635 38.112 ;
      RECT 0.048 38.784 138.635 38.88 ;
      RECT 0.048 39.552 138.635 39.648 ;
      RECT 0.048 40.32 138.635 40.416 ;
      RECT 0.048 41.088 138.635 41.184 ;
      RECT 0.048 41.856 138.635 41.952 ;
      RECT 0.048 42.624 138.635 42.72 ;
    END
  END VDD
  OBS
    LAYER M1_m ;
    RECT 0 0 138.683 43.339 ;
    LAYER M2_m ;
    RECT 0 0 138.683 43.339 ;
    LAYER M3_m ;
    RECT 0 0 138.683 43.339 ;
  END
END ht_asap7_rocketgemmini_rockettile_dcache_data_arrays_0_ext_upper

END LIBRARY
